VERSION 5.8 ;
BUSBITCHARS "[]" ;
DIVIDERCHAR "/" ;
UNITS
    DATABASE MICRONS 1000 ;
END UNITS

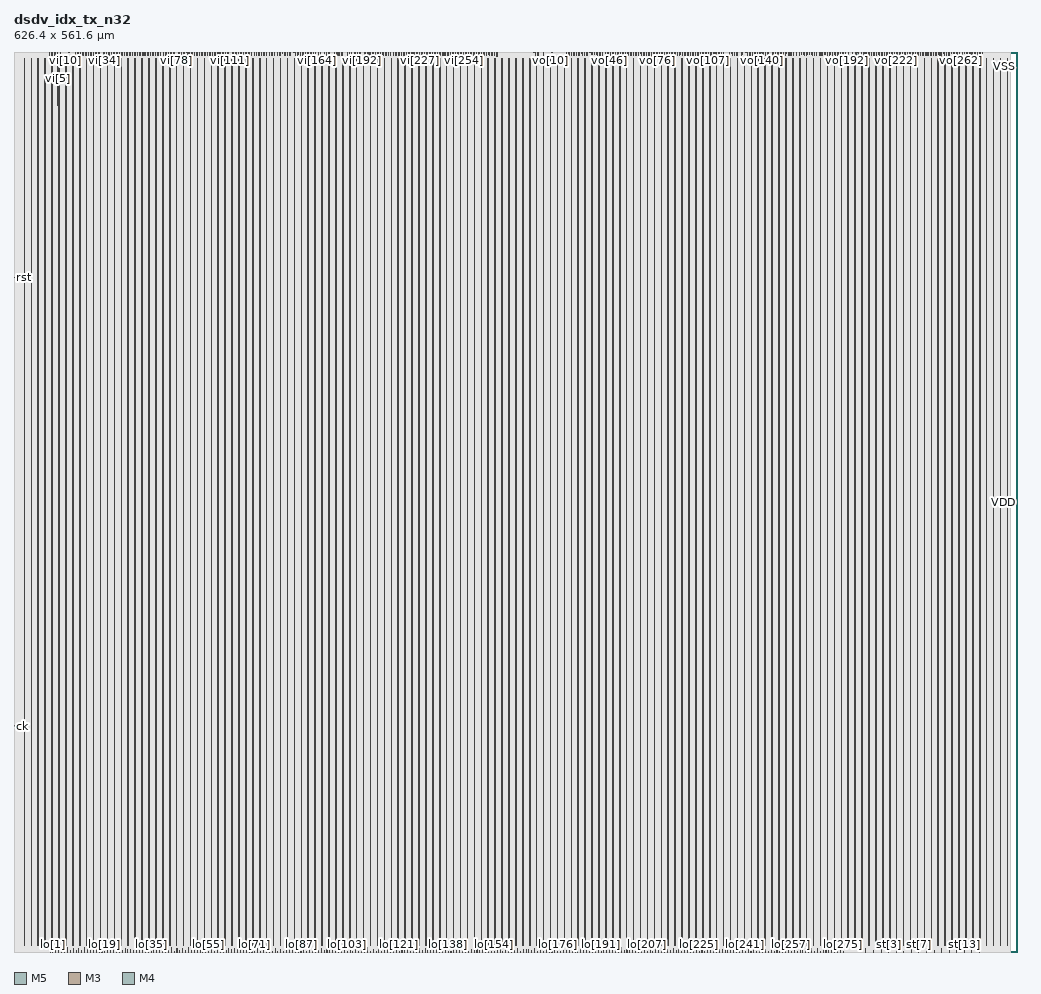
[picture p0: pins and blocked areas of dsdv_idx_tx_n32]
MACRO dsdv_idx_tx_n32
  FOREIGN dsdv_idx_tx_n32 0 0 ;
  CLASS BLOCK ;
  SIZE 626.4 BY 561.6 ;
  PIN ck
    DIRECTION INPUT ;
    USE SIGNAL ;
    PORT
      LAYER M5 ;
        RECT  0 140.652 0.12 141.132 ;
    END
  END ck
  PIN lo[0]
    DIRECTION OUTPUT ;
    USE SIGNAL ;
    PORT
      LAYER M3 ;
        RECT  22.5 0.012 22.518 2.227 ;
        RECT  22.5 0 22.518 0.038 ;
    END
  END lo[0]
  PIN lo[100]
    DIRECTION OUTPUT ;
    USE SIGNAL ;
    PORT
      LAYER M3 ;
        RECT  202.5 0.012 202.518 1.606 ;
        RECT  202.5 0 202.518 0.038 ;
    END
  END lo[100]
  PIN lo[101]
    DIRECTION OUTPUT ;
    USE SIGNAL ;
    PORT
      LAYER M5 ;
        RECT  204.288 0.016 204.312 1.187 ;
        RECT  204.288 0 204.312 0.084 ;
    END
  END lo[101]
  PIN lo[102]
    DIRECTION OUTPUT ;
    USE SIGNAL ;
    PORT
      LAYER M3 ;
        RECT  206.1 0.012 206.118 1.021 ;
        RECT  206.1 0 206.118 0.038 ;
    END
  END lo[102]
  PIN lo[103]
    DIRECTION OUTPUT ;
    USE SIGNAL ;
    PORT
      LAYER M5 ;
        RECT  207.888 0.016 207.912 0.131 ;
        RECT  207.888 0 207.912 0.084 ;
    END
  END lo[103]
  PIN lo[104]
    DIRECTION OUTPUT ;
    USE SIGNAL ;
    PORT
      LAYER M3 ;
        RECT  209.7 0.012 209.718 0.949 ;
        RECT  209.7 0 209.718 0.038 ;
    END
  END lo[104]
  PIN lo[105]
    DIRECTION OUTPUT ;
    USE SIGNAL ;
    PORT
      LAYER M5 ;
        RECT  211.488 0.016 211.512 0.131 ;
        RECT  211.488 0 211.512 0.084 ;
    END
  END lo[105]
  PIN lo[106]
    DIRECTION OUTPUT ;
    USE SIGNAL ;
    PORT
      LAYER M3 ;
        RECT  213.3 0.012 213.318 1.723 ;
        RECT  213.3 0 213.318 0.038 ;
    END
  END lo[106]
  PIN lo[107]
    DIRECTION OUTPUT ;
    USE SIGNAL ;
    PORT
      LAYER M5 ;
        RECT  215.088 0.016 215.112 0.131 ;
        RECT  215.088 0 215.112 0.084 ;
    END
  END lo[107]
  PIN lo[108]
    DIRECTION OUTPUT ;
    USE SIGNAL ;
    PORT
      LAYER M3 ;
        RECT  216.9 0.012 216.918 1.723 ;
        RECT  216.9 0 216.918 0.038 ;
    END
  END lo[108]
  PIN lo[109]
    DIRECTION OUTPUT ;
    USE SIGNAL ;
    PORT
      LAYER M5 ;
        RECT  218.688 0.016 218.712 1.187 ;
        RECT  218.688 0 218.712 0.084 ;
    END
  END lo[109]
  PIN lo[10]
    DIRECTION OUTPUT ;
    USE SIGNAL ;
    PORT
      LAYER M3 ;
        RECT  40.5 0.012 40.518 2.143 ;
        RECT  40.5 0 40.518 0.038 ;
    END
  END lo[10]
  PIN lo[110]
    DIRECTION OUTPUT ;
    USE SIGNAL ;
    PORT
      LAYER M3 ;
        RECT  220.5 0.012 220.518 2.767 ;
        RECT  220.5 0 220.518 0.038 ;
    END
  END lo[110]
  PIN lo[111]
    DIRECTION OUTPUT ;
    USE SIGNAL ;
    PORT
      LAYER M5 ;
        RECT  222.288 0.016 222.312 0.131 ;
        RECT  222.288 0 222.312 0.084 ;
    END
  END lo[111]
  PIN lo[112]
    DIRECTION OUTPUT ;
    USE SIGNAL ;
    PORT
      LAYER M3 ;
        RECT  224.1 0.012 224.118 1.723 ;
        RECT  224.1 0 224.118 0.038 ;
    END
  END lo[112]
  PIN lo[113]
    DIRECTION OUTPUT ;
    USE SIGNAL ;
    PORT
      LAYER M5 ;
        RECT  225.888 0.016 225.912 0.131 ;
        RECT  225.888 0 225.912 0.084 ;
    END
  END lo[113]
  PIN lo[114]
    DIRECTION OUTPUT ;
    USE SIGNAL ;
    PORT
      LAYER M3 ;
        RECT  227.7 0.012 227.718 2.219 ;
        RECT  227.7 0 227.718 0.038 ;
    END
  END lo[114]
  PIN lo[115]
    DIRECTION OUTPUT ;
    USE SIGNAL ;
    PORT
      LAYER M5 ;
        RECT  229.488 0.016 229.512 0.131 ;
        RECT  229.488 0 229.512 0.084 ;
    END
  END lo[115]
  PIN lo[116]
    DIRECTION OUTPUT ;
    USE SIGNAL ;
    PORT
      LAYER M3 ;
        RECT  231.3 0.012 231.318 1.993 ;
        RECT  231.3 0 231.318 0.038 ;
    END
  END lo[116]
  PIN lo[117]
    DIRECTION OUTPUT ;
    USE SIGNAL ;
    PORT
      LAYER M5 ;
        RECT  233.088 0.016 233.112 1.763 ;
        RECT  233.088 0 233.112 0.084 ;
    END
  END lo[117]
  PIN lo[118]
    DIRECTION OUTPUT ;
    USE SIGNAL ;
    PORT
      LAYER M3 ;
        RECT  234.9 0.012 234.918 2.143 ;
        RECT  234.9 0 234.918 0.038 ;
    END
  END lo[118]
  PIN lo[119]
    DIRECTION OUTPUT ;
    USE SIGNAL ;
    PORT
      LAYER M5 ;
        RECT  236.688 0.016 236.712 0.131 ;
        RECT  236.688 0 236.712 0.084 ;
    END
  END lo[119]
  PIN lo[11]
    DIRECTION OUTPUT ;
    USE SIGNAL ;
    PORT
      LAYER M5 ;
        RECT  42.288 0.016 42.312 1.187 ;
        RECT  42.288 0 42.312 0.084 ;
    END
  END lo[11]
  PIN lo[120]
    DIRECTION OUTPUT ;
    USE SIGNAL ;
    PORT
      LAYER M3 ;
        RECT  238.5 0.012 238.518 1.723 ;
        RECT  238.5 0 238.518 0.038 ;
    END
  END lo[120]
  PIN lo[121]
    DIRECTION OUTPUT ;
    USE SIGNAL ;
    PORT
      LAYER M5 ;
        RECT  240.288 0.016 240.312 0.085 ;
        RECT  240.288 0 240.312 0.084 ;
    END
  END lo[121]
  PIN lo[122]
    DIRECTION OUTPUT ;
    USE SIGNAL ;
    PORT
      LAYER M3 ;
        RECT  242.1 0.012 242.118 2.029 ;
        RECT  242.1 0 242.118 0.038 ;
    END
  END lo[122]
  PIN lo[123]
    DIRECTION OUTPUT ;
    USE SIGNAL ;
    PORT
      LAYER M5 ;
        RECT  243.888 0.016 243.912 1.187 ;
        RECT  243.888 0 243.912 0.084 ;
    END
  END lo[123]
  PIN lo[124]
    DIRECTION OUTPUT ;
    USE SIGNAL ;
    PORT
      LAYER M3 ;
        RECT  245.7 0.012 245.718 2.143 ;
        RECT  245.7 0 245.718 0.038 ;
    END
  END lo[124]
  PIN lo[125]
    DIRECTION OUTPUT ;
    USE SIGNAL ;
    PORT
      LAYER M5 ;
        RECT  247.488 0.016 247.512 0.131 ;
        RECT  247.488 0 247.512 0.084 ;
    END
  END lo[125]
  PIN lo[126]
    DIRECTION OUTPUT ;
    USE SIGNAL ;
    PORT
      LAYER M3 ;
        RECT  249.3 0.012 249.318 1.723 ;
        RECT  249.3 0 249.318 0.038 ;
    END
  END lo[126]
  PIN lo[127]
    DIRECTION OUTPUT ;
    USE SIGNAL ;
    PORT
      LAYER M5 ;
        RECT  251.088 0.016 251.112 1.187 ;
        RECT  251.088 0 251.112 0.084 ;
    END
  END lo[127]
  PIN lo[128]
    DIRECTION OUTPUT ;
    USE SIGNAL ;
    PORT
      LAYER M3 ;
        RECT  252.9 0.012 252.918 2.219 ;
        RECT  252.9 0 252.918 0.038 ;
    END
  END lo[128]
  PIN lo[129]
    DIRECTION OUTPUT ;
    USE SIGNAL ;
    PORT
      LAYER M5 ;
        RECT  254.688 0.016 254.712 1.187 ;
        RECT  254.688 0 254.712 0.084 ;
    END
  END lo[129]
  PIN lo[12]
    DIRECTION OUTPUT ;
    USE SIGNAL ;
    PORT
      LAYER M3 ;
        RECT  44.1 0.012 44.118 2.669 ;
        RECT  44.1 0 44.118 0.038 ;
    END
  END lo[12]
  PIN lo[130]
    DIRECTION OUTPUT ;
    USE SIGNAL ;
    PORT
      LAYER M3 ;
        RECT  256.5 0.012 256.518 2.143 ;
        RECT  256.5 0 256.518 0.038 ;
    END
  END lo[130]
  PIN lo[131]
    DIRECTION OUTPUT ;
    USE SIGNAL ;
    PORT
      LAYER M5 ;
        RECT  258.288 0.016 258.312 1.187 ;
        RECT  258.288 0 258.312 0.084 ;
    END
  END lo[131]
  PIN lo[132]
    DIRECTION OUTPUT ;
    USE SIGNAL ;
    PORT
      LAYER M3 ;
        RECT  260.1 0.012 260.118 1.066 ;
        RECT  260.1 0 260.118 0.038 ;
    END
  END lo[132]
  PIN lo[133]
    DIRECTION OUTPUT ;
    USE SIGNAL ;
    PORT
      LAYER M5 ;
        RECT  261.888 0.016 261.912 2.137 ;
        RECT  261.888 0 261.912 0.084 ;
    END
  END lo[133]
  PIN lo[134]
    DIRECTION OUTPUT ;
    USE SIGNAL ;
    PORT
      LAYER M3 ;
        RECT  263.7 0.012 263.718 1.723 ;
        RECT  263.7 0 263.718 0.038 ;
    END
  END lo[134]
  PIN lo[135]
    DIRECTION OUTPUT ;
    USE SIGNAL ;
    PORT
      LAYER M5 ;
        RECT  265.488 0.016 265.512 1.763 ;
        RECT  265.488 0 265.512 0.084 ;
    END
  END lo[135]
  PIN lo[136]
    DIRECTION OUTPUT ;
    USE SIGNAL ;
    PORT
      LAYER M3 ;
        RECT  267.3 0.012 267.318 1.723 ;
        RECT  267.3 0 267.318 0.038 ;
    END
  END lo[136]
  PIN lo[137]
    DIRECTION OUTPUT ;
    USE SIGNAL ;
    PORT
      LAYER M5 ;
        RECT  269.088 0.016 269.112 1.187 ;
        RECT  269.088 0 269.112 0.084 ;
    END
  END lo[137]
  PIN lo[138]
    DIRECTION OUTPUT ;
    USE SIGNAL ;
    PORT
      LAYER M3 ;
        RECT  270.9 0.012 270.918 0.077 ;
        RECT  270.9 0 270.918 0.038 ;
    END
  END lo[138]
  PIN lo[139]
    DIRECTION OUTPUT ;
    USE SIGNAL ;
    PORT
      LAYER M5 ;
        RECT  272.688 0.016 272.712 0.131 ;
        RECT  272.688 0 272.712 0.084 ;
    END
  END lo[139]
  PIN lo[13]
    DIRECTION OUTPUT ;
    USE SIGNAL ;
    PORT
      LAYER M5 ;
        RECT  45.888 0.016 45.912 2.137 ;
        RECT  45.888 0 45.912 0.084 ;
    END
  END lo[13]
  PIN lo[140]
    DIRECTION OUTPUT ;
    USE SIGNAL ;
    PORT
      LAYER M3 ;
        RECT  274.5 0.012 274.518 1.723 ;
        RECT  274.5 0 274.518 0.038 ;
    END
  END lo[140]
  PIN lo[141]
    DIRECTION OUTPUT ;
    USE SIGNAL ;
    PORT
      LAYER M5 ;
        RECT  276.288 0.016 276.312 1.187 ;
        RECT  276.288 0 276.312 0.084 ;
    END
  END lo[141]
  PIN lo[142]
    DIRECTION OUTPUT ;
    USE SIGNAL ;
    PORT
      LAYER M3 ;
        RECT  278.1 0.012 278.118 1.687 ;
        RECT  278.1 0 278.118 0.038 ;
    END
  END lo[142]
  PIN lo[143]
    DIRECTION OUTPUT ;
    USE SIGNAL ;
    PORT
      LAYER M5 ;
        RECT  279.888 0.016 279.912 1.187 ;
        RECT  279.888 0 279.912 0.084 ;
    END
  END lo[143]
  PIN lo[144]
    DIRECTION OUTPUT ;
    USE SIGNAL ;
    PORT
      LAYER M3 ;
        RECT  281.7 0.012 281.718 2.029 ;
        RECT  281.7 0 281.718 0.038 ;
    END
  END lo[144]
  PIN lo[145]
    DIRECTION OUTPUT ;
    USE SIGNAL ;
    PORT
      LAYER M5 ;
        RECT  283.488 0.016 283.512 0.085 ;
        RECT  283.488 0 283.512 0.084 ;
    END
  END lo[145]
  PIN lo[146]
    DIRECTION OUTPUT ;
    USE SIGNAL ;
    PORT
      LAYER M3 ;
        RECT  285.3 0.012 285.318 1.723 ;
        RECT  285.3 0 285.318 0.038 ;
    END
  END lo[146]
  PIN lo[147]
    DIRECTION OUTPUT ;
    USE SIGNAL ;
    PORT
      LAYER M5 ;
        RECT  287.088 0.016 287.112 1.187 ;
        RECT  287.088 0 287.112 0.084 ;
    END
  END lo[147]
  PIN lo[148]
    DIRECTION OUTPUT ;
    USE SIGNAL ;
    PORT
      LAYER M3 ;
        RECT  288.9 0.012 288.918 2.059 ;
        RECT  288.9 0 288.918 0.038 ;
    END
  END lo[148]
  PIN lo[149]
    DIRECTION OUTPUT ;
    USE SIGNAL ;
    PORT
      LAYER M5 ;
        RECT  290.688 0.016 290.712 1.187 ;
        RECT  290.688 0 290.712 0.084 ;
    END
  END lo[149]
  PIN lo[14]
    DIRECTION OUTPUT ;
    USE SIGNAL ;
    PORT
      LAYER M3 ;
        RECT  47.7 0.012 47.718 2.219 ;
        RECT  47.7 0 47.718 0.038 ;
    END
  END lo[14]
  PIN lo[150]
    DIRECTION OUTPUT ;
    USE SIGNAL ;
    PORT
      LAYER M3 ;
        RECT  292.5 0.012 292.518 1.525 ;
        RECT  292.5 0 292.518 0.038 ;
    END
  END lo[150]
  PIN lo[151]
    DIRECTION OUTPUT ;
    USE SIGNAL ;
    PORT
      LAYER M5 ;
        RECT  294.288 0.016 294.312 0.131 ;
        RECT  294.288 0 294.312 0.084 ;
    END
  END lo[151]
  PIN lo[152]
    DIRECTION OUTPUT ;
    USE SIGNAL ;
    PORT
      LAYER M3 ;
        RECT  296.1 0.012 296.118 1.561 ;
        RECT  296.1 0 296.118 0.038 ;
    END
  END lo[152]
  PIN lo[153]
    DIRECTION OUTPUT ;
    USE SIGNAL ;
    PORT
      LAYER M5 ;
        RECT  297.888 0.016 297.912 0.131 ;
        RECT  297.888 0 297.912 0.084 ;
    END
  END lo[153]
  PIN lo[154]
    DIRECTION OUTPUT ;
    USE SIGNAL ;
    PORT
      LAYER M3 ;
        RECT  299.7 0.031 299.79 0.059 ;
        RECT  299.7 0.012 299.718 0.031 ;
        RECT  299.7 0 299.718 0.038 ;
    END
  END lo[154]
  PIN lo[155]
    DIRECTION OUTPUT ;
    USE SIGNAL ;
    PORT
      LAYER M5 ;
        RECT  301.488 0.016 301.512 1.187 ;
        RECT  301.488 0 301.512 0.084 ;
    END
  END lo[155]
  PIN lo[156]
    DIRECTION OUTPUT ;
    USE SIGNAL ;
    PORT
      LAYER M3 ;
        RECT  303.3 0.012 303.318 2.227 ;
        RECT  303.3 0 303.318 0.038 ;
    END
  END lo[156]
  PIN lo[157]
    DIRECTION OUTPUT ;
    USE SIGNAL ;
    PORT
      LAYER M5 ;
        RECT  305.088 0.016 305.112 0.131 ;
        RECT  305.088 0 305.112 0.084 ;
    END
  END lo[157]
  PIN lo[158]
    DIRECTION OUTPUT ;
    USE SIGNAL ;
    PORT
      LAYER M3 ;
        RECT  306.9 0.012 306.918 2.569 ;
        RECT  306.9 0 306.918 0.038 ;
    END
  END lo[158]
  PIN lo[159]
    DIRECTION OUTPUT ;
    USE SIGNAL ;
    PORT
      LAYER M5 ;
        RECT  308.688 0.016 308.712 0.131 ;
        RECT  308.688 0 308.712 0.084 ;
    END
  END lo[159]
  PIN lo[15]
    DIRECTION OUTPUT ;
    USE SIGNAL ;
    PORT
      LAYER M5 ;
        RECT  49.488 0.016 49.512 1.763 ;
        RECT  49.488 0 49.512 0.084 ;
    END
  END lo[15]
  PIN lo[160]
    DIRECTION OUTPUT ;
    USE SIGNAL ;
    PORT
      LAYER M3 ;
        RECT  310.5 0.012 310.518 2.143 ;
        RECT  310.5 0 310.518 0.038 ;
    END
  END lo[160]
  PIN lo[161]
    DIRECTION OUTPUT ;
    USE SIGNAL ;
    PORT
      LAYER M5 ;
        RECT  312.288 0.016 312.312 1.187 ;
        RECT  312.288 0 312.312 0.084 ;
    END
  END lo[161]
  PIN lo[162]
    DIRECTION OUTPUT ;
    USE SIGNAL ;
    PORT
      LAYER M3 ;
        RECT  314.1 0.012 314.118 1.993 ;
        RECT  314.1 0 314.118 0.038 ;
    END
  END lo[162]
  PIN lo[163]
    DIRECTION OUTPUT ;
    USE SIGNAL ;
    PORT
      LAYER M5 ;
        RECT  315.888 0.016 315.912 0.611 ;
        RECT  315.888 0 315.912 0.084 ;
    END
  END lo[163]
  PIN lo[164]
    DIRECTION OUTPUT ;
    USE SIGNAL ;
    PORT
      LAYER M3 ;
        RECT  317.7 0.012 317.718 1.723 ;
        RECT  317.7 0 317.718 0.038 ;
    END
  END lo[164]
  PIN lo[165]
    DIRECTION OUTPUT ;
    USE SIGNAL ;
    PORT
      LAYER M5 ;
        RECT  319.488 0.016 319.512 1.763 ;
        RECT  319.488 0 319.512 0.084 ;
    END
  END lo[165]
  PIN lo[166]
    DIRECTION OUTPUT ;
    USE SIGNAL ;
    PORT
      LAYER M3 ;
        RECT  321.3 0.012 321.318 1.723 ;
        RECT  321.3 0 321.318 0.038 ;
    END
  END lo[166]
  PIN lo[167]
    DIRECTION OUTPUT ;
    USE SIGNAL ;
    PORT
      LAYER M5 ;
        RECT  323.088 0.016 323.112 1.187 ;
        RECT  323.088 0 323.112 0.084 ;
    END
  END lo[167]
  PIN lo[168]
    DIRECTION OUTPUT ;
    USE SIGNAL ;
    PORT
      LAYER M3 ;
        RECT  324.9 0.012 324.918 2.101 ;
        RECT  324.9 0 324.918 0.038 ;
    END
  END lo[168]
  PIN lo[169]
    DIRECTION OUTPUT ;
    USE SIGNAL ;
    PORT
      LAYER M5 ;
        RECT  326.688 0.016 326.712 0.611 ;
        RECT  326.688 0 326.712 0.084 ;
    END
  END lo[169]
  PIN lo[16]
    DIRECTION OUTPUT ;
    USE SIGNAL ;
    PORT
      LAYER M3 ;
        RECT  51.3 0.012 51.318 2.143 ;
        RECT  51.3 0 51.318 0.038 ;
    END
  END lo[16]
  PIN lo[170]
    DIRECTION OUTPUT ;
    USE SIGNAL ;
    PORT
      LAYER M3 ;
        RECT  328.5 0.012 328.518 1.723 ;
        RECT  328.5 0 328.518 0.038 ;
    END
  END lo[170]
  PIN lo[171]
    DIRECTION OUTPUT ;
    USE SIGNAL ;
    PORT
      LAYER M5 ;
        RECT  330.288 0.016 330.312 0.131 ;
        RECT  330.288 0 330.312 0.084 ;
    END
  END lo[171]
  PIN lo[172]
    DIRECTION OUTPUT ;
    USE SIGNAL ;
    PORT
      LAYER M3 ;
        RECT  332.1 0.012 332.118 2.143 ;
        RECT  332.1 0 332.118 0.038 ;
    END
  END lo[172]
  PIN lo[173]
    DIRECTION OUTPUT ;
    USE SIGNAL ;
    PORT
      LAYER M5 ;
        RECT  333.888 0.016 333.912 1.763 ;
        RECT  333.888 0 333.912 0.084 ;
    END
  END lo[173]
  PIN lo[174]
    DIRECTION OUTPUT ;
    USE SIGNAL ;
    PORT
      LAYER M3 ;
        RECT  335.7 0.012 335.718 2.101 ;
        RECT  335.7 0 335.718 0.038 ;
    END
  END lo[174]
  PIN lo[175]
    DIRECTION OUTPUT ;
    USE SIGNAL ;
    PORT
      LAYER M5 ;
        RECT  337.488 0.016 337.512 1.187 ;
        RECT  337.488 0 337.512 0.084 ;
    END
  END lo[175]
  PIN lo[176]
    DIRECTION OUTPUT ;
    USE SIGNAL ;
    PORT
      LAYER M3 ;
        RECT  339.3 0.012 339.318 0.077 ;
        RECT  339.3 0 339.318 0.038 ;
    END
  END lo[176]
  PIN lo[177]
    DIRECTION OUTPUT ;
    USE SIGNAL ;
    PORT
      LAYER M5 ;
        RECT  341.088 0.016 341.112 0.131 ;
        RECT  341.088 0 341.112 0.084 ;
    END
  END lo[177]
  PIN lo[178]
    DIRECTION OUTPUT ;
    USE SIGNAL ;
    PORT
      LAYER M3 ;
        RECT  342.9 0.012 342.918 1.021 ;
        RECT  342.9 0 342.918 0.038 ;
    END
  END lo[178]
  PIN lo[179]
    DIRECTION OUTPUT ;
    USE SIGNAL ;
    PORT
      LAYER M5 ;
        RECT  344.688 0.016 344.712 1.187 ;
        RECT  344.688 0 344.712 0.084 ;
    END
  END lo[179]
  PIN lo[17]
    DIRECTION OUTPUT ;
    USE SIGNAL ;
    PORT
      LAYER M5 ;
        RECT  53.088 0.016 53.112 0.611 ;
        RECT  53.088 0 53.112 0.084 ;
    END
  END lo[17]
  PIN lo[180]
    DIRECTION OUTPUT ;
    USE SIGNAL ;
    PORT
      LAYER M3 ;
        RECT  346.5 0.012 346.518 2.129 ;
        RECT  346.5 0 346.518 0.038 ;
    END
  END lo[180]
  PIN lo[181]
    DIRECTION OUTPUT ;
    USE SIGNAL ;
    PORT
      LAYER M5 ;
        RECT  348.288 0.016 348.312 0.611 ;
        RECT  348.288 0 348.312 0.084 ;
    END
  END lo[181]
  PIN lo[182]
    DIRECTION OUTPUT ;
    USE SIGNAL ;
    PORT
      LAYER M3 ;
        RECT  350.1 0.012 350.118 2.219 ;
        RECT  350.1 0 350.118 0.038 ;
    END
  END lo[182]
  PIN lo[183]
    DIRECTION OUTPUT ;
    USE SIGNAL ;
    PORT
      LAYER M5 ;
        RECT  351.888 0.016 351.912 1.187 ;
        RECT  351.888 0 351.912 0.084 ;
    END
  END lo[183]
  PIN lo[184]
    DIRECTION OUTPUT ;
    USE SIGNAL ;
    PORT
      LAYER M3 ;
        RECT  353.7 0.012 353.718 2.101 ;
        RECT  353.7 0 353.718 0.038 ;
    END
  END lo[184]
  PIN lo[185]
    DIRECTION OUTPUT ;
    USE SIGNAL ;
    PORT
      LAYER M5 ;
        RECT  355.488 0.016 355.512 1.187 ;
        RECT  355.488 0 355.512 0.084 ;
    END
  END lo[185]
  PIN lo[186]
    DIRECTION OUTPUT ;
    USE SIGNAL ;
    PORT
      LAYER M3 ;
        RECT  357.3 0.012 357.318 2.101 ;
        RECT  357.3 0 357.318 0.038 ;
    END
  END lo[186]
  PIN lo[187]
    DIRECTION OUTPUT ;
    USE SIGNAL ;
    PORT
      LAYER M5 ;
        RECT  359.088 0.016 359.112 0.131 ;
        RECT  359.088 0 359.112 0.084 ;
    END
  END lo[187]
  PIN lo[188]
    DIRECTION OUTPUT ;
    USE SIGNAL ;
    PORT
      LAYER M3 ;
        RECT  360.9 0.012 360.918 2.605 ;
        RECT  360.9 0 360.918 0.038 ;
    END
  END lo[188]
  PIN lo[189]
    DIRECTION OUTPUT ;
    USE SIGNAL ;
    PORT
      LAYER M5 ;
        RECT  362.688 0.016 362.712 0.131 ;
        RECT  362.688 0 362.712 0.084 ;
    END
  END lo[189]
  PIN lo[18]
    DIRECTION OUTPUT ;
    USE SIGNAL ;
    PORT
      LAYER M3 ;
        RECT  54.9 0.012 54.918 2.291 ;
        RECT  54.9 0 54.918 0.038 ;
    END
  END lo[18]
  PIN lo[190]
    DIRECTION OUTPUT ;
    USE SIGNAL ;
    PORT
      LAYER M3 ;
        RECT  364.5 0.012 364.518 2.143 ;
        RECT  364.5 0 364.518 0.038 ;
    END
  END lo[190]
  PIN lo[191]
    DIRECTION OUTPUT ;
    USE SIGNAL ;
    PORT
      LAYER M5 ;
        RECT  366.288 0.016 366.312 0.131 ;
        RECT  366.288 0 366.312 0.084 ;
    END
  END lo[191]
  PIN lo[192]
    DIRECTION OUTPUT ;
    USE SIGNAL ;
    PORT
      LAYER M3 ;
        RECT  368.1 0.012 368.118 2.191 ;
        RECT  368.1 0 368.118 0.038 ;
    END
  END lo[192]
  PIN lo[193]
    DIRECTION OUTPUT ;
    USE SIGNAL ;
    PORT
      LAYER M5 ;
        RECT  369.888 0.016 369.912 1.187 ;
        RECT  369.888 0 369.912 0.084 ;
    END
  END lo[193]
  PIN lo[194]
    DIRECTION OUTPUT ;
    USE SIGNAL ;
    PORT
      LAYER M3 ;
        RECT  371.7 0.012 371.718 2.219 ;
        RECT  371.7 0 371.718 0.038 ;
    END
  END lo[194]
  PIN lo[195]
    DIRECTION OUTPUT ;
    USE SIGNAL ;
    PORT
      LAYER M5 ;
        RECT  373.488 0.016 373.512 1.187 ;
        RECT  373.488 0 373.512 0.084 ;
    END
  END lo[195]
  PIN lo[196]
    DIRECTION OUTPUT ;
    USE SIGNAL ;
    PORT
      LAYER M3 ;
        RECT  375.3 0.012 375.318 2.143 ;
        RECT  375.3 0 375.318 0.038 ;
    END
  END lo[196]
  PIN lo[197]
    DIRECTION OUTPUT ;
    USE SIGNAL ;
    PORT
      LAYER M5 ;
        RECT  377.088 0.016 377.112 1.187 ;
        RECT  377.088 0 377.112 0.084 ;
    END
  END lo[197]
  PIN lo[198]
    DIRECTION OUTPUT ;
    USE SIGNAL ;
    PORT
      LAYER M3 ;
        RECT  378.9 0.012 378.918 2.569 ;
        RECT  378.9 0 378.918 0.038 ;
    END
  END lo[198]
  PIN lo[199]
    DIRECTION OUTPUT ;
    USE SIGNAL ;
    PORT
      LAYER M5 ;
        RECT  380.688 0.016 380.712 1.187 ;
        RECT  380.688 0 380.712 0.084 ;
    END
  END lo[199]
  PIN lo[19]
    DIRECTION OUTPUT ;
    USE SIGNAL ;
    PORT
      LAYER M5 ;
        RECT  56.688 0.016 56.712 0.131 ;
        RECT  56.688 0 56.712 0.084 ;
    END
  END lo[19]
  PIN lo[1]
    DIRECTION OUTPUT ;
    USE SIGNAL ;
    PORT
      LAYER M5 ;
        RECT  24.288 0.016 24.312 0.131 ;
        RECT  24.288 0 24.312 0.084 ;
    END
  END lo[1]
  PIN lo[200]
    DIRECTION OUTPUT ;
    USE SIGNAL ;
    PORT
      LAYER M3 ;
        RECT  382.5 0.012 382.518 1.723 ;
        RECT  382.5 0 382.518 0.038 ;
    END
  END lo[200]
  PIN lo[201]
    DIRECTION OUTPUT ;
    USE SIGNAL ;
    PORT
      LAYER M5 ;
        RECT  384.288 0.016 384.312 1.187 ;
        RECT  384.288 0 384.312 0.084 ;
    END
  END lo[201]
  PIN lo[202]
    DIRECTION OUTPUT ;
    USE SIGNAL ;
    PORT
      LAYER M3 ;
        RECT  386.1 0.012 386.118 2.143 ;
        RECT  386.1 0 386.118 0.038 ;
    END
  END lo[202]
  PIN lo[203]
    DIRECTION OUTPUT ;
    USE SIGNAL ;
    PORT
      LAYER M5 ;
        RECT  387.888 0.016 387.912 0.131 ;
        RECT  387.888 0 387.912 0.084 ;
    END
  END lo[203]
  PIN lo[204]
    DIRECTION OUTPUT ;
    USE SIGNAL ;
    PORT
      LAYER M3 ;
        RECT  389.7 0.012 389.718 2.129 ;
        RECT  389.7 0 389.718 0.038 ;
    END
  END lo[204]
  PIN lo[205]
    DIRECTION OUTPUT ;
    USE SIGNAL ;
    PORT
      LAYER M5 ;
        RECT  391.488 0.016 391.512 1.187 ;
        RECT  391.488 0 391.512 0.084 ;
    END
  END lo[205]
  PIN lo[206]
    DIRECTION OUTPUT ;
    USE SIGNAL ;
    PORT
      LAYER M3 ;
        RECT  393.3 0.012 393.318 2.219 ;
        RECT  393.3 0 393.318 0.038 ;
    END
  END lo[206]
  PIN lo[207]
    DIRECTION OUTPUT ;
    USE SIGNAL ;
    PORT
      LAYER M5 ;
        RECT  395.088 0.016 395.112 0.131 ;
        RECT  395.088 0 395.112 0.084 ;
    END
  END lo[207]
  PIN lo[208]
    DIRECTION OUTPUT ;
    USE SIGNAL ;
    PORT
      LAYER M3 ;
        RECT  396.9 0.012 396.918 1.723 ;
        RECT  396.9 0 396.918 0.038 ;
    END
  END lo[208]
  PIN lo[209]
    DIRECTION OUTPUT ;
    USE SIGNAL ;
    PORT
      LAYER M5 ;
        RECT  398.688 0.016 398.712 0.131 ;
        RECT  398.688 0 398.712 0.084 ;
    END
  END lo[209]
  PIN lo[20]
    DIRECTION OUTPUT ;
    USE SIGNAL ;
    PORT
      LAYER M3 ;
        RECT  58.5 0.012 58.518 2.227 ;
        RECT  58.5 0 58.518 0.038 ;
    END
  END lo[20]
  PIN lo[210]
    DIRECTION OUTPUT ;
    USE SIGNAL ;
    PORT
      LAYER M3 ;
        RECT  400.5 0.012 400.518 2.219 ;
        RECT  400.5 0 400.518 0.038 ;
    END
  END lo[210]
  PIN lo[211]
    DIRECTION OUTPUT ;
    USE SIGNAL ;
    PORT
      LAYER M5 ;
        RECT  402.288 0.016 402.312 1.187 ;
        RECT  402.288 0 402.312 0.084 ;
    END
  END lo[211]
  PIN lo[212]
    DIRECTION OUTPUT ;
    USE SIGNAL ;
    PORT
      LAYER M3 ;
        RECT  404.1 0.012 404.118 2.489 ;
        RECT  404.1 0 404.118 0.038 ;
    END
  END lo[212]
  PIN lo[213]
    DIRECTION OUTPUT ;
    USE SIGNAL ;
    PORT
      LAYER M5 ;
        RECT  405.888 0.016 405.912 0.131 ;
        RECT  405.888 0 405.912 0.084 ;
    END
  END lo[213]
  PIN lo[214]
    DIRECTION OUTPUT ;
    USE SIGNAL ;
    PORT
      LAYER M3 ;
        RECT  407.7 0.012 407.718 1.723 ;
        RECT  407.7 0 407.718 0.038 ;
    END
  END lo[214]
  PIN lo[215]
    DIRECTION OUTPUT ;
    USE SIGNAL ;
    PORT
      LAYER M5 ;
        RECT  409.488 0.016 409.512 1.187 ;
        RECT  409.488 0 409.512 0.084 ;
    END
  END lo[215]
  PIN lo[216]
    DIRECTION OUTPUT ;
    USE SIGNAL ;
    PORT
      LAYER M3 ;
        RECT  411.3 0.012 411.318 2.219 ;
        RECT  411.3 0 411.318 0.038 ;
    END
  END lo[216]
  PIN lo[217]
    DIRECTION OUTPUT ;
    USE SIGNAL ;
    PORT
      LAYER M5 ;
        RECT  413.088 0.016 413.112 1.187 ;
        RECT  413.088 0 413.112 0.084 ;
    END
  END lo[217]
  PIN lo[218]
    DIRECTION OUTPUT ;
    USE SIGNAL ;
    PORT
      LAYER M3 ;
        RECT  414.9 0.012 414.918 2.227 ;
        RECT  414.9 0 414.918 0.038 ;
    END
  END lo[218]
  PIN lo[219]
    DIRECTION OUTPUT ;
    USE SIGNAL ;
    PORT
      LAYER M5 ;
        RECT  416.688 0.016 416.712 0.611 ;
        RECT  416.688 0 416.712 0.084 ;
    END
  END lo[219]
  PIN lo[21]
    DIRECTION OUTPUT ;
    USE SIGNAL ;
    PORT
      LAYER M5 ;
        RECT  60.288 0.016 60.312 1.763 ;
        RECT  60.288 0 60.312 0.084 ;
    END
  END lo[21]
  PIN lo[220]
    DIRECTION OUTPUT ;
    USE SIGNAL ;
    PORT
      LAYER M3 ;
        RECT  418.5 0.012 418.518 2.143 ;
        RECT  418.5 0 418.518 0.038 ;
    END
  END lo[220]
  PIN lo[221]
    DIRECTION OUTPUT ;
    USE SIGNAL ;
    PORT
      LAYER M5 ;
        RECT  420.288 0.016 420.312 1.187 ;
        RECT  420.288 0 420.312 0.084 ;
    END
  END lo[221]
  PIN lo[222]
    DIRECTION OUTPUT ;
    USE SIGNAL ;
    PORT
      LAYER M3 ;
        RECT  422.1 0.012 422.118 1.723 ;
        RECT  422.1 0 422.118 0.038 ;
    END
  END lo[222]
  PIN lo[223]
    DIRECTION OUTPUT ;
    USE SIGNAL ;
    PORT
      LAYER M5 ;
        RECT  423.888 0.016 423.912 1.187 ;
        RECT  423.888 0 423.912 0.084 ;
    END
  END lo[223]
  PIN lo[224]
    DIRECTION OUTPUT ;
    USE SIGNAL ;
    PORT
      LAYER M3 ;
        RECT  425.7 0.012 425.718 2.263 ;
        RECT  425.7 0 425.718 0.038 ;
    END
  END lo[224]
  PIN lo[225]
    DIRECTION OUTPUT ;
    USE SIGNAL ;
    PORT
      LAYER M5 ;
        RECT  427.488 0.016 427.512 0.131 ;
        RECT  427.488 0 427.512 0.084 ;
    END
  END lo[225]
  PIN lo[226]
    DIRECTION OUTPUT ;
    USE SIGNAL ;
    PORT
      LAYER M3 ;
        RECT  429.3 0.012 429.318 2.143 ;
        RECT  429.3 0 429.318 0.038 ;
    END
  END lo[226]
  PIN lo[227]
    DIRECTION OUTPUT ;
    USE SIGNAL ;
    PORT
      LAYER M5 ;
        RECT  431.088 0.016 431.112 0.131 ;
        RECT  431.088 0 431.112 0.084 ;
    END
  END lo[227]
  PIN lo[228]
    DIRECTION OUTPUT ;
    USE SIGNAL ;
    PORT
      LAYER M3 ;
        RECT  432.9 0.012 432.918 2.263 ;
        RECT  432.9 0 432.918 0.038 ;
    END
  END lo[228]
  PIN lo[229]
    DIRECTION OUTPUT ;
    USE SIGNAL ;
    PORT
      LAYER M5 ;
        RECT  434.688 0.016 434.712 1.187 ;
        RECT  434.688 0 434.712 0.084 ;
    END
  END lo[229]
  PIN lo[22]
    DIRECTION OUTPUT ;
    USE SIGNAL ;
    PORT
      LAYER M3 ;
        RECT  62.1 0.012 62.118 2.129 ;
        RECT  62.1 0 62.118 0.038 ;
    END
  END lo[22]
  PIN lo[230]
    DIRECTION OUTPUT ;
    USE SIGNAL ;
    PORT
      LAYER M3 ;
        RECT  436.5 0.012 436.518 2.101 ;
        RECT  436.5 0 436.518 0.038 ;
    END
  END lo[230]
  PIN lo[231]
    DIRECTION OUTPUT ;
    USE SIGNAL ;
    PORT
      LAYER M5 ;
        RECT  438.288 0.016 438.312 1.187 ;
        RECT  438.288 0 438.312 0.084 ;
    END
  END lo[231]
  PIN lo[232]
    DIRECTION OUTPUT ;
    USE SIGNAL ;
    PORT
      LAYER M3 ;
        RECT  440.1 0.012 440.118 1.723 ;
        RECT  440.1 0 440.118 0.038 ;
    END
  END lo[232]
  PIN lo[233]
    DIRECTION OUTPUT ;
    USE SIGNAL ;
    PORT
      LAYER M5 ;
        RECT  441.888 0.016 441.912 1.763 ;
        RECT  441.888 0 441.912 0.084 ;
    END
  END lo[233]
  PIN lo[234]
    DIRECTION OUTPUT ;
    USE SIGNAL ;
    PORT
      LAYER M3 ;
        RECT  443.7 0.012 443.718 2.263 ;
        RECT  443.7 0 443.718 0.038 ;
    END
  END lo[234]
  PIN lo[235]
    DIRECTION OUTPUT ;
    USE SIGNAL ;
    PORT
      LAYER M5 ;
        RECT  445.488 0.016 445.512 2.137 ;
        RECT  445.488 0 445.512 0.084 ;
    END
  END lo[235]
  PIN lo[236]
    DIRECTION OUTPUT ;
    USE SIGNAL ;
    PORT
      LAYER M3 ;
        RECT  447.3 0.012 447.318 2.461 ;
        RECT  447.3 0 447.318 0.038 ;
    END
  END lo[236]
  PIN lo[237]
    DIRECTION OUTPUT ;
    USE SIGNAL ;
    PORT
      LAYER M5 ;
        RECT  449.088 0.016 449.112 1.187 ;
        RECT  449.088 0 449.112 0.084 ;
    END
  END lo[237]
  PIN lo[238]
    DIRECTION OUTPUT ;
    USE SIGNAL ;
    PORT
      LAYER M3 ;
        RECT  450.9 0.012 450.918 2.143 ;
        RECT  450.9 0 450.918 0.038 ;
    END
  END lo[238]
  PIN lo[239]
    DIRECTION OUTPUT ;
    USE SIGNAL ;
    PORT
      LAYER M5 ;
        RECT  452.688 0.016 452.712 0.131 ;
        RECT  452.688 0 452.712 0.084 ;
    END
  END lo[239]
  PIN lo[23]
    DIRECTION OUTPUT ;
    USE SIGNAL ;
    PORT
      LAYER M5 ;
        RECT  63.888 0.016 63.912 0.131 ;
        RECT  63.888 0 63.912 0.084 ;
    END
  END lo[23]
  PIN lo[240]
    DIRECTION OUTPUT ;
    USE SIGNAL ;
    PORT
      LAYER M3 ;
        RECT  454.5 0.012 454.518 2.101 ;
        RECT  454.5 0 454.518 0.038 ;
    END
  END lo[240]
  PIN lo[241]
    DIRECTION OUTPUT ;
    USE SIGNAL ;
    PORT
      LAYER M5 ;
        RECT  456.288 0.016 456.312 0.131 ;
        RECT  456.288 0 456.312 0.084 ;
    END
  END lo[241]
  PIN lo[242]
    DIRECTION OUTPUT ;
    USE SIGNAL ;
    PORT
      LAYER M3 ;
        RECT  458.1 0.012 458.118 1.723 ;
        RECT  458.1 0 458.118 0.038 ;
    END
  END lo[242]
  PIN lo[243]
    DIRECTION OUTPUT ;
    USE SIGNAL ;
    PORT
      LAYER M5 ;
        RECT  459.888 0.016 459.912 0.131 ;
        RECT  459.888 0 459.912 0.084 ;
    END
  END lo[243]
  PIN lo[244]
    DIRECTION OUTPUT ;
    USE SIGNAL ;
    PORT
      LAYER M3 ;
        RECT  461.7 0.012 461.718 2.143 ;
        RECT  461.7 0 461.718 0.038 ;
    END
  END lo[244]
  PIN lo[245]
    DIRECTION OUTPUT ;
    USE SIGNAL ;
    PORT
      LAYER M5 ;
        RECT  463.488 0.016 463.512 0.131 ;
        RECT  463.488 0 463.512 0.084 ;
    END
  END lo[245]
  PIN lo[246]
    DIRECTION OUTPUT ;
    USE SIGNAL ;
    PORT
      LAYER M3 ;
        RECT  465.3 0.012 465.318 2.263 ;
        RECT  465.3 0 465.318 0.038 ;
    END
  END lo[246]
  PIN lo[247]
    DIRECTION OUTPUT ;
    USE SIGNAL ;
    PORT
      LAYER M5 ;
        RECT  467.088 0.016 467.112 0.131 ;
        RECT  467.088 0 467.112 0.084 ;
    END
  END lo[247]
  PIN lo[248]
    DIRECTION OUTPUT ;
    USE SIGNAL ;
    PORT
      LAYER M3 ;
        RECT  468.9 0.012 468.918 1.723 ;
        RECT  468.9 0 468.918 0.038 ;
    END
  END lo[248]
  PIN lo[249]
    DIRECTION OUTPUT ;
    USE SIGNAL ;
    PORT
      LAYER M5 ;
        RECT  470.688 0.016 470.712 0.131 ;
        RECT  470.688 0 470.712 0.084 ;
    END
  END lo[249]
  PIN lo[24]
    DIRECTION OUTPUT ;
    USE SIGNAL ;
    PORT
      LAYER M3 ;
        RECT  65.7 0.012 65.718 1.723 ;
        RECT  65.7 0 65.718 0.038 ;
    END
  END lo[24]
  PIN lo[250]
    DIRECTION OUTPUT ;
    USE SIGNAL ;
    PORT
      LAYER M3 ;
        RECT  472.5 0.012 472.518 2.143 ;
        RECT  472.5 0 472.518 0.038 ;
    END
  END lo[250]
  PIN lo[251]
    DIRECTION OUTPUT ;
    USE SIGNAL ;
    PORT
      LAYER M5 ;
        RECT  474.288 0.016 474.312 0.131 ;
        RECT  474.288 0 474.312 0.084 ;
    END
  END lo[251]
  PIN lo[252]
    DIRECTION OUTPUT ;
    USE SIGNAL ;
    PORT
      LAYER M3 ;
        RECT  476.1 0.012 476.118 2.489 ;
        RECT  476.1 0 476.118 0.038 ;
    END
  END lo[252]
  PIN lo[253]
    DIRECTION OUTPUT ;
    USE SIGNAL ;
    PORT
      LAYER M5 ;
        RECT  477.888 0.016 477.912 0.131 ;
        RECT  477.888 0 477.912 0.084 ;
    END
  END lo[253]
  PIN lo[254]
    DIRECTION OUTPUT ;
    USE SIGNAL ;
    PORT
      LAYER M3 ;
        RECT  479.7 0.012 479.718 2.759 ;
        RECT  479.7 0 479.718 0.038 ;
    END
  END lo[254]
  PIN lo[255]
    DIRECTION OUTPUT ;
    USE SIGNAL ;
    PORT
      LAYER M5 ;
        RECT  481.488 0.016 481.512 1.187 ;
        RECT  481.488 0 481.512 0.084 ;
    END
  END lo[255]
  PIN lo[256]
    DIRECTION OUTPUT ;
    USE SIGNAL ;
    PORT
      LAYER M3 ;
        RECT  483.3 0.012 483.318 2.143 ;
        RECT  483.3 0 483.318 0.038 ;
    END
  END lo[256]
  PIN lo[257]
    DIRECTION OUTPUT ;
    USE SIGNAL ;
    PORT
      LAYER M5 ;
        RECT  485.088 0.016 485.112 0.131 ;
        RECT  485.088 0 485.112 0.084 ;
    END
  END lo[257]
  PIN lo[258]
    DIRECTION OUTPUT ;
    USE SIGNAL ;
    PORT
      LAYER M3 ;
        RECT  486.9 0.012 486.918 2.263 ;
        RECT  486.9 0 486.918 0.038 ;
    END
  END lo[258]
  PIN lo[259]
    DIRECTION OUTPUT ;
    USE SIGNAL ;
    PORT
      LAYER M5 ;
        RECT  488.688 0.016 488.712 0.611 ;
        RECT  488.688 0 488.712 0.084 ;
    END
  END lo[259]
  PIN lo[25]
    DIRECTION OUTPUT ;
    USE SIGNAL ;
    PORT
      LAYER M5 ;
        RECT  67.488 0.016 67.512 1.187 ;
        RECT  67.488 0 67.512 0.084 ;
    END
  END lo[25]
  PIN lo[260]
    DIRECTION OUTPUT ;
    USE SIGNAL ;
    PORT
      LAYER M3 ;
        RECT  490.5 0.012 490.518 3.299 ;
        RECT  490.5 0 490.518 0.038 ;
    END
  END lo[260]
  PIN lo[261]
    DIRECTION OUTPUT ;
    USE SIGNAL ;
    PORT
      LAYER M5 ;
        RECT  492.288 0.016 492.312 1.187 ;
        RECT  492.288 0 492.312 0.084 ;
    END
  END lo[261]
  PIN lo[262]
    DIRECTION OUTPUT ;
    USE SIGNAL ;
    PORT
      LAYER M3 ;
        RECT  494.1 0.012 494.118 2.143 ;
        RECT  494.1 0 494.118 0.038 ;
    END
  END lo[262]
  PIN lo[263]
    DIRECTION OUTPUT ;
    USE SIGNAL ;
    PORT
      LAYER M5 ;
        RECT  495.888 0.016 495.912 0.131 ;
        RECT  495.888 0 495.912 0.084 ;
    END
  END lo[263]
  PIN lo[264]
    DIRECTION OUTPUT ;
    USE SIGNAL ;
    PORT
      LAYER M3 ;
        RECT  497.7 0.012 497.718 2.371 ;
        RECT  497.7 0 497.718 0.038 ;
    END
  END lo[264]
  PIN lo[265]
    DIRECTION OUTPUT ;
    USE SIGNAL ;
    PORT
      LAYER M5 ;
        RECT  499.488 0.016 499.512 0.131 ;
        RECT  499.488 0 499.512 0.084 ;
    END
  END lo[265]
  PIN lo[266]
    DIRECTION OUTPUT ;
    USE SIGNAL ;
    PORT
      LAYER M3 ;
        RECT  501.3 0.012 501.318 2.101 ;
        RECT  501.3 0 501.318 0.038 ;
    END
  END lo[266]
  PIN lo[267]
    DIRECTION OUTPUT ;
    USE SIGNAL ;
    PORT
      LAYER M5 ;
        RECT  503.088 0.016 503.112 0.131 ;
        RECT  503.088 0 503.112 0.084 ;
    END
  END lo[267]
  PIN lo[268]
    DIRECTION OUTPUT ;
    USE SIGNAL ;
    PORT
      LAYER M3 ;
        RECT  504.9 0.012 504.918 2.101 ;
        RECT  504.9 0 504.918 0.038 ;
    END
  END lo[268]
  PIN lo[269]
    DIRECTION OUTPUT ;
    USE SIGNAL ;
    PORT
      LAYER M5 ;
        RECT  506.688 0.016 506.712 1.187 ;
        RECT  506.688 0 506.712 0.084 ;
    END
  END lo[269]
  PIN lo[26]
    DIRECTION OUTPUT ;
    USE SIGNAL ;
    PORT
      LAYER M3 ;
        RECT  69.3 0.012 69.318 2.129 ;
        RECT  69.3 0 69.318 0.038 ;
    END
  END lo[26]
  PIN lo[270]
    DIRECTION OUTPUT ;
    USE SIGNAL ;
    PORT
      LAYER M3 ;
        RECT  508.5 0.012 508.518 2.219 ;
        RECT  508.5 0 508.518 0.038 ;
    END
  END lo[270]
  PIN lo[271]
    DIRECTION OUTPUT ;
    USE SIGNAL ;
    PORT
      LAYER M5 ;
        RECT  510.288 0.016 510.312 1.187 ;
        RECT  510.288 0 510.312 0.084 ;
    END
  END lo[271]
  PIN lo[272]
    DIRECTION OUTPUT ;
    USE SIGNAL ;
    PORT
      LAYER M3 ;
        RECT  512.1 0.012 512.118 2.101 ;
        RECT  512.1 0 512.118 0.038 ;
    END
  END lo[272]
  PIN lo[273]
    DIRECTION OUTPUT ;
    USE SIGNAL ;
    PORT
      LAYER M5 ;
        RECT  513.888 0.016 513.912 1.187 ;
        RECT  513.888 0 513.912 0.084 ;
    END
  END lo[273]
  PIN lo[274]
    DIRECTION OUTPUT ;
    USE SIGNAL ;
    PORT
      LAYER M3 ;
        RECT  515.7 0.012 515.718 2.143 ;
        RECT  515.7 0 515.718 0.038 ;
    END
  END lo[274]
  PIN lo[275]
    DIRECTION OUTPUT ;
    USE SIGNAL ;
    PORT
      LAYER M5 ;
        RECT  517.488 0.016 517.512 0.131 ;
        RECT  517.488 0 517.512 0.084 ;
    END
  END lo[275]
  PIN lo[27]
    DIRECTION OUTPUT ;
    USE SIGNAL ;
    PORT
      LAYER M5 ;
        RECT  71.088 0.016 71.112 1.763 ;
        RECT  71.088 0 71.112 0.084 ;
    END
  END lo[27]
  PIN lo[28]
    DIRECTION OUTPUT ;
    USE SIGNAL ;
    PORT
      LAYER M3 ;
        RECT  72.9 0.012 72.918 1.651 ;
        RECT  72.9 0 72.918 0.038 ;
    END
  END lo[28]
  PIN lo[29]
    DIRECTION OUTPUT ;
    USE SIGNAL ;
    PORT
      LAYER M5 ;
        RECT  74.688 0.016 74.712 1.187 ;
        RECT  74.688 0 74.712 0.084 ;
    END
  END lo[29]
  PIN lo[2]
    DIRECTION OUTPUT ;
    USE SIGNAL ;
    PORT
      LAYER M3 ;
        RECT  26.1 0.012 26.118 2.219 ;
        RECT  26.1 0 26.118 0.038 ;
    END
  END lo[2]
  PIN lo[30]
    DIRECTION OUTPUT ;
    USE SIGNAL ;
    PORT
      LAYER M3 ;
        RECT  76.5 0.012 76.518 2.129 ;
        RECT  76.5 0 76.518 0.038 ;
    END
  END lo[30]
  PIN lo[31]
    DIRECTION OUTPUT ;
    USE SIGNAL ;
    PORT
      LAYER M5 ;
        RECT  78.288 0.016 78.312 1.187 ;
        RECT  78.288 0 78.312 0.084 ;
    END
  END lo[31]
  PIN lo[32]
    DIRECTION OUTPUT ;
    USE SIGNAL ;
    PORT
      LAYER M3 ;
        RECT  80.1 0.012 80.118 1.525 ;
        RECT  80.1 0 80.118 0.038 ;
    END
  END lo[32]
  PIN lo[33]
    DIRECTION OUTPUT ;
    USE SIGNAL ;
    PORT
      LAYER M5 ;
        RECT  81.888 0.016 81.912 1.763 ;
        RECT  81.888 0 81.912 0.084 ;
    END
  END lo[33]
  PIN lo[34]
    DIRECTION OUTPUT ;
    USE SIGNAL ;
    PORT
      LAYER M3 ;
        RECT  83.7 0.012 83.718 1.723 ;
        RECT  83.7 0 83.718 0.038 ;
    END
  END lo[34]
  PIN lo[35]
    DIRECTION OUTPUT ;
    USE SIGNAL ;
    PORT
      LAYER M5 ;
        RECT  85.488 0.016 85.512 0.131 ;
        RECT  85.488 0 85.512 0.084 ;
    END
  END lo[35]
  PIN lo[36]
    DIRECTION OUTPUT ;
    USE SIGNAL ;
    PORT
      LAYER M3 ;
        RECT  87.3 0.012 87.318 2.101 ;
        RECT  87.3 0 87.318 0.038 ;
    END
  END lo[36]
  PIN lo[37]
    DIRECTION OUTPUT ;
    USE SIGNAL ;
    PORT
      LAYER M5 ;
        RECT  89.088 0.016 89.112 2.137 ;
        RECT  89.088 0 89.112 0.084 ;
    END
  END lo[37]
  PIN lo[38]
    DIRECTION OUTPUT ;
    USE SIGNAL ;
    PORT
      LAYER M3 ;
        RECT  90.9 0.012 90.918 1.723 ;
        RECT  90.9 0 90.918 0.038 ;
    END
  END lo[38]
  PIN lo[39]
    DIRECTION OUTPUT ;
    USE SIGNAL ;
    PORT
      LAYER M5 ;
        RECT  92.688 0.016 92.712 0.131 ;
        RECT  92.688 0 92.712 0.084 ;
    END
  END lo[39]
  PIN lo[3]
    DIRECTION OUTPUT ;
    USE SIGNAL ;
    PORT
      LAYER M5 ;
        RECT  27.888 0.016 27.912 1.187 ;
        RECT  27.888 0 27.912 0.084 ;
    END
  END lo[3]
  PIN lo[40]
    DIRECTION OUTPUT ;
    USE SIGNAL ;
    PORT
      LAYER M3 ;
        RECT  94.5 0.012 94.518 1.111 ;
        RECT  94.5 0 94.518 0.038 ;
    END
  END lo[40]
  PIN lo[41]
    DIRECTION OUTPUT ;
    USE SIGNAL ;
    PORT
      LAYER M5 ;
        RECT  96.288 0.016 96.312 1.187 ;
        RECT  96.288 0 96.312 0.084 ;
    END
  END lo[41]
  PIN lo[42]
    DIRECTION OUTPUT ;
    USE SIGNAL ;
    PORT
      LAYER M3 ;
        RECT  98.1 0.012 98.118 2.831 ;
        RECT  98.1 0 98.118 0.038 ;
    END
  END lo[42]
  PIN lo[43]
    DIRECTION OUTPUT ;
    USE SIGNAL ;
    PORT
      LAYER M5 ;
        RECT  99.888 0.016 99.912 0.131 ;
        RECT  99.888 0 99.912 0.084 ;
    END
  END lo[43]
  PIN lo[44]
    DIRECTION OUTPUT ;
    USE SIGNAL ;
    PORT
      LAYER M3 ;
        RECT  101.7 0.012 101.718 2.399 ;
        RECT  101.7 0 101.718 0.038 ;
    END
  END lo[44]
  PIN lo[45]
    DIRECTION OUTPUT ;
    USE SIGNAL ;
    PORT
      LAYER M5 ;
        RECT  103.488 0.016 103.512 1.187 ;
        RECT  103.488 0 103.512 0.084 ;
    END
  END lo[45]
  PIN lo[46]
    DIRECTION OUTPUT ;
    USE SIGNAL ;
    PORT
      LAYER M3 ;
        RECT  105.3 0.012 105.318 1.876 ;
        RECT  105.3 0 105.318 0.038 ;
    END
  END lo[46]
  PIN lo[47]
    DIRECTION OUTPUT ;
    USE SIGNAL ;
    PORT
      LAYER M5 ;
        RECT  107.088 0.016 107.112 1.187 ;
        RECT  107.088 0 107.112 0.084 ;
    END
  END lo[47]
  PIN lo[48]
    DIRECTION OUTPUT ;
    USE SIGNAL ;
    PORT
      LAYER M3 ;
        RECT  108.9 0.012 108.918 2.669 ;
        RECT  108.9 0 108.918 0.038 ;
    END
  END lo[48]
  PIN lo[49]
    DIRECTION OUTPUT ;
    USE SIGNAL ;
    PORT
      LAYER M5 ;
        RECT  110.688 0.016 110.712 1.187 ;
        RECT  110.688 0 110.712 0.084 ;
    END
  END lo[49]
  PIN lo[4]
    DIRECTION OUTPUT ;
    USE SIGNAL ;
    PORT
      LAYER M3 ;
        RECT  29.7 0.012 29.718 1.723 ;
        RECT  29.7 0 29.718 0.038 ;
    END
  END lo[4]
  PIN lo[50]
    DIRECTION OUTPUT ;
    USE SIGNAL ;
    PORT
      LAYER M3 ;
        RECT  112.5 0.012 112.518 2.101 ;
        RECT  112.5 0 112.518 0.038 ;
    END
  END lo[50]
  PIN lo[51]
    DIRECTION OUTPUT ;
    USE SIGNAL ;
    PORT
      LAYER M5 ;
        RECT  114.288 0.016 114.312 1.187 ;
        RECT  114.288 0 114.312 0.084 ;
    END
  END lo[51]
  PIN lo[52]
    DIRECTION OUTPUT ;
    USE SIGNAL ;
    PORT
      LAYER M3 ;
        RECT  116.1 0.012 116.118 0.949 ;
        RECT  116.1 0 116.118 0.038 ;
    END
  END lo[52]
  PIN lo[53]
    DIRECTION OUTPUT ;
    USE SIGNAL ;
    PORT
      LAYER M5 ;
        RECT  117.888 0.016 117.912 1.187 ;
        RECT  117.888 0 117.912 0.084 ;
    END
  END lo[53]
  PIN lo[54]
    DIRECTION OUTPUT ;
    USE SIGNAL ;
    PORT
      LAYER M3 ;
        RECT  119.7 0.012 119.718 2.299 ;
        RECT  119.7 0 119.718 0.038 ;
    END
  END lo[54]
  PIN lo[55]
    DIRECTION OUTPUT ;
    USE SIGNAL ;
    PORT
      LAYER M5 ;
        RECT  121.488 0.016 121.512 0.131 ;
        RECT  121.488 0 121.512 0.084 ;
    END
  END lo[55]
  PIN lo[56]
    DIRECTION OUTPUT ;
    USE SIGNAL ;
    PORT
      LAYER M3 ;
        RECT  123.3 0.012 123.318 2.291 ;
        RECT  123.3 0 123.318 0.038 ;
    END
  END lo[56]
  PIN lo[57]
    DIRECTION OUTPUT ;
    USE SIGNAL ;
    PORT
      LAYER M5 ;
        RECT  125.088 0.016 125.112 0.131 ;
        RECT  125.088 0 125.112 0.084 ;
    END
  END lo[57]
  PIN lo[58]
    DIRECTION OUTPUT ;
    USE SIGNAL ;
    PORT
      LAYER M3 ;
        RECT  126.9 0.012 126.918 2.143 ;
        RECT  126.9 0 126.918 0.038 ;
    END
  END lo[58]
  PIN lo[59]
    DIRECTION OUTPUT ;
    USE SIGNAL ;
    PORT
      LAYER M5 ;
        RECT  128.688 0.016 128.712 1.187 ;
        RECT  128.688 0 128.712 0.084 ;
    END
  END lo[59]
  PIN lo[5]
    DIRECTION OUTPUT ;
    USE SIGNAL ;
    PORT
      LAYER M5 ;
        RECT  31.488 0.016 31.512 0.611 ;
        RECT  31.488 0 31.512 0.084 ;
    END
  END lo[5]
  PIN lo[60]
    DIRECTION OUTPUT ;
    USE SIGNAL ;
    PORT
      LAYER M3 ;
        RECT  130.5 0.012 130.518 1.723 ;
        RECT  130.5 0 130.518 0.038 ;
    END
  END lo[60]
  PIN lo[61]
    DIRECTION OUTPUT ;
    USE SIGNAL ;
    PORT
      LAYER M5 ;
        RECT  132.288 0.016 132.312 1.187 ;
        RECT  132.288 0 132.312 0.084 ;
    END
  END lo[61]
  PIN lo[62]
    DIRECTION OUTPUT ;
    USE SIGNAL ;
    PORT
      LAYER M3 ;
        RECT  134.1 0.012 134.118 2.101 ;
        RECT  134.1 0 134.118 0.038 ;
    END
  END lo[62]
  PIN lo[63]
    DIRECTION OUTPUT ;
    USE SIGNAL ;
    PORT
      LAYER M5 ;
        RECT  135.888 0.016 135.912 1.763 ;
        RECT  135.888 0 135.912 0.084 ;
    END
  END lo[63]
  PIN lo[64]
    DIRECTION OUTPUT ;
    USE SIGNAL ;
    PORT
      LAYER M3 ;
        RECT  137.7 0.012 137.718 2.029 ;
        RECT  137.7 0 137.718 0.038 ;
    END
  END lo[64]
  PIN lo[65]
    DIRECTION OUTPUT ;
    USE SIGNAL ;
    PORT
      LAYER M5 ;
        RECT  139.488 0.016 139.512 1.763 ;
        RECT  139.488 0 139.512 0.084 ;
    END
  END lo[65]
  PIN lo[66]
    DIRECTION OUTPUT ;
    USE SIGNAL ;
    PORT
      LAYER M3 ;
        RECT  141.3 0.012 141.318 1.723 ;
        RECT  141.3 0 141.318 0.038 ;
    END
  END lo[66]
  PIN lo[67]
    DIRECTION OUTPUT ;
    USE SIGNAL ;
    PORT
      LAYER M5 ;
        RECT  143.088 0.016 143.112 1.187 ;
        RECT  143.088 0 143.112 0.084 ;
    END
  END lo[67]
  PIN lo[68]
    DIRECTION OUTPUT ;
    USE SIGNAL ;
    PORT
      LAYER M3 ;
        RECT  144.9 0.012 144.918 1.066 ;
        RECT  144.9 0 144.918 0.038 ;
    END
  END lo[68]
  PIN lo[69]
    DIRECTION OUTPUT ;
    USE SIGNAL ;
    PORT
      LAYER M5 ;
        RECT  146.688 0.016 146.712 1.187 ;
        RECT  146.688 0 146.712 0.084 ;
    END
  END lo[69]
  PIN lo[6]
    DIRECTION OUTPUT ;
    USE SIGNAL ;
    PORT
      LAYER M3 ;
        RECT  33.3 0.012 33.318 2.731 ;
        RECT  33.3 0 33.318 0.038 ;
    END
  END lo[6]
  PIN lo[70]
    DIRECTION OUTPUT ;
    USE SIGNAL ;
    PORT
      LAYER M3 ;
        RECT  148.5 0.012 148.518 2.143 ;
        RECT  148.5 0 148.518 0.038 ;
    END
  END lo[70]
  PIN lo[71]
    DIRECTION OUTPUT ;
    USE SIGNAL ;
    PORT
      LAYER M5 ;
        RECT  150.288 0.016 150.312 0.131 ;
        RECT  150.288 0 150.312 0.084 ;
    END
  END lo[71]
  PIN lo[72]
    DIRECTION OUTPUT ;
    USE SIGNAL ;
    PORT
      LAYER M3 ;
        RECT  152.1 0.012 152.118 2.101 ;
        RECT  152.1 0 152.118 0.038 ;
    END
  END lo[72]
  PIN lo[73]
    DIRECTION OUTPUT ;
    USE SIGNAL ;
    PORT
      LAYER M5 ;
        RECT  153.888 0.016 153.912 0.131 ;
        RECT  153.888 0 153.912 0.084 ;
    END
  END lo[73]
  PIN lo[74]
    DIRECTION OUTPUT ;
    USE SIGNAL ;
    PORT
      LAYER M3 ;
        RECT  155.7 0.012 155.718 2.299 ;
        RECT  155.7 0 155.718 0.038 ;
    END
  END lo[74]
  PIN lo[75]
    DIRECTION OUTPUT ;
    USE SIGNAL ;
    PORT
      LAYER M5 ;
        RECT  157.488 0.016 157.512 0.131 ;
        RECT  157.488 0 157.512 0.084 ;
    END
  END lo[75]
  PIN lo[76]
    DIRECTION OUTPUT ;
    USE SIGNAL ;
    PORT
      LAYER M3 ;
        RECT  159.3 0.012 159.318 2.101 ;
        RECT  159.3 0 159.318 0.038 ;
    END
  END lo[76]
  PIN lo[77]
    DIRECTION OUTPUT ;
    USE SIGNAL ;
    PORT
      LAYER M5 ;
        RECT  161.088 0.016 161.112 0.131 ;
        RECT  161.088 0 161.112 0.084 ;
    END
  END lo[77]
  PIN lo[78]
    DIRECTION OUTPUT ;
    USE SIGNAL ;
    PORT
      LAYER M3 ;
        RECT  162.9 0.012 162.918 2.101 ;
        RECT  162.9 0 162.918 0.038 ;
    END
  END lo[78]
  PIN lo[79]
    DIRECTION OUTPUT ;
    USE SIGNAL ;
    PORT
      LAYER M5 ;
        RECT  164.688 0.016 164.712 0.131 ;
        RECT  164.688 0 164.712 0.084 ;
    END
  END lo[79]
  PIN lo[7]
    DIRECTION OUTPUT ;
    USE SIGNAL ;
    PORT
      LAYER M5 ;
        RECT  35.088 0.016 35.112 1.187 ;
        RECT  35.088 0 35.112 0.084 ;
    END
  END lo[7]
  PIN lo[80]
    DIRECTION OUTPUT ;
    USE SIGNAL ;
    PORT
      LAYER M3 ;
        RECT  166.5 0.012 166.518 1.723 ;
        RECT  166.5 0 166.518 0.038 ;
    END
  END lo[80]
  PIN lo[81]
    DIRECTION OUTPUT ;
    USE SIGNAL ;
    PORT
      LAYER M5 ;
        RECT  168.288 0.016 168.312 0.131 ;
        RECT  168.288 0 168.312 0.084 ;
    END
  END lo[81]
  PIN lo[82]
    DIRECTION OUTPUT ;
    USE SIGNAL ;
    PORT
      LAYER M3 ;
        RECT  170.1 0.012 170.118 2.143 ;
        RECT  170.1 0 170.118 0.038 ;
    END
  END lo[82]
  PIN lo[83]
    DIRECTION OUTPUT ;
    USE SIGNAL ;
    PORT
      LAYER M5 ;
        RECT  171.888 0.016 171.912 1.763 ;
        RECT  171.888 0 171.912 0.084 ;
    END
  END lo[83]
  PIN lo[84]
    DIRECTION OUTPUT ;
    USE SIGNAL ;
    PORT
      LAYER M3 ;
        RECT  173.7 0.012 173.718 2.533 ;
        RECT  173.7 0 173.718 0.038 ;
    END
  END lo[84]
  PIN lo[85]
    DIRECTION OUTPUT ;
    USE SIGNAL ;
    PORT
      LAYER M5 ;
        RECT  175.488 0.016 175.512 2.005 ;
        RECT  175.488 0 175.512 0.084 ;
    END
  END lo[85]
  PIN lo[86]
    DIRECTION OUTPUT ;
    USE SIGNAL ;
    PORT
      LAYER M3 ;
        RECT  177.3 0.012 177.318 2.129 ;
        RECT  177.3 0 177.318 0.038 ;
    END
  END lo[86]
  PIN lo[87]
    DIRECTION OUTPUT ;
    USE SIGNAL ;
    PORT
      LAYER M5 ;
        RECT  179.088 0.016 179.112 0.611 ;
        RECT  179.088 0 179.112 0.084 ;
    END
  END lo[87]
  PIN lo[88]
    DIRECTION OUTPUT ;
    USE SIGNAL ;
    PORT
      LAYER M3 ;
        RECT  180.9 0.012 180.918 2.143 ;
        RECT  180.9 0 180.918 0.038 ;
    END
  END lo[88]
  PIN lo[89]
    DIRECTION OUTPUT ;
    USE SIGNAL ;
    PORT
      LAYER M5 ;
        RECT  182.688 0.016 182.712 0.611 ;
        RECT  182.688 0 182.712 0.084 ;
    END
  END lo[89]
  PIN lo[8]
    DIRECTION OUTPUT ;
    USE SIGNAL ;
    PORT
      LAYER M3 ;
        RECT  36.9 0.012 36.918 2.129 ;
        RECT  36.9 0 36.918 0.038 ;
    END
  END lo[8]
  PIN lo[90]
    DIRECTION OUTPUT ;
    USE SIGNAL ;
    PORT
      LAYER M3 ;
        RECT  184.5 0.012 184.518 2.219 ;
        RECT  184.5 0 184.518 0.038 ;
    END
  END lo[90]
  PIN lo[91]
    DIRECTION OUTPUT ;
    USE SIGNAL ;
    PORT
      LAYER M5 ;
        RECT  186.288 0.016 186.312 1.187 ;
        RECT  186.288 0 186.312 0.084 ;
    END
  END lo[91]
  PIN lo[92]
    DIRECTION OUTPUT ;
    USE SIGNAL ;
    PORT
      LAYER M3 ;
        RECT  188.1 0.012 188.118 2.129 ;
        RECT  188.1 0 188.118 0.038 ;
    END
  END lo[92]
  PIN lo[93]
    DIRECTION OUTPUT ;
    USE SIGNAL ;
    PORT
      LAYER M5 ;
        RECT  189.888 0.016 189.912 1.187 ;
        RECT  189.888 0 189.912 0.084 ;
    END
  END lo[93]
  PIN lo[94]
    DIRECTION OUTPUT ;
    USE SIGNAL ;
    PORT
      LAYER M3 ;
        RECT  191.7 0.012 191.718 2.143 ;
        RECT  191.7 0 191.718 0.038 ;
    END
  END lo[94]
  PIN lo[95]
    DIRECTION OUTPUT ;
    USE SIGNAL ;
    PORT
      LAYER M5 ;
        RECT  193.488 0.016 193.512 1.187 ;
        RECT  193.488 0 193.512 0.084 ;
    END
  END lo[95]
  PIN lo[96]
    DIRECTION OUTPUT ;
    USE SIGNAL ;
    PORT
      LAYER M3 ;
        RECT  195.3 0.012 195.318 1.957 ;
        RECT  195.3 0 195.318 0.038 ;
    END
  END lo[96]
  PIN lo[97]
    DIRECTION OUTPUT ;
    USE SIGNAL ;
    PORT
      LAYER M5 ;
        RECT  197.088 0.016 197.112 2.137 ;
        RECT  197.088 0 197.112 0.084 ;
    END
  END lo[97]
  PIN lo[98]
    DIRECTION OUTPUT ;
    USE SIGNAL ;
    PORT
      LAYER M3 ;
        RECT  198.9 0.012 198.918 2.101 ;
        RECT  198.9 0 198.918 0.038 ;
    END
  END lo[98]
  PIN lo[99]
    DIRECTION OUTPUT ;
    USE SIGNAL ;
    PORT
      LAYER M5 ;
        RECT  200.688 0.016 200.712 0.131 ;
        RECT  200.688 0 200.712 0.084 ;
    END
  END lo[99]
  PIN lo[9]
    DIRECTION OUTPUT ;
    USE SIGNAL ;
    PORT
      LAYER M5 ;
        RECT  38.688 0.016 38.712 1.187 ;
        RECT  38.688 0 38.712 0.084 ;
    END
  END lo[9]
  PIN rst
    DIRECTION INPUT ;
    USE SIGNAL ;
    PORT
      LAYER M4 ;
        RECT  0.06 420.672 2.408 420.696 ;
        RECT  0 420.672 0.084 420.696 ;
    END
  END rst
  PIN st[0]
    DIRECTION OUTPUT ;
    USE SIGNAL ;
    PORT
      LAYER M3 ;
        RECT  531.54 0.012 531.558 2.143 ;
        RECT  531.54 0 531.558 0.038 ;
    END
  END st[0]
  PIN st[10]
    DIRECTION OUTPUT ;
    USE SIGNAL ;
    PORT
      LAYER M3 ;
        RECT  578.808 0.012 578.826 2.219 ;
        RECT  578.808 0 578.826 0.038 ;
    END
  END st[10]
  PIN st[11]
    DIRECTION OUTPUT ;
    USE SIGNAL ;
    PORT
      LAYER M5 ;
        RECT  583.536 0.016 583.56 1.763 ;
        RECT  583.536 0 583.56 0.084 ;
    END
  END st[11]
  PIN st[12]
    DIRECTION OUTPUT ;
    USE SIGNAL ;
    PORT
      LAYER M3 ;
        RECT  588.24 0.012 588.258 2.219 ;
        RECT  588.24 0 588.258 0.038 ;
    END
  END st[12]
  PIN st[13]
    DIRECTION OUTPUT ;
    USE SIGNAL ;
    PORT
      LAYER M5 ;
        RECT  592.992 0.016 593.016 1.187 ;
        RECT  592.992 0 593.016 0.084 ;
    END
  END st[13]
  PIN st[14]
    DIRECTION OUTPUT ;
    USE SIGNAL ;
    PORT
      LAYER M3 ;
        RECT  597.708 0.012 597.726 2.219 ;
        RECT  597.708 0 597.726 0.038 ;
    END
  END st[14]
  PIN st[15]
    DIRECTION OUTPUT ;
    USE SIGNAL ;
    PORT
      LAYER M5 ;
        RECT  602.448 0.016 602.472 1.187 ;
        RECT  602.448 0 602.472 0.084 ;
    END
  END st[15]
  PIN st[1]
    DIRECTION OUTPUT ;
    USE SIGNAL ;
    PORT
      LAYER M5 ;
        RECT  536.256 0.016 536.28 1.187 ;
        RECT  536.256 0 536.28 0.084 ;
    END
  END st[1]
  PIN st[2]
    DIRECTION OUTPUT ;
    USE SIGNAL ;
    PORT
      LAYER M3 ;
        RECT  541.008 0.012 541.026 2.219 ;
        RECT  541.008 0 541.026 0.038 ;
    END
  END st[2]
  PIN st[3]
    DIRECTION OUTPUT ;
    USE SIGNAL ;
    PORT
      LAYER M5 ;
        RECT  545.712 0.016 545.736 0.131 ;
        RECT  545.712 0 545.736 0.084 ;
    END
  END st[3]
  PIN st[4]
    DIRECTION OUTPUT ;
    USE SIGNAL ;
    PORT
      LAYER M3 ;
        RECT  550.44 0.012 550.458 2.219 ;
        RECT  550.44 0 550.458 0.038 ;
    END
  END st[4]
  PIN st[5]
    DIRECTION OUTPUT ;
    USE SIGNAL ;
    PORT
      LAYER M5 ;
        RECT  555.168 0.016 555.192 0.131 ;
        RECT  555.168 0 555.192 0.084 ;
    END
  END st[5]
  PIN st[6]
    DIRECTION OUTPUT ;
    USE SIGNAL ;
    PORT
      LAYER M3 ;
        RECT  559.908 0.012 559.926 2.219 ;
        RECT  559.908 0 559.926 0.038 ;
    END
  END st[6]
  PIN st[7]
    DIRECTION OUTPUT ;
    USE SIGNAL ;
    PORT
      LAYER M5 ;
        RECT  564.624 0.016 564.648 0.131 ;
        RECT  564.624 0 564.648 0.084 ;
    END
  END st[7]
  PIN st[8]
    DIRECTION OUTPUT ;
    USE SIGNAL ;
    PORT
      LAYER M3 ;
        RECT  569.34 0.012 569.358 2.143 ;
        RECT  569.34 0 569.358 0.038 ;
    END
  END st[8]
  PIN st[9]
    DIRECTION OUTPUT ;
    USE SIGNAL ;
    PORT
      LAYER M5 ;
        RECT  574.08 0.016 574.104 1.187 ;
        RECT  574.08 0 574.104 0.084 ;
    END
  END st[9]
  PIN vi[0]
    DIRECTION INPUT ;
    USE SIGNAL ;
    PORT
      LAYER M3 ;
        RECT  22.104 559.301 22.122 561.581 ;
        RECT  22.104 561.562 22.122 561.6 ;
    END
  END vi[0]
  PIN vi[100]
    DIRECTION INPUT ;
    USE SIGNAL ;
    PORT
      LAYER M3 ;
        RECT  123.84 559.345 123.858 561.581 ;
        RECT  123.84 561.562 123.858 561.6 ;
    END
  END vi[100]
  PIN vi[101]
    DIRECTION INPUT ;
    USE SIGNAL ;
    PORT
      LAYER M5 ;
        RECT  124.848 559.381 124.872 561.552 ;
        RECT  124.848 561.516 124.872 561.6 ;
    END
  END vi[101]
  PIN vi[102]
    DIRECTION INPUT ;
    USE SIGNAL ;
    PORT
      LAYER M3 ;
        RECT  125.892 559.457 125.91 561.581 ;
        RECT  125.892 561.562 125.91 561.6 ;
    END
  END vi[102]
  PIN vi[103]
    DIRECTION INPUT ;
    USE SIGNAL ;
    PORT
      LAYER M5 ;
        RECT  126.912 559.717 126.936 561.552 ;
        RECT  126.912 561.516 126.936 561.6 ;
    END
  END vi[103]
  PIN vi[104]
    DIRECTION INPUT ;
    USE SIGNAL ;
    PORT
      LAYER M3 ;
        RECT  127.908 559.345 127.926 561.581 ;
        RECT  127.908 561.562 127.926 561.6 ;
    END
  END vi[104]
  PIN vi[105]
    DIRECTION INPUT ;
    USE SIGNAL ;
    PORT
      LAYER M5 ;
        RECT  128.928 559.717 128.952 561.552 ;
        RECT  128.928 561.516 128.952 561.6 ;
    END
  END vi[105]
  PIN vi[106]
    DIRECTION INPUT ;
    USE SIGNAL ;
    PORT
      LAYER M3 ;
        RECT  129.96 559.345 129.978 561.581 ;
        RECT  129.96 561.562 129.978 561.6 ;
    END
  END vi[106]
  PIN vi[107]
    DIRECTION INPUT ;
    USE SIGNAL ;
    PORT
      LAYER M5 ;
        RECT  130.944 559.717 130.968 561.552 ;
        RECT  130.944 561.516 130.968 561.6 ;
    END
  END vi[107]
  PIN vi[108]
    DIRECTION INPUT ;
    USE SIGNAL ;
    PORT
      LAYER M3 ;
        RECT  131.976 559.724 131.994 561.581 ;
        RECT  131.976 561.562 131.994 561.6 ;
    END
  END vi[108]
  PIN vi[109]
    DIRECTION INPUT ;
    USE SIGNAL ;
    PORT
      LAYER M5 ;
        RECT  133.008 559.717 133.032 561.552 ;
        RECT  133.008 561.516 133.032 561.6 ;
    END
  END vi[109]
  PIN vi[10]
    DIRECTION INPUT ;
    USE SIGNAL ;
    PORT
      LAYER M3 ;
        RECT  32.292 561.562 32.31 561.6 ;
    END
  END vi[10]
  PIN vi[110]
    DIRECTION INPUT ;
    USE SIGNAL ;
    PORT
      LAYER M3 ;
        RECT  134.028 559.229 134.046 561.581 ;
        RECT  134.028 561.562 134.046 561.6 ;
    END
  END vi[110]
  PIN vi[111]
    DIRECTION INPUT ;
    USE SIGNAL ;
    PORT
      LAYER M5 ;
        RECT  135.024 561.445 135.048 561.552 ;
        RECT  135.024 561.516 135.048 561.6 ;
    END
  END vi[111]
  PIN vi[112]
    DIRECTION INPUT ;
    USE SIGNAL ;
    PORT
      LAYER M3 ;
        RECT  136.044 559.229 136.062 561.581 ;
        RECT  136.044 561.562 136.062 561.6 ;
    END
  END vi[112]
  PIN vi[113]
    DIRECTION INPUT ;
    USE SIGNAL ;
    PORT
      LAYER M5 ;
        RECT  137.04 559.463 137.064 561.552 ;
        RECT  137.04 561.516 137.064 561.6 ;
    END
  END vi[113]
  PIN vi[114]
    DIRECTION INPUT ;
    USE SIGNAL ;
    PORT
      LAYER M3 ;
        RECT  138.096 559.457 138.114 561.581 ;
        RECT  138.096 561.562 138.114 561.6 ;
    END
  END vi[114]
  PIN vi[115]
    DIRECTION INPUT ;
    USE SIGNAL ;
    PORT
      LAYER M5 ;
        RECT  139.104 559.381 139.128 561.552 ;
        RECT  139.104 561.516 139.128 561.6 ;
    END
  END vi[115]
  PIN vi[116]
    DIRECTION INPUT ;
    USE SIGNAL ;
    PORT
      LAYER M3 ;
        RECT  140.112 559.345 140.13 561.581 ;
        RECT  140.112 561.562 140.13 561.6 ;
    END
  END vi[116]
  PIN vi[117]
    DIRECTION INPUT ;
    USE SIGNAL ;
    PORT
      LAYER M5 ;
        RECT  141.12 559.717 141.144 561.552 ;
        RECT  141.12 561.516 141.144 561.6 ;
    END
  END vi[117]
  PIN vi[118]
    DIRECTION INPUT ;
    USE SIGNAL ;
    PORT
      LAYER M3 ;
        RECT  142.164 559.457 142.182 561.581 ;
        RECT  142.164 561.562 142.182 561.6 ;
    END
  END vi[118]
  PIN vi[119]
    DIRECTION INPUT ;
    USE SIGNAL ;
    PORT
      LAYER M5 ;
        RECT  143.184 559.717 143.208 561.552 ;
        RECT  143.184 561.516 143.208 561.6 ;
    END
  END vi[119]
  PIN vi[11]
    DIRECTION INPUT ;
    USE SIGNAL ;
    PORT
      LAYER M5 ;
        RECT  33.312 561.516 33.336 561.6 ;
    END
  END vi[11]
  PIN vi[120]
    DIRECTION INPUT ;
    USE SIGNAL ;
    PORT
      LAYER M3 ;
        RECT  144.18 559.229 144.198 561.581 ;
        RECT  144.18 561.562 144.198 561.6 ;
    END
  END vi[120]
  PIN vi[121]
    DIRECTION INPUT ;
    USE SIGNAL ;
    PORT
      LAYER M5 ;
        RECT  145.2 559.717 145.224 561.552 ;
        RECT  145.2 561.516 145.224 561.6 ;
    END
  END vi[121]
  PIN vi[122]
    DIRECTION INPUT ;
    USE SIGNAL ;
    PORT
      LAYER M3 ;
        RECT  146.232 559.345 146.25 561.581 ;
        RECT  146.232 561.562 146.25 561.6 ;
    END
  END vi[122]
  PIN vi[123]
    DIRECTION INPUT ;
    USE SIGNAL ;
    PORT
      LAYER M5 ;
        RECT  147.216 559.717 147.24 561.552 ;
        RECT  147.216 561.516 147.24 561.6 ;
    END
  END vi[123]
  PIN vi[124]
    DIRECTION INPUT ;
    USE SIGNAL ;
    PORT
      LAYER M3 ;
        RECT  148.248 559.724 148.266 561.581 ;
        RECT  148.248 561.562 148.266 561.6 ;
    END
  END vi[124]
  PIN vi[125]
    DIRECTION INPUT ;
    USE SIGNAL ;
    PORT
      LAYER M5 ;
        RECT  149.28 561.445 149.304 561.552 ;
        RECT  149.28 561.516 149.304 561.6 ;
    END
  END vi[125]
  PIN vi[126]
    DIRECTION INPUT ;
    USE SIGNAL ;
    PORT
      LAYER M3 ;
        RECT  150.3 559.345 150.318 561.581 ;
        RECT  150.3 561.562 150.318 561.6 ;
    END
  END vi[126]
  PIN vi[127]
    DIRECTION INPUT ;
    USE SIGNAL ;
    PORT
      LAYER M5 ;
        RECT  151.296 559.717 151.32 561.552 ;
        RECT  151.296 561.516 151.32 561.6 ;
    END
  END vi[127]
  PIN vi[128]
    DIRECTION INPUT ;
    USE SIGNAL ;
    PORT
      LAYER M3 ;
        RECT  152.316 559.229 152.334 561.581 ;
        RECT  152.316 561.562 152.334 561.6 ;
    END
  END vi[128]
  PIN vi[129]
    DIRECTION INPUT ;
    USE SIGNAL ;
    PORT
      LAYER M5 ;
        RECT  153.36 559.717 153.384 561.552 ;
        RECT  153.36 561.516 153.384 561.6 ;
    END
  END vi[129]
  PIN vi[12]
    DIRECTION INPUT ;
    USE SIGNAL ;
    PORT
      LAYER M3 ;
        RECT  34.308 561.562 34.326 561.6 ;
    END
  END vi[12]
  PIN vi[130]
    DIRECTION INPUT ;
    USE SIGNAL ;
    PORT
      LAYER M3 ;
        RECT  154.368 559.457 154.386 561.581 ;
        RECT  154.368 561.562 154.386 561.6 ;
    END
  END vi[130]
  PIN vi[131]
    DIRECTION INPUT ;
    USE SIGNAL ;
    PORT
      LAYER M5 ;
        RECT  155.376 559.717 155.4 561.552 ;
        RECT  155.376 561.516 155.4 561.6 ;
    END
  END vi[131]
  PIN vi[132]
    DIRECTION INPUT ;
    USE SIGNAL ;
    PORT
      LAYER M3 ;
        RECT  156.384 559.345 156.402 561.581 ;
        RECT  156.384 561.562 156.402 561.6 ;
    END
  END vi[132]
  PIN vi[133]
    DIRECTION INPUT ;
    USE SIGNAL ;
    PORT
      LAYER M5 ;
        RECT  157.392 559.717 157.416 561.552 ;
        RECT  157.392 561.516 157.416 561.6 ;
    END
  END vi[133]
  PIN vi[134]
    DIRECTION INPUT ;
    USE SIGNAL ;
    PORT
      LAYER M3 ;
        RECT  158.436 561.299 158.454 561.581 ;
        RECT  158.436 561.562 158.454 561.6 ;
    END
  END vi[134]
  PIN vi[135]
    DIRECTION INPUT ;
    USE SIGNAL ;
    PORT
      LAYER M5 ;
        RECT  159.456 559.717 159.48 561.552 ;
        RECT  159.456 561.516 159.48 561.6 ;
    END
  END vi[135]
  PIN vi[136]
    DIRECTION INPUT ;
    USE SIGNAL ;
    PORT
      LAYER M3 ;
        RECT  160.452 559.345 160.47 561.581 ;
        RECT  160.452 561.562 160.47 561.6 ;
    END
  END vi[136]
  PIN vi[137]
    DIRECTION INPUT ;
    USE SIGNAL ;
    PORT
      LAYER M5 ;
        RECT  161.472 559.717 161.496 561.552 ;
        RECT  161.472 561.516 161.496 561.6 ;
    END
  END vi[137]
  PIN vi[138]
    DIRECTION INPUT ;
    USE SIGNAL ;
    PORT
      LAYER M3 ;
        RECT  162.504 559.229 162.522 561.581 ;
        RECT  162.504 561.562 162.522 561.6 ;
    END
  END vi[138]
  PIN vi[139]
    DIRECTION INPUT ;
    USE SIGNAL ;
    PORT
      LAYER M5 ;
        RECT  163.536 561.445 163.56 561.552 ;
        RECT  163.536 561.516 163.56 561.6 ;
    END
  END vi[139]
  PIN vi[13]
    DIRECTION INPUT ;
    USE SIGNAL ;
    PORT
      LAYER M5 ;
        RECT  35.328 561.516 35.352 561.6 ;
    END
  END vi[13]
  PIN vi[140]
    DIRECTION INPUT ;
    USE SIGNAL ;
    PORT
      LAYER M3 ;
        RECT  164.52 559.724 164.538 561.581 ;
        RECT  164.52 561.562 164.538 561.6 ;
    END
  END vi[140]
  PIN vi[141]
    DIRECTION INPUT ;
    USE SIGNAL ;
    PORT
      LAYER M5 ;
        RECT  165.552 559.717 165.576 561.552 ;
        RECT  165.552 561.516 165.576 561.6 ;
    END
  END vi[141]
  PIN vi[142]
    DIRECTION INPUT ;
    USE SIGNAL ;
    PORT
      LAYER M3 ;
        RECT  166.572 559.229 166.59 561.581 ;
        RECT  166.572 561.562 166.59 561.6 ;
    END
  END vi[142]
  PIN vi[143]
    DIRECTION INPUT ;
    USE SIGNAL ;
    PORT
      LAYER M5 ;
        RECT  167.568 560.869 167.592 561.552 ;
        RECT  167.568 561.516 167.592 561.6 ;
    END
  END vi[143]
  PIN vi[144]
    DIRECTION INPUT ;
    USE SIGNAL ;
    PORT
      LAYER M3 ;
        RECT  168.588 559.345 168.606 561.581 ;
        RECT  168.588 561.562 168.606 561.6 ;
    END
  END vi[144]
  PIN vi[145]
    DIRECTION INPUT ;
    USE SIGNAL ;
    PORT
      LAYER M5 ;
        RECT  169.632 559.463 169.656 561.552 ;
        RECT  169.632 561.516 169.656 561.6 ;
    END
  END vi[145]
  PIN vi[146]
    DIRECTION INPUT ;
    USE SIGNAL ;
    PORT
      LAYER M3 ;
        RECT  170.64 559.229 170.658 561.581 ;
        RECT  170.64 561.562 170.658 561.6 ;
    END
  END vi[146]
  PIN vi[147]
    DIRECTION INPUT ;
    USE SIGNAL ;
    PORT
      LAYER M5 ;
        RECT  171.648 559.717 171.672 561.552 ;
        RECT  171.648 561.516 171.672 561.6 ;
    END
  END vi[147]
  PIN vi[148]
    DIRECTION INPUT ;
    USE SIGNAL ;
    PORT
      LAYER M3 ;
        RECT  172.692 559.345 172.71 561.581 ;
        RECT  172.692 561.562 172.71 561.6 ;
    END
  END vi[148]
  PIN vi[149]
    DIRECTION INPUT ;
    USE SIGNAL ;
    PORT
      LAYER M5 ;
        RECT  173.712 561.445 173.736 561.552 ;
        RECT  173.712 561.516 173.736 561.6 ;
    END
  END vi[149]
  PIN vi[14]
    DIRECTION INPUT ;
    USE SIGNAL ;
    PORT
      LAYER M3 ;
        RECT  36.36 561.562 36.378 561.6 ;
    END
  END vi[14]
  PIN vi[150]
    DIRECTION INPUT ;
    USE SIGNAL ;
    PORT
      LAYER M3 ;
        RECT  174.708 561.569 174.726 561.581 ;
        RECT  174.708 561.541 175.014 561.569 ;
        RECT  174.708 561.562 174.726 561.6 ;
    END
  END vi[150]
  PIN vi[151]
    DIRECTION INPUT ;
    USE SIGNAL ;
    PORT
      LAYER M5 ;
        RECT  175.728 559.717 175.752 561.552 ;
        RECT  175.728 561.516 175.752 561.6 ;
    END
  END vi[151]
  PIN vi[152]
    DIRECTION INPUT ;
    USE SIGNAL ;
    PORT
      LAYER M3 ;
        RECT  176.76 559.345 176.778 561.581 ;
        RECT  176.76 561.562 176.778 561.6 ;
    END
  END vi[152]
  PIN vi[153]
    DIRECTION INPUT ;
    USE SIGNAL ;
    PORT
      LAYER M5 ;
        RECT  177.744 560.245 177.768 561.552 ;
        RECT  177.744 561.516 177.768 561.6 ;
    END
  END vi[153]
  PIN vi[154]
    DIRECTION INPUT ;
    USE SIGNAL ;
    PORT
      LAYER M3 ;
        RECT  178.776 559.337 178.794 561.581 ;
        RECT  178.776 561.562 178.794 561.6 ;
    END
  END vi[154]
  PIN vi[155]
    DIRECTION INPUT ;
    USE SIGNAL ;
    PORT
      LAYER M5 ;
        RECT  179.808 559.717 179.832 561.552 ;
        RECT  179.808 561.516 179.832 561.6 ;
    END
  END vi[155]
  PIN vi[156]
    DIRECTION INPUT ;
    USE SIGNAL ;
    PORT
      LAYER M3 ;
        RECT  180.828 559.457 180.846 561.581 ;
        RECT  180.828 561.562 180.846 561.6 ;
    END
  END vi[156]
  PIN vi[157]
    DIRECTION INPUT ;
    USE SIGNAL ;
    PORT
      LAYER M5 ;
        RECT  181.824 559.717 181.848 561.552 ;
        RECT  181.824 561.516 181.848 561.6 ;
    END
  END vi[157]
  PIN vi[158]
    DIRECTION INPUT ;
    USE SIGNAL ;
    PORT
      LAYER M3 ;
        RECT  182.844 559.409 182.862 561.581 ;
        RECT  182.844 561.562 182.862 561.6 ;
    END
  END vi[158]
  PIN vi[159]
    DIRECTION INPUT ;
    USE SIGNAL ;
    PORT
      LAYER M5 ;
        RECT  183.84 560.245 183.864 561.552 ;
        RECT  183.84 561.516 183.864 561.6 ;
    END
  END vi[159]
  PIN vi[15]
    DIRECTION INPUT ;
    USE SIGNAL ;
    PORT
      LAYER M5 ;
        RECT  37.344 561.516 37.368 561.6 ;
    END
  END vi[15]
  PIN vi[160]
    DIRECTION INPUT ;
    USE SIGNAL ;
    PORT
      LAYER M3 ;
        RECT  184.896 560.285 184.914 561.581 ;
        RECT  184.896 561.562 184.914 561.6 ;
    END
  END vi[160]
  PIN vi[161]
    DIRECTION INPUT ;
    USE SIGNAL ;
    PORT
      LAYER M5 ;
        RECT  185.904 559.717 185.928 561.552 ;
        RECT  185.904 561.516 185.928 561.6 ;
    END
  END vi[161]
  PIN vi[162]
    DIRECTION INPUT ;
    USE SIGNAL ;
    PORT
      LAYER M3 ;
        RECT  186.912 559.265 186.93 561.581 ;
        RECT  186.912 561.562 186.93 561.6 ;
    END
  END vi[162]
  PIN vi[163]
    DIRECTION INPUT ;
    USE SIGNAL ;
    PORT
      LAYER M5 ;
        RECT  187.92 560.245 187.944 561.552 ;
        RECT  187.92 561.516 187.944 561.6 ;
    END
  END vi[163]
  PIN vi[164]
    DIRECTION INPUT ;
    USE SIGNAL ;
    PORT
      LAYER M3 ;
        RECT  188.964 561.499 188.982 561.581 ;
        RECT  188.964 561.562 188.982 561.6 ;
    END
  END vi[164]
  PIN vi[165]
    DIRECTION INPUT ;
    USE SIGNAL ;
    PORT
      LAYER M5 ;
        RECT  189.984 559.717 190.008 561.552 ;
        RECT  189.984 561.516 190.008 561.6 ;
    END
  END vi[165]
  PIN vi[166]
    DIRECTION INPUT ;
    USE SIGNAL ;
    PORT
      LAYER M3 ;
        RECT  190.98 559.457 190.998 561.581 ;
        RECT  190.98 561.562 190.998 561.6 ;
    END
  END vi[166]
  PIN vi[167]
    DIRECTION INPUT ;
    USE SIGNAL ;
    PORT
      LAYER M5 ;
        RECT  192 561.445 192.024 561.552 ;
        RECT  192 561.516 192.024 561.6 ;
    END
  END vi[167]
  PIN vi[168]
    DIRECTION INPUT ;
    USE SIGNAL ;
    PORT
      LAYER M3 ;
        RECT  193.032 561.485 193.05 561.581 ;
        RECT  193.032 561.562 193.05 561.6 ;
    END
  END vi[168]
  PIN vi[169]
    DIRECTION INPUT ;
    USE SIGNAL ;
    PORT
      LAYER M5 ;
        RECT  194.016 559.717 194.04 561.552 ;
        RECT  194.016 561.516 194.04 561.6 ;
    END
  END vi[169]
  PIN vi[16]
    DIRECTION INPUT ;
    USE SIGNAL ;
    PORT
      LAYER M3 ;
        RECT  38.376 559.409 38.394 561.581 ;
        RECT  38.376 561.562 38.394 561.6 ;
    END
  END vi[16]
  PIN vi[170]
    DIRECTION INPUT ;
    USE SIGNAL ;
    PORT
      LAYER M3 ;
        RECT  195.048 559.229 195.066 561.581 ;
        RECT  195.048 561.562 195.066 561.6 ;
    END
  END vi[170]
  PIN vi[171]
    DIRECTION INPUT ;
    USE SIGNAL ;
    PORT
      LAYER M5 ;
        RECT  196.08 559.717 196.104 561.552 ;
        RECT  196.08 561.516 196.104 561.6 ;
    END
  END vi[171]
  PIN vi[172]
    DIRECTION INPUT ;
    USE SIGNAL ;
    PORT
      LAYER M3 ;
        RECT  197.1 559.757 197.118 561.581 ;
        RECT  197.1 561.562 197.118 561.6 ;
    END
  END vi[172]
  PIN vi[173]
    DIRECTION INPUT ;
    USE SIGNAL ;
    PORT
      LAYER M5 ;
        RECT  198.096 561.445 198.12 561.552 ;
        RECT  198.096 561.516 198.12 561.6 ;
    END
  END vi[173]
  PIN vi[174]
    DIRECTION INPUT ;
    USE SIGNAL ;
    PORT
      LAYER M3 ;
        RECT  199.116 561.485 199.134 561.581 ;
        RECT  199.116 561.562 199.134 561.6 ;
    END
  END vi[174]
  PIN vi[175]
    DIRECTION INPUT ;
    USE SIGNAL ;
    PORT
      LAYER M5 ;
        RECT  200.16 559.717 200.184 561.552 ;
        RECT  200.16 561.516 200.184 561.6 ;
    END
  END vi[175]
  PIN vi[176]
    DIRECTION INPUT ;
    USE SIGNAL ;
    PORT
      LAYER M3 ;
        RECT  201.168 559.229 201.186 561.581 ;
        RECT  201.168 561.562 201.186 561.6 ;
    END
  END vi[176]
  PIN vi[177]
    DIRECTION INPUT ;
    USE SIGNAL ;
    PORT
      LAYER M5 ;
        RECT  202.176 559.717 202.2 561.552 ;
        RECT  202.176 561.516 202.2 561.6 ;
    END
  END vi[177]
  PIN vi[178]
    DIRECTION INPUT ;
    USE SIGNAL ;
    PORT
      LAYER M3 ;
        RECT  203.184 559.345 203.202 561.581 ;
        RECT  203.184 561.562 203.202 561.6 ;
    END
  END vi[178]
  PIN vi[179]
    DIRECTION INPUT ;
    USE SIGNAL ;
    PORT
      LAYER M5 ;
        RECT  204.192 559.717 204.216 561.552 ;
        RECT  204.192 561.516 204.216 561.6 ;
    END
  END vi[179]
  PIN vi[17]
    DIRECTION INPUT ;
    USE SIGNAL ;
    PORT
      LAYER M5 ;
        RECT  39.408 559.717 39.432 561.552 ;
        RECT  39.408 561.516 39.432 561.6 ;
    END
  END vi[17]
  PIN vi[180]
    DIRECTION INPUT ;
    USE SIGNAL ;
    PORT
      LAYER M3 ;
        RECT  205.236 559.345 205.254 561.581 ;
        RECT  205.236 561.562 205.254 561.6 ;
    END
  END vi[180]
  PIN vi[181]
    DIRECTION INPUT ;
    USE SIGNAL ;
    PORT
      LAYER M5 ;
        RECT  206.256 561.445 206.28 561.552 ;
        RECT  206.256 561.516 206.28 561.6 ;
    END
  END vi[181]
  PIN vi[182]
    DIRECTION INPUT ;
    USE SIGNAL ;
    PORT
      LAYER M3 ;
        RECT  207.252 561.499 207.27 561.581 ;
        RECT  207.252 561.562 207.27 561.6 ;
    END
  END vi[182]
  PIN vi[183]
    DIRECTION INPUT ;
    USE SIGNAL ;
    PORT
      LAYER M5 ;
        RECT  208.272 559.717 208.296 561.552 ;
        RECT  208.272 561.516 208.296 561.6 ;
    END
  END vi[183]
  PIN vi[184]
    DIRECTION INPUT ;
    USE SIGNAL ;
    PORT
      LAYER M3 ;
        RECT  209.304 559.337 209.322 561.581 ;
        RECT  209.304 561.562 209.322 561.6 ;
    END
  END vi[184]
  PIN vi[185]
    DIRECTION INPUT ;
    USE SIGNAL ;
    PORT
      LAYER M5 ;
        RECT  210.336 559.717 210.36 561.552 ;
        RECT  210.336 561.516 210.36 561.6 ;
    END
  END vi[185]
  PIN vi[186]
    DIRECTION INPUT ;
    USE SIGNAL ;
    PORT
      LAYER M3 ;
        RECT  211.32 561.499 211.338 561.581 ;
        RECT  211.32 561.562 211.338 561.6 ;
    END
  END vi[186]
  PIN vi[187]
    DIRECTION INPUT ;
    USE SIGNAL ;
    PORT
      LAYER M5 ;
        RECT  212.352 559.717 212.376 561.552 ;
        RECT  212.352 561.516 212.376 561.6 ;
    END
  END vi[187]
  PIN vi[188]
    DIRECTION INPUT ;
    USE SIGNAL ;
    PORT
      LAYER M3 ;
        RECT  213.372 559.757 213.39 561.581 ;
        RECT  213.372 561.562 213.39 561.6 ;
    END
  END vi[188]
  PIN vi[189]
    DIRECTION INPUT ;
    USE SIGNAL ;
    PORT
      LAYER M5 ;
        RECT  214.368 559.717 214.392 561.552 ;
        RECT  214.368 561.516 214.392 561.6 ;
    END
  END vi[189]
  PIN vi[18]
    DIRECTION INPUT ;
    USE SIGNAL ;
    PORT
      LAYER M3 ;
        RECT  40.428 559.457 40.446 561.581 ;
        RECT  40.428 561.562 40.446 561.6 ;
    END
  END vi[18]
  PIN vi[190]
    DIRECTION INPUT ;
    USE SIGNAL ;
    PORT
      LAYER M3 ;
        RECT  215.388 559.345 215.406 561.581 ;
        RECT  215.388 561.562 215.406 561.6 ;
    END
  END vi[190]
  PIN vi[191]
    DIRECTION INPUT ;
    USE SIGNAL ;
    PORT
      LAYER M5 ;
        RECT  216.432 559.717 216.456 561.552 ;
        RECT  216.432 561.516 216.456 561.6 ;
    END
  END vi[191]
  PIN vi[192]
    DIRECTION INPUT ;
    USE SIGNAL ;
    PORT
      LAYER M3 ;
        RECT  217.44 561.499 217.458 561.581 ;
        RECT  217.44 561.562 217.458 561.6 ;
    END
  END vi[192]
  PIN vi[193]
    DIRECTION INPUT ;
    USE SIGNAL ;
    PORT
      LAYER M5 ;
        RECT  218.448 559.463 218.472 561.552 ;
        RECT  218.448 561.516 218.472 561.6 ;
    END
  END vi[193]
  PIN vi[194]
    DIRECTION INPUT ;
    USE SIGNAL ;
    PORT
      LAYER M3 ;
        RECT  219.492 559.345 219.51 561.581 ;
        RECT  219.492 561.562 219.51 561.6 ;
    END
  END vi[194]
  PIN vi[195]
    DIRECTION INPUT ;
    USE SIGNAL ;
    PORT
      LAYER M5 ;
        RECT  220.512 559.717 220.536 561.552 ;
        RECT  220.512 561.516 220.536 561.6 ;
    END
  END vi[195]
  PIN vi[196]
    DIRECTION INPUT ;
    USE SIGNAL ;
    PORT
      LAYER M3 ;
        RECT  221.508 559.345 221.526 561.581 ;
        RECT  221.508 561.562 221.526 561.6 ;
    END
  END vi[196]
  PIN vi[197]
    DIRECTION INPUT ;
    USE SIGNAL ;
    PORT
      LAYER M5 ;
        RECT  222.528 559.717 222.552 561.552 ;
        RECT  222.528 561.516 222.552 561.6 ;
    END
  END vi[197]
  PIN vi[198]
    DIRECTION INPUT ;
    USE SIGNAL ;
    PORT
      LAYER M3 ;
        RECT  223.56 559.757 223.578 561.581 ;
        RECT  223.56 561.562 223.578 561.6 ;
    END
  END vi[198]
  PIN vi[199]
    DIRECTION INPUT ;
    USE SIGNAL ;
    PORT
      LAYER M5 ;
        RECT  224.544 559.717 224.568 561.552 ;
        RECT  224.544 561.516 224.568 561.6 ;
    END
  END vi[199]
  PIN vi[19]
    DIRECTION INPUT ;
    USE SIGNAL ;
    PORT
      LAYER M5 ;
        RECT  41.424 559.717 41.448 561.552 ;
        RECT  41.424 561.516 41.448 561.6 ;
    END
  END vi[19]
  PIN vi[1]
    DIRECTION INPUT ;
    USE SIGNAL ;
    PORT
      LAYER M5 ;
        RECT  23.136 559.717 23.16 561.552 ;
        RECT  23.136 561.516 23.16 561.6 ;
    END
  END vi[1]
  PIN vi[200]
    DIRECTION INPUT ;
    USE SIGNAL ;
    PORT
      LAYER M3 ;
        RECT  225.576 559.345 225.594 561.581 ;
        RECT  225.576 561.562 225.594 561.6 ;
    END
  END vi[200]
  PIN vi[201]
    DIRECTION INPUT ;
    USE SIGNAL ;
    PORT
      LAYER M5 ;
        RECT  226.608 559.717 226.632 561.552 ;
        RECT  226.608 561.516 226.632 561.6 ;
    END
  END vi[201]
  PIN vi[202]
    DIRECTION INPUT ;
    USE SIGNAL ;
    PORT
      LAYER M3 ;
        RECT  227.628 559.757 227.646 561.581 ;
        RECT  227.628 561.562 227.646 561.6 ;
    END
  END vi[202]
  PIN vi[203]
    DIRECTION INPUT ;
    USE SIGNAL ;
    PORT
      LAYER M5 ;
        RECT  228.624 559.717 228.648 561.552 ;
        RECT  228.624 561.516 228.648 561.6 ;
    END
  END vi[203]
  PIN vi[204]
    DIRECTION INPUT ;
    USE SIGNAL ;
    PORT
      LAYER M3 ;
        RECT  229.644 559.757 229.662 561.581 ;
        RECT  229.644 561.562 229.662 561.6 ;
    END
  END vi[204]
  PIN vi[205]
    DIRECTION INPUT ;
    USE SIGNAL ;
    PORT
      LAYER M5 ;
        RECT  230.64 559.717 230.664 561.552 ;
        RECT  230.64 561.516 230.664 561.6 ;
    END
  END vi[205]
  PIN vi[206]
    DIRECTION INPUT ;
    USE SIGNAL ;
    PORT
      LAYER M3 ;
        RECT  231.696 559.345 231.714 561.581 ;
        RECT  231.696 561.562 231.714 561.6 ;
    END
  END vi[206]
  PIN vi[207]
    DIRECTION INPUT ;
    USE SIGNAL ;
    PORT
      LAYER M5 ;
        RECT  232.704 559.717 232.728 561.552 ;
        RECT  232.704 561.516 232.728 561.6 ;
    END
  END vi[207]
  PIN vi[208]
    DIRECTION INPUT ;
    USE SIGNAL ;
    PORT
      LAYER M3 ;
        RECT  233.712 559.345 233.73 561.581 ;
        RECT  233.712 561.562 233.73 561.6 ;
    END
  END vi[208]
  PIN vi[209]
    DIRECTION INPUT ;
    USE SIGNAL ;
    PORT
      LAYER M5 ;
        RECT  234.72 559.463 234.744 561.552 ;
        RECT  234.72 561.516 234.744 561.6 ;
    END
  END vi[209]
  PIN vi[20]
    DIRECTION INPUT ;
    USE SIGNAL ;
    PORT
      LAYER M3 ;
        RECT  42.444 559.345 42.462 561.581 ;
        RECT  42.444 561.562 42.462 561.6 ;
    END
  END vi[20]
  PIN vi[210]
    DIRECTION INPUT ;
    USE SIGNAL ;
    PORT
      LAYER M3 ;
        RECT  235.764 561.499 235.782 561.581 ;
        RECT  235.764 561.562 235.782 561.6 ;
    END
  END vi[210]
  PIN vi[211]
    DIRECTION INPUT ;
    USE SIGNAL ;
    PORT
      LAYER M5 ;
        RECT  236.784 559.333 236.808 561.552 ;
        RECT  236.784 561.516 236.808 561.6 ;
    END
  END vi[211]
  PIN vi[212]
    DIRECTION INPUT ;
    USE SIGNAL ;
    PORT
      LAYER M3 ;
        RECT  237.78 559.409 237.798 561.581 ;
        RECT  237.78 561.562 237.798 561.6 ;
    END
  END vi[212]
  PIN vi[213]
    DIRECTION INPUT ;
    USE SIGNAL ;
    PORT
      LAYER M5 ;
        RECT  238.8 559.381 238.824 561.552 ;
        RECT  238.8 561.516 238.824 561.6 ;
    END
  END vi[213]
  PIN vi[214]
    DIRECTION INPUT ;
    USE SIGNAL ;
    PORT
      LAYER M3 ;
        RECT  239.832 561.499 239.85 561.581 ;
        RECT  239.832 561.562 239.85 561.6 ;
    END
  END vi[214]
  PIN vi[215]
    DIRECTION INPUT ;
    USE SIGNAL ;
    PORT
      LAYER M5 ;
        RECT  240.816 561.539 240.84 561.552 ;
        RECT  239.856 559.525 240.84 561.539 ;
        RECT  240.816 561.516 240.84 561.6 ;
    END
  END vi[215]
  PIN vi[216]
    DIRECTION INPUT ;
    USE SIGNAL ;
    PORT
      LAYER M3 ;
        RECT  241.848 559.265 241.866 561.581 ;
        RECT  241.848 561.562 241.866 561.6 ;
    END
  END vi[216]
  PIN vi[217]
    DIRECTION INPUT ;
    USE SIGNAL ;
    PORT
      LAYER M5 ;
        RECT  242.88 559.717 242.904 561.552 ;
        RECT  242.88 561.516 242.904 561.6 ;
    END
  END vi[217]
  PIN vi[218]
    DIRECTION INPUT ;
    USE SIGNAL ;
    PORT
      LAYER M3 ;
        RECT  243.9 559.345 243.918 561.581 ;
        RECT  243.9 561.562 243.918 561.6 ;
    END
  END vi[218]
  PIN vi[219]
    DIRECTION INPUT ;
    USE SIGNAL ;
    PORT
      LAYER M5 ;
        RECT  244.896 559.463 244.92 561.552 ;
        RECT  244.896 561.516 244.92 561.6 ;
    END
  END vi[219]
  PIN vi[21]
    DIRECTION INPUT ;
    USE SIGNAL ;
    PORT
      LAYER M5 ;
        RECT  43.44 559.717 43.464 561.552 ;
        RECT  43.44 561.516 43.464 561.6 ;
    END
  END vi[21]
  PIN vi[220]
    DIRECTION INPUT ;
    USE SIGNAL ;
    PORT
      LAYER M3 ;
        RECT  245.916 559.457 245.934 561.581 ;
        RECT  245.916 561.562 245.934 561.6 ;
    END
  END vi[220]
  PIN vi[221]
    DIRECTION INPUT ;
    USE SIGNAL ;
    PORT
      LAYER M5 ;
        RECT  246.96 559.381 246.984 561.552 ;
        RECT  246.96 561.516 246.984 561.6 ;
    END
  END vi[221]
  PIN vi[222]
    DIRECTION INPUT ;
    USE SIGNAL ;
    PORT
      LAYER M3 ;
        RECT  247.968 559.229 247.986 561.581 ;
        RECT  247.968 561.562 247.986 561.6 ;
    END
  END vi[222]
  PIN vi[223]
    DIRECTION INPUT ;
    USE SIGNAL ;
    PORT
      LAYER M5 ;
        RECT  248.976 559.717 249 561.552 ;
        RECT  248.976 561.516 249 561.6 ;
    END
  END vi[223]
  PIN vi[224]
    DIRECTION INPUT ;
    USE SIGNAL ;
    PORT
      LAYER M3 ;
        RECT  249.984 559.345 250.002 561.581 ;
        RECT  249.984 561.562 250.002 561.6 ;
    END
  END vi[224]
  PIN vi[225]
    DIRECTION INPUT ;
    USE SIGNAL ;
    PORT
      LAYER M5 ;
        RECT  250.992 559.463 251.016 561.552 ;
        RECT  250.992 561.516 251.016 561.6 ;
    END
  END vi[225]
  PIN vi[226]
    DIRECTION INPUT ;
    USE SIGNAL ;
    PORT
      LAYER M3 ;
        RECT  252.036 559.345 252.054 561.581 ;
        RECT  252.036 561.562 252.054 561.6 ;
    END
  END vi[226]
  PIN vi[227]
    DIRECTION INPUT ;
    USE SIGNAL ;
    PORT
      LAYER M5 ;
        RECT  253.056 560.245 253.08 561.552 ;
        RECT  253.056 561.516 253.08 561.6 ;
    END
  END vi[227]
  PIN vi[228]
    DIRECTION INPUT ;
    USE SIGNAL ;
    PORT
      LAYER M3 ;
        RECT  254.052 559.229 254.07 561.581 ;
        RECT  254.052 561.562 254.07 561.6 ;
    END
  END vi[228]
  PIN vi[229]
    DIRECTION INPUT ;
    USE SIGNAL ;
    PORT
      LAYER M5 ;
        RECT  255.072 559.717 255.096 561.552 ;
        RECT  255.072 561.516 255.096 561.6 ;
    END
  END vi[229]
  PIN vi[22]
    DIRECTION INPUT ;
    USE SIGNAL ;
    PORT
      LAYER M3 ;
        RECT  44.496 559.409 44.514 561.581 ;
        RECT  44.496 561.562 44.514 561.6 ;
    END
  END vi[22]
  PIN vi[230]
    DIRECTION INPUT ;
    USE SIGNAL ;
    PORT
      LAYER M3 ;
        RECT  256.104 559.457 256.122 561.581 ;
        RECT  256.104 561.562 256.122 561.6 ;
    END
  END vi[230]
  PIN vi[231]
    DIRECTION INPUT ;
    USE SIGNAL ;
    PORT
      LAYER M5 ;
        RECT  257.136 559.717 257.16 561.552 ;
        RECT  257.136 561.516 257.16 561.6 ;
    END
  END vi[231]
  PIN vi[232]
    DIRECTION INPUT ;
    USE SIGNAL ;
    PORT
      LAYER M3 ;
        RECT  258.12 559.345 258.138 561.581 ;
        RECT  258.12 561.562 258.138 561.6 ;
    END
  END vi[232]
  PIN vi[233]
    DIRECTION INPUT ;
    USE SIGNAL ;
    PORT
      LAYER M5 ;
        RECT  259.152 559.717 259.176 561.552 ;
        RECT  259.152 561.516 259.176 561.6 ;
    END
  END vi[233]
  PIN vi[234]
    DIRECTION INPUT ;
    USE SIGNAL ;
    PORT
      LAYER M3 ;
        RECT  260.172 559.345 260.19 561.581 ;
        RECT  260.172 561.562 260.19 561.6 ;
    END
  END vi[234]
  PIN vi[235]
    DIRECTION INPUT ;
    USE SIGNAL ;
    PORT
      LAYER M5 ;
        RECT  261.168 559.717 261.192 561.552 ;
        RECT  261.168 561.516 261.192 561.6 ;
    END
  END vi[235]
  PIN vi[236]
    DIRECTION INPUT ;
    USE SIGNAL ;
    PORT
      LAYER M3 ;
        RECT  262.188 559.457 262.206 561.581 ;
        RECT  262.188 561.562 262.206 561.6 ;
    END
  END vi[236]
  PIN vi[237]
    DIRECTION INPUT ;
    USE SIGNAL ;
    PORT
      LAYER M5 ;
        RECT  263.232 559.717 263.256 561.552 ;
        RECT  263.232 561.516 263.256 561.6 ;
    END
  END vi[237]
  PIN vi[238]
    DIRECTION INPUT ;
    USE SIGNAL ;
    PORT
      LAYER M3 ;
        RECT  264.24 559.345 264.258 561.581 ;
        RECT  264.24 561.562 264.258 561.6 ;
    END
  END vi[238]
  PIN vi[239]
    DIRECTION INPUT ;
    USE SIGNAL ;
    PORT
      LAYER M5 ;
        RECT  265.248 559.717 265.272 561.552 ;
        RECT  265.248 561.516 265.272 561.6 ;
    END
  END vi[239]
  PIN vi[23]
    DIRECTION INPUT ;
    USE SIGNAL ;
    PORT
      LAYER M5 ;
        RECT  45.504 559.717 45.528 561.552 ;
        RECT  45.504 561.516 45.528 561.6 ;
    END
  END vi[23]
  PIN vi[240]
    DIRECTION INPUT ;
    USE SIGNAL ;
    PORT
      LAYER M3 ;
        RECT  266.292 559.457 266.31 561.581 ;
        RECT  266.292 561.562 266.31 561.6 ;
    END
  END vi[240]
  PIN vi[241]
    DIRECTION INPUT ;
    USE SIGNAL ;
    PORT
      LAYER M5 ;
        RECT  267.312 559.717 267.336 561.552 ;
        RECT  267.312 561.516 267.336 561.6 ;
    END
  END vi[241]
  PIN vi[242]
    DIRECTION INPUT ;
    USE SIGNAL ;
    PORT
      LAYER M3 ;
        RECT  268.308 559.409 268.326 561.581 ;
        RECT  268.308 561.562 268.326 561.6 ;
    END
  END vi[242]
  PIN vi[243]
    DIRECTION INPUT ;
    USE SIGNAL ;
    PORT
      LAYER M5 ;
        RECT  269.328 559.381 269.352 561.552 ;
        RECT  269.328 561.516 269.352 561.6 ;
    END
  END vi[243]
  PIN vi[244]
    DIRECTION INPUT ;
    USE SIGNAL ;
    PORT
      LAYER M3 ;
        RECT  270.36 559.345 270.378 561.581 ;
        RECT  270.36 561.562 270.378 561.6 ;
    END
  END vi[244]
  PIN vi[245]
    DIRECTION INPUT ;
    USE SIGNAL ;
    PORT
      LAYER M5 ;
        RECT  271.344 559.717 271.368 561.552 ;
        RECT  271.344 561.516 271.368 561.6 ;
    END
  END vi[245]
  PIN vi[246]
    DIRECTION INPUT ;
    USE SIGNAL ;
    PORT
      LAYER M3 ;
        RECT  272.376 559.457 272.394 561.581 ;
        RECT  272.376 561.562 272.394 561.6 ;
    END
  END vi[246]
  PIN vi[247]
    DIRECTION INPUT ;
    USE SIGNAL ;
    PORT
      LAYER M5 ;
        RECT  273.408 559.717 273.432 561.552 ;
        RECT  273.408 561.516 273.432 561.6 ;
    END
  END vi[247]
  PIN vi[248]
    DIRECTION INPUT ;
    USE SIGNAL ;
    PORT
      LAYER M3 ;
        RECT  274.428 559.757 274.446 561.581 ;
        RECT  274.428 561.562 274.446 561.6 ;
    END
  END vi[248]
  PIN vi[249]
    DIRECTION INPUT ;
    USE SIGNAL ;
    PORT
      LAYER M5 ;
        RECT  275.424 559.717 275.448 561.552 ;
        RECT  275.424 561.516 275.448 561.6 ;
    END
  END vi[249]
  PIN vi[24]
    DIRECTION INPUT ;
    USE SIGNAL ;
    PORT
      LAYER M3 ;
        RECT  46.512 559.345 46.53 561.581 ;
        RECT  46.512 561.562 46.53 561.6 ;
    END
  END vi[24]
  PIN vi[250]
    DIRECTION INPUT ;
    USE SIGNAL ;
    PORT
      LAYER M3 ;
        RECT  276.444 559.075 276.462 561.581 ;
        RECT  276.444 561.562 276.462 561.6 ;
    END
  END vi[250]
  PIN vi[251]
    DIRECTION INPUT ;
    USE SIGNAL ;
    PORT
      LAYER M5 ;
        RECT  277.44 559.717 277.464 561.552 ;
        RECT  277.44 561.516 277.464 561.6 ;
    END
  END vi[251]
  PIN vi[252]
    DIRECTION INPUT ;
    USE SIGNAL ;
    PORT
      LAYER M3 ;
        RECT  278.496 559.457 278.514 561.581 ;
        RECT  278.496 561.562 278.514 561.6 ;
    END
  END vi[252]
  PIN vi[253]
    DIRECTION INPUT ;
    USE SIGNAL ;
    PORT
      LAYER M5 ;
        RECT  279.504 560.245 279.528 561.552 ;
        RECT  279.504 561.516 279.528 561.6 ;
    END
  END vi[253]
  PIN vi[254]
    DIRECTION INPUT ;
    USE SIGNAL ;
    PORT
      LAYER M3 ;
        RECT  280.512 560.285 280.53 561.581 ;
        RECT  280.512 561.562 280.53 561.6 ;
    END
  END vi[254]
  PIN vi[255]
    DIRECTION INPUT ;
    USE SIGNAL ;
    PORT
      LAYER M5 ;
        RECT  281.52 558.565 281.544 561.552 ;
        RECT  281.52 561.516 281.544 561.6 ;
    END
  END vi[255]
  PIN vi[256]
    DIRECTION INPUT ;
    USE SIGNAL ;
    PORT
      LAYER M3 ;
        RECT  282.564 559.457 282.582 561.581 ;
        RECT  282.564 561.562 282.582 561.6 ;
    END
  END vi[256]
  PIN vi[257]
    DIRECTION INPUT ;
    USE SIGNAL ;
    PORT
      LAYER M5 ;
        RECT  283.584 559.717 283.608 561.552 ;
        RECT  283.584 561.516 283.608 561.6 ;
    END
  END vi[257]
  PIN vi[258]
    DIRECTION INPUT ;
    USE SIGNAL ;
    PORT
      LAYER M3 ;
        RECT  284.58 559.345 284.598 561.581 ;
        RECT  284.58 561.562 284.598 561.6 ;
    END
  END vi[258]
  PIN vi[259]
    DIRECTION INPUT ;
    USE SIGNAL ;
    PORT
      LAYER M5 ;
        RECT  285.6 559.717 285.624 561.552 ;
        RECT  285.6 561.516 285.624 561.6 ;
    END
  END vi[259]
  PIN vi[25]
    DIRECTION INPUT ;
    USE SIGNAL ;
    PORT
      LAYER M5 ;
        RECT  47.52 559.717 47.544 561.552 ;
        RECT  47.52 561.516 47.544 561.6 ;
    END
  END vi[25]
  PIN vi[260]
    DIRECTION INPUT ;
    USE SIGNAL ;
    PORT
      LAYER M3 ;
        RECT  286.632 559.345 286.65 561.581 ;
        RECT  286.632 561.562 286.65 561.6 ;
    END
  END vi[260]
  PIN vi[261]
    DIRECTION INPUT ;
    USE SIGNAL ;
    PORT
      LAYER M5 ;
        RECT  287.616 559.717 287.64 561.552 ;
        RECT  287.616 561.516 287.64 561.6 ;
    END
  END vi[261]
  PIN vi[262]
    DIRECTION INPUT ;
    USE SIGNAL ;
    PORT
      LAYER M3 ;
        RECT  288.648 559.724 288.666 561.581 ;
        RECT  288.648 561.562 288.666 561.6 ;
    END
  END vi[262]
  PIN vi[263]
    DIRECTION INPUT ;
    USE SIGNAL ;
    PORT
      LAYER M5 ;
        RECT  289.68 559.463 289.704 561.552 ;
        RECT  289.68 561.516 289.704 561.6 ;
    END
  END vi[263]
  PIN vi[264]
    DIRECTION INPUT ;
    USE SIGNAL ;
    PORT
      LAYER M3 ;
        RECT  290.7 559.345 290.718 561.581 ;
        RECT  290.7 561.562 290.718 561.6 ;
    END
  END vi[264]
  PIN vi[265]
    DIRECTION INPUT ;
    USE SIGNAL ;
    PORT
      LAYER M5 ;
        RECT  291.696 560.245 291.72 561.552 ;
        RECT  291.696 561.516 291.72 561.6 ;
    END
  END vi[265]
  PIN vi[266]
    DIRECTION INPUT ;
    USE SIGNAL ;
    PORT
      LAYER M3 ;
        RECT  292.716 560.285 292.734 561.581 ;
        RECT  292.716 561.562 292.734 561.6 ;
    END
  END vi[266]
  PIN vi[267]
    DIRECTION INPUT ;
    USE SIGNAL ;
    PORT
      LAYER M5 ;
        RECT  293.76 559.717 293.784 561.552 ;
        RECT  293.76 561.516 293.784 561.6 ;
    END
  END vi[267]
  PIN vi[268]
    DIRECTION INPUT ;
    USE SIGNAL ;
    PORT
      LAYER M3 ;
        RECT  294.768 559.457 294.786 561.581 ;
        RECT  294.768 561.562 294.786 561.6 ;
    END
  END vi[268]
  PIN vi[269]
    DIRECTION INPUT ;
    USE SIGNAL ;
    PORT
      LAYER M5 ;
        RECT  295.776 560.245 295.8 561.552 ;
        RECT  295.776 561.516 295.8 561.6 ;
    END
  END vi[269]
  PIN vi[26]
    DIRECTION INPUT ;
    USE SIGNAL ;
    PORT
      LAYER M3 ;
        RECT  48.564 559.229 48.582 561.581 ;
        RECT  48.564 561.562 48.582 561.6 ;
    END
  END vi[26]
  PIN vi[270]
    DIRECTION INPUT ;
    USE SIGNAL ;
    PORT
      LAYER M3 ;
        RECT  296.784 559.345 296.802 561.581 ;
        RECT  296.784 561.562 296.802 561.6 ;
    END
  END vi[270]
  PIN vi[271]
    DIRECTION INPUT ;
    USE SIGNAL ;
    PORT
      LAYER M5 ;
        RECT  297.792 559.717 297.816 561.552 ;
        RECT  297.792 561.516 297.816 561.6 ;
    END
  END vi[271]
  PIN vi[272]
    DIRECTION INPUT ;
    USE SIGNAL ;
    PORT
      LAYER M3 ;
        RECT  298.836 559.457 298.854 561.581 ;
        RECT  298.836 561.562 298.854 561.6 ;
    END
  END vi[272]
  PIN vi[273]
    DIRECTION INPUT ;
    USE SIGNAL ;
    PORT
      LAYER M5 ;
        RECT  299.856 559.717 299.88 561.552 ;
        RECT  299.856 561.516 299.88 561.6 ;
    END
  END vi[273]
  PIN vi[274]
    DIRECTION INPUT ;
    USE SIGNAL ;
    PORT
      LAYER M3 ;
        RECT  300.852 559.075 300.87 561.581 ;
        RECT  300.852 561.562 300.87 561.6 ;
    END
  END vi[274]
  PIN vi[275]
    DIRECTION INPUT ;
    USE SIGNAL ;
    PORT
      LAYER M5 ;
        RECT  301.872 558.565 301.896 561.552 ;
        RECT  301.872 561.516 301.896 561.6 ;
    END
  END vi[275]
  PIN vi[27]
    DIRECTION INPUT ;
    USE SIGNAL ;
    PORT
      LAYER M5 ;
        RECT  49.584 559.717 49.608 561.552 ;
        RECT  49.584 561.516 49.608 561.6 ;
    END
  END vi[27]
  PIN vi[28]
    DIRECTION INPUT ;
    USE SIGNAL ;
    PORT
      LAYER M3 ;
        RECT  50.58 559.457 50.598 561.581 ;
        RECT  50.58 561.562 50.598 561.6 ;
    END
  END vi[28]
  PIN vi[29]
    DIRECTION INPUT ;
    USE SIGNAL ;
    PORT
      LAYER M5 ;
        RECT  51.6 559.717 51.624 561.552 ;
        RECT  51.6 561.516 51.624 561.6 ;
    END
  END vi[29]
  PIN vi[2]
    DIRECTION INPUT ;
    USE SIGNAL ;
    PORT
      LAYER M3 ;
        RECT  24.12 559.724 24.138 561.581 ;
        RECT  24.12 561.562 24.138 561.6 ;
    END
  END vi[2]
  PIN vi[30]
    DIRECTION INPUT ;
    USE SIGNAL ;
    PORT
      LAYER M3 ;
        RECT  52.632 559.345 52.65 561.581 ;
        RECT  52.632 561.562 52.65 561.6 ;
    END
  END vi[30]
  PIN vi[31]
    DIRECTION INPUT ;
    USE SIGNAL ;
    PORT
      LAYER M5 ;
        RECT  53.616 559.717 53.64 561.552 ;
        RECT  53.616 561.516 53.64 561.6 ;
    END
  END vi[31]
  PIN vi[32]
    DIRECTION INPUT ;
    USE SIGNAL ;
    PORT
      LAYER M3 ;
        RECT  54.648 561.499 54.666 561.581 ;
        RECT  54.648 561.562 54.666 561.6 ;
    END
  END vi[32]
  PIN vi[33]
    DIRECTION INPUT ;
    USE SIGNAL ;
    PORT
      LAYER M5 ;
        RECT  55.68 559.717 55.704 561.552 ;
        RECT  55.68 561.516 55.704 561.6 ;
    END
  END vi[33]
  PIN vi[34]
    DIRECTION INPUT ;
    USE SIGNAL ;
    PORT
      LAYER M3 ;
        RECT  56.7 559.457 56.718 561.581 ;
        RECT  56.7 561.562 56.718 561.6 ;
    END
  END vi[34]
  PIN vi[35]
    DIRECTION INPUT ;
    USE SIGNAL ;
    PORT
      LAYER M5 ;
        RECT  57.696 559.717 57.72 561.552 ;
        RECT  57.696 561.516 57.72 561.6 ;
    END
  END vi[35]
  PIN vi[36]
    DIRECTION INPUT ;
    USE SIGNAL ;
    PORT
      LAYER M3 ;
        RECT  58.716 559.229 58.734 561.581 ;
        RECT  58.716 561.562 58.734 561.6 ;
    END
  END vi[36]
  PIN vi[37]
    DIRECTION INPUT ;
    USE SIGNAL ;
    PORT
      LAYER M5 ;
        RECT  59.76 559.717 59.784 561.552 ;
        RECT  59.76 561.516 59.784 561.6 ;
    END
  END vi[37]
  PIN vi[38]
    DIRECTION INPUT ;
    USE SIGNAL ;
    PORT
      LAYER M3 ;
        RECT  60.768 559.345 60.786 561.581 ;
        RECT  60.768 561.562 60.786 561.6 ;
    END
  END vi[38]
  PIN vi[39]
    DIRECTION INPUT ;
    USE SIGNAL ;
    PORT
      LAYER M5 ;
        RECT  61.776 559.717 61.8 561.552 ;
        RECT  61.776 561.516 61.8 561.6 ;
    END
  END vi[39]
  PIN vi[3]
    DIRECTION INPUT ;
    USE SIGNAL ;
    PORT
      LAYER M5 ;
        RECT  25.152 559.449 25.176 561.552 ;
        RECT  25.152 561.516 25.176 561.6 ;
    END
  END vi[3]
  PIN vi[40]
    DIRECTION INPUT ;
    USE SIGNAL ;
    PORT
      LAYER M3 ;
        RECT  62.784 559.265 62.802 561.581 ;
        RECT  62.784 561.562 62.802 561.6 ;
    END
  END vi[40]
  PIN vi[41]
    DIRECTION INPUT ;
    USE SIGNAL ;
    PORT
      LAYER M5 ;
        RECT  63.792 559.717 63.816 561.552 ;
        RECT  63.792 561.516 63.816 561.6 ;
    END
  END vi[41]
  PIN vi[42]
    DIRECTION INPUT ;
    USE SIGNAL ;
    PORT
      LAYER M3 ;
        RECT  64.836 559.345 64.854 561.581 ;
        RECT  64.836 561.562 64.854 561.6 ;
    END
  END vi[42]
  PIN vi[43]
    DIRECTION INPUT ;
    USE SIGNAL ;
    PORT
      LAYER M5 ;
        RECT  65.856 559.717 65.88 561.552 ;
        RECT  65.856 561.516 65.88 561.6 ;
    END
  END vi[43]
  PIN vi[44]
    DIRECTION INPUT ;
    USE SIGNAL ;
    PORT
      LAYER M3 ;
        RECT  66.852 559.457 66.87 561.581 ;
        RECT  66.852 561.562 66.87 561.6 ;
    END
  END vi[44]
  PIN vi[45]
    DIRECTION INPUT ;
    USE SIGNAL ;
    PORT
      LAYER M5 ;
        RECT  67.872 559.717 67.896 561.552 ;
        RECT  67.872 561.516 67.896 561.6 ;
    END
  END vi[45]
  PIN vi[46]
    DIRECTION INPUT ;
    USE SIGNAL ;
    PORT
      LAYER M3 ;
        RECT  68.904 559.229 68.922 561.581 ;
        RECT  68.904 561.562 68.922 561.6 ;
    END
  END vi[46]
  PIN vi[47]
    DIRECTION INPUT ;
    USE SIGNAL ;
    PORT
      LAYER M5 ;
        RECT  69.936 559.717 69.96 561.552 ;
        RECT  69.936 561.516 69.96 561.6 ;
    END
  END vi[47]
  PIN vi[48]
    DIRECTION INPUT ;
    USE SIGNAL ;
    PORT
      LAYER M3 ;
        RECT  70.92 559.229 70.938 561.581 ;
        RECT  70.92 561.562 70.938 561.6 ;
    END
  END vi[48]
  PIN vi[49]
    DIRECTION INPUT ;
    USE SIGNAL ;
    PORT
      LAYER M5 ;
        RECT  71.952 559.717 71.976 561.552 ;
        RECT  71.952 561.516 71.976 561.6 ;
    END
  END vi[49]
  PIN vi[4]
    DIRECTION INPUT ;
    USE SIGNAL ;
    PORT
      LAYER M3 ;
        RECT  26.172 559.277 26.19 561.581 ;
        RECT  26.172 561.562 26.19 561.6 ;
    END
  END vi[4]
  PIN vi[50]
    DIRECTION INPUT ;
    USE SIGNAL ;
    PORT
      LAYER M3 ;
        RECT  72.972 559.457 72.99 561.581 ;
        RECT  72.972 561.562 72.99 561.6 ;
    END
  END vi[50]
  PIN vi[51]
    DIRECTION INPUT ;
    USE SIGNAL ;
    PORT
      LAYER M5 ;
        RECT  73.968 559.717 73.992 561.552 ;
        RECT  73.968 561.516 73.992 561.6 ;
    END
  END vi[51]
  PIN vi[52]
    DIRECTION INPUT ;
    USE SIGNAL ;
    PORT
      LAYER M3 ;
        RECT  74.988 559.345 75.006 561.581 ;
        RECT  74.988 561.562 75.006 561.6 ;
    END
  END vi[52]
  PIN vi[53]
    DIRECTION INPUT ;
    USE SIGNAL ;
    PORT
      LAYER M5 ;
        RECT  76.032 559.717 76.056 561.552 ;
        RECT  76.032 561.516 76.056 561.6 ;
    END
  END vi[53]
  PIN vi[54]
    DIRECTION INPUT ;
    USE SIGNAL ;
    PORT
      LAYER M3 ;
        RECT  77.04 559.345 77.058 561.581 ;
        RECT  77.04 561.562 77.058 561.6 ;
    END
  END vi[54]
  PIN vi[55]
    DIRECTION INPUT ;
    USE SIGNAL ;
    PORT
      LAYER M5 ;
        RECT  78.048 559.463 78.072 561.552 ;
        RECT  78.048 561.516 78.072 561.6 ;
    END
  END vi[55]
  PIN vi[56]
    DIRECTION INPUT ;
    USE SIGNAL ;
    PORT
      LAYER M3 ;
        RECT  79.092 559.345 79.11 561.581 ;
        RECT  79.092 561.562 79.11 561.6 ;
    END
  END vi[56]
  PIN vi[57]
    DIRECTION INPUT ;
    USE SIGNAL ;
    PORT
      LAYER M5 ;
        RECT  80.112 559.717 80.136 561.552 ;
        RECT  80.112 561.516 80.136 561.6 ;
    END
  END vi[57]
  PIN vi[58]
    DIRECTION INPUT ;
    USE SIGNAL ;
    PORT
      LAYER M3 ;
        RECT  81.108 559.229 81.126 561.581 ;
        RECT  81.108 561.562 81.126 561.6 ;
    END
  END vi[58]
  PIN vi[59]
    DIRECTION INPUT ;
    USE SIGNAL ;
    PORT
      LAYER M5 ;
        RECT  82.128 559.717 82.152 561.552 ;
        RECT  82.128 561.516 82.152 561.6 ;
    END
  END vi[59]
  PIN vi[5]
    DIRECTION INPUT ;
    USE SIGNAL ;
    PORT
      LAYER M5 ;
        RECT  27.168 528.517 27.192 561.552 ;
        RECT  27.168 561.516 27.192 561.6 ;
    END
  END vi[5]
  PIN vi[60]
    DIRECTION INPUT ;
    USE SIGNAL ;
    PORT
      LAYER M3 ;
        RECT  83.16 559.457 83.178 561.581 ;
        RECT  83.16 561.562 83.178 561.6 ;
    END
  END vi[60]
  PIN vi[61]
    DIRECTION INPUT ;
    USE SIGNAL ;
    PORT
      LAYER M5 ;
        RECT  84.144 559.717 84.168 561.552 ;
        RECT  84.144 561.516 84.168 561.6 ;
    END
  END vi[61]
  PIN vi[62]
    DIRECTION INPUT ;
    USE SIGNAL ;
    PORT
      LAYER M3 ;
        RECT  85.176 559.345 85.194 561.581 ;
        RECT  85.176 561.562 85.194 561.6 ;
    END
  END vi[62]
  PIN vi[63]
    DIRECTION INPUT ;
    USE SIGNAL ;
    PORT
      LAYER M5 ;
        RECT  86.208 559.717 86.232 561.552 ;
        RECT  86.208 561.516 86.232 561.6 ;
    END
  END vi[63]
  PIN vi[64]
    DIRECTION INPUT ;
    USE SIGNAL ;
    PORT
      LAYER M3 ;
        RECT  87.228 559.345 87.246 561.581 ;
        RECT  87.228 561.562 87.246 561.6 ;
    END
  END vi[64]
  PIN vi[65]
    DIRECTION INPUT ;
    USE SIGNAL ;
    PORT
      LAYER M5 ;
        RECT  88.224 559.717 88.248 561.552 ;
        RECT  88.224 561.516 88.248 561.6 ;
    END
  END vi[65]
  PIN vi[66]
    DIRECTION INPUT ;
    USE SIGNAL ;
    PORT
      LAYER M3 ;
        RECT  89.244 559.457 89.262 561.581 ;
        RECT  89.244 561.562 89.262 561.6 ;
    END
  END vi[66]
  PIN vi[67]
    DIRECTION INPUT ;
    USE SIGNAL ;
    PORT
      LAYER M5 ;
        RECT  90.24 559.717 90.264 561.552 ;
        RECT  90.24 561.516 90.264 561.6 ;
    END
  END vi[67]
  PIN vi[68]
    DIRECTION INPUT ;
    USE SIGNAL ;
    PORT
      LAYER M3 ;
        RECT  91.296 559.229 91.314 561.581 ;
        RECT  91.296 561.562 91.314 561.6 ;
    END
  END vi[68]
  PIN vi[69]
    DIRECTION INPUT ;
    USE SIGNAL ;
    PORT
      LAYER M5 ;
        RECT  92.304 561.445 92.328 561.552 ;
        RECT  92.304 561.516 92.328 561.6 ;
    END
  END vi[69]
  PIN vi[6]
    DIRECTION INPUT ;
    USE SIGNAL ;
    PORT
      LAYER M3 ;
        RECT  28.188 561.499 28.206 561.581 ;
        RECT  28.188 561.562 28.206 561.6 ;
    END
  END vi[6]
  PIN vi[70]
    DIRECTION INPUT ;
    USE SIGNAL ;
    PORT
      LAYER M3 ;
        RECT  93.312 559.229 93.33 561.581 ;
        RECT  93.312 561.562 93.33 561.6 ;
    END
  END vi[70]
  PIN vi[71]
    DIRECTION INPUT ;
    USE SIGNAL ;
    PORT
      LAYER M5 ;
        RECT  94.32 559.463 94.344 561.552 ;
        RECT  94.32 561.516 94.344 561.6 ;
    END
  END vi[71]
  PIN vi[72]
    DIRECTION INPUT ;
    USE SIGNAL ;
    PORT
      LAYER M3 ;
        RECT  95.364 559.229 95.382 561.581 ;
        RECT  95.364 561.562 95.382 561.6 ;
    END
  END vi[72]
  PIN vi[73]
    DIRECTION INPUT ;
    USE SIGNAL ;
    PORT
      LAYER M5 ;
        RECT  96.384 559.717 96.408 561.552 ;
        RECT  96.384 561.516 96.408 561.6 ;
    END
  END vi[73]
  PIN vi[74]
    DIRECTION INPUT ;
    USE SIGNAL ;
    PORT
      LAYER M3 ;
        RECT  97.38 559.345 97.398 561.581 ;
        RECT  97.38 561.562 97.398 561.6 ;
    END
  END vi[74]
  PIN vi[75]
    DIRECTION INPUT ;
    USE SIGNAL ;
    PORT
      LAYER M5 ;
        RECT  98.4 559.717 98.424 561.552 ;
        RECT  98.4 561.516 98.424 561.6 ;
    END
  END vi[75]
  PIN vi[76]
    DIRECTION INPUT ;
    USE SIGNAL ;
    PORT
      LAYER M3 ;
        RECT  99.432 559.457 99.45 561.581 ;
        RECT  99.432 561.562 99.45 561.6 ;
    END
  END vi[76]
  PIN vi[77]
    DIRECTION INPUT ;
    USE SIGNAL ;
    PORT
      LAYER M5 ;
        RECT  100.416 559.717 100.44 561.552 ;
        RECT  100.416 561.516 100.44 561.6 ;
    END
  END vi[77]
  PIN vi[78]
    DIRECTION INPUT ;
    USE SIGNAL ;
    PORT
      LAYER M3 ;
        RECT  101.448 561.569 101.466 561.581 ;
        RECT  101.448 561.541 101.538 561.569 ;
        RECT  101.448 561.562 101.466 561.6 ;
    END
  END vi[78]
  PIN vi[79]
    DIRECTION INPUT ;
    USE SIGNAL ;
    PORT
      LAYER M5 ;
        RECT  102.48 559.717 102.504 561.552 ;
        RECT  102.48 561.516 102.504 561.6 ;
    END
  END vi[79]
  PIN vi[7]
    DIRECTION INPUT ;
    USE SIGNAL ;
    PORT
      LAYER M5 ;
        RECT  29.232 559.463 29.256 561.552 ;
        RECT  29.232 561.516 29.256 561.6 ;
    END
  END vi[7]
  PIN vi[80]
    DIRECTION INPUT ;
    USE SIGNAL ;
    PORT
      LAYER M3 ;
        RECT  103.5 559.345 103.518 561.581 ;
        RECT  103.5 561.562 103.518 561.6 ;
    END
  END vi[80]
  PIN vi[81]
    DIRECTION INPUT ;
    USE SIGNAL ;
    PORT
      LAYER M5 ;
        RECT  104.496 559.717 104.52 561.552 ;
        RECT  104.496 561.516 104.52 561.6 ;
    END
  END vi[81]
  PIN vi[82]
    DIRECTION INPUT ;
    USE SIGNAL ;
    PORT
      LAYER M3 ;
        RECT  105.516 559.457 105.534 561.581 ;
        RECT  105.516 561.562 105.534 561.6 ;
    END
  END vi[82]
  PIN vi[83]
    DIRECTION INPUT ;
    USE SIGNAL ;
    PORT
      LAYER M5 ;
        RECT  106.56 559.333 106.584 561.552 ;
        RECT  106.56 561.516 106.584 561.6 ;
    END
  END vi[83]
  PIN vi[84]
    DIRECTION INPUT ;
    USE SIGNAL ;
    PORT
      LAYER M3 ;
        RECT  107.568 561.569 107.586 561.581 ;
        RECT  107.568 561.541 108.054 561.569 ;
        RECT  107.568 561.562 107.586 561.6 ;
    END
  END vi[84]
  PIN vi[85]
    DIRECTION INPUT ;
    USE SIGNAL ;
    PORT
      LAYER M5 ;
        RECT  108.576 559.717 108.6 561.552 ;
        RECT  108.576 561.516 108.6 561.6 ;
    END
  END vi[85]
  PIN vi[86]
    DIRECTION INPUT ;
    USE SIGNAL ;
    PORT
      LAYER M3 ;
        RECT  109.584 559.409 109.602 561.581 ;
        RECT  109.584 561.562 109.602 561.6 ;
    END
  END vi[86]
  PIN vi[87]
    DIRECTION INPUT ;
    USE SIGNAL ;
    PORT
      LAYER M5 ;
        RECT  110.592 559.463 110.616 561.552 ;
        RECT  110.592 561.516 110.616 561.6 ;
    END
  END vi[87]
  PIN vi[88]
    DIRECTION INPUT ;
    USE SIGNAL ;
    PORT
      LAYER M3 ;
        RECT  111.636 559.229 111.654 561.581 ;
        RECT  111.636 561.562 111.654 561.6 ;
    END
  END vi[88]
  PIN vi[89]
    DIRECTION INPUT ;
    USE SIGNAL ;
    PORT
      LAYER M5 ;
        RECT  112.656 559.717 112.68 561.552 ;
        RECT  112.656 561.516 112.68 561.6 ;
    END
  END vi[89]
  PIN vi[8]
    DIRECTION INPUT ;
    USE SIGNAL ;
    PORT
      LAYER M3 ;
        RECT  30.24 561.562 30.258 561.6 ;
    END
  END vi[8]
  PIN vi[90]
    DIRECTION INPUT ;
    USE SIGNAL ;
    PORT
      LAYER M3 ;
        RECT  113.652 559.345 113.67 561.581 ;
        RECT  113.652 561.562 113.67 561.6 ;
    END
  END vi[90]
  PIN vi[91]
    DIRECTION INPUT ;
    USE SIGNAL ;
    PORT
      LAYER M5 ;
        RECT  114.672 559.717 114.696 561.552 ;
        RECT  114.672 561.516 114.696 561.6 ;
    END
  END vi[91]
  PIN vi[92]
    DIRECTION INPUT ;
    USE SIGNAL ;
    PORT
      LAYER M3 ;
        RECT  115.704 559.457 115.722 561.581 ;
        RECT  115.704 561.562 115.722 561.6 ;
    END
  END vi[92]
  PIN vi[93]
    DIRECTION INPUT ;
    USE SIGNAL ;
    PORT
      LAYER M5 ;
        RECT  116.736 559.717 116.76 561.552 ;
        RECT  116.736 561.516 116.76 561.6 ;
    END
  END vi[93]
  PIN vi[94]
    DIRECTION INPUT ;
    USE SIGNAL ;
    PORT
      LAYER M3 ;
        RECT  117.72 559.345 117.738 561.581 ;
        RECT  117.72 561.562 117.738 561.6 ;
    END
  END vi[94]
  PIN vi[95]
    DIRECTION INPUT ;
    USE SIGNAL ;
    PORT
      LAYER M5 ;
        RECT  118.752 559.717 118.776 561.552 ;
        RECT  118.752 561.516 118.776 561.6 ;
    END
  END vi[95]
  PIN vi[96]
    DIRECTION INPUT ;
    USE SIGNAL ;
    PORT
      LAYER M3 ;
        RECT  119.772 559.229 119.79 561.581 ;
        RECT  119.772 561.562 119.79 561.6 ;
    END
  END vi[96]
  PIN vi[97]
    DIRECTION INPUT ;
    USE SIGNAL ;
    PORT
      LAYER M5 ;
        RECT  120.768 559.717 120.792 561.552 ;
        RECT  120.768 561.516 120.792 561.6 ;
    END
  END vi[97]
  PIN vi[98]
    DIRECTION INPUT ;
    USE SIGNAL ;
    PORT
      LAYER M3 ;
        RECT  121.788 559.457 121.806 561.581 ;
        RECT  121.788 561.562 121.806 561.6 ;
    END
  END vi[98]
  PIN vi[99]
    DIRECTION INPUT ;
    USE SIGNAL ;
    PORT
      LAYER M5 ;
        RECT  122.832 559.717 122.856 561.552 ;
        RECT  122.832 561.516 122.856 561.6 ;
    END
  END vi[99]
  PIN vi[9]
    DIRECTION INPUT ;
    USE SIGNAL ;
    PORT
      LAYER M5 ;
        RECT  31.248 561.516 31.272 561.6 ;
    END
  END vi[9]
  PIN vo[0]
    DIRECTION INPUT ;
    USE SIGNAL ;
    PORT
      LAYER M3 ;
        RECT  324.504 561.569 324.522 561.581 ;
        RECT  324.432 561.541 324.522 561.569 ;
        RECT  324.504 561.562 324.522 561.6 ;
    END
  END vo[0]
  PIN vo[100]
    DIRECTION INPUT ;
    USE SIGNAL ;
    PORT
      LAYER M3 ;
        RECT  426.24 559.409 426.258 561.581 ;
        RECT  426.24 561.562 426.258 561.6 ;
    END
  END vo[100]
  PIN vo[101]
    DIRECTION INPUT ;
    USE SIGNAL ;
    PORT
      LAYER M5 ;
        RECT  427.248 559.717 427.272 561.552 ;
        RECT  427.248 561.516 427.272 561.6 ;
    END
  END vo[101]
  PIN vo[102]
    DIRECTION INPUT ;
    USE SIGNAL ;
    PORT
      LAYER M3 ;
        RECT  428.292 559.457 428.31 561.581 ;
        RECT  428.292 561.562 428.31 561.6 ;
    END
  END vo[102]
  PIN vo[103]
    DIRECTION INPUT ;
    USE SIGNAL ;
    PORT
      LAYER M5 ;
        RECT  429.312 559.573 429.336 561.552 ;
        RECT  429.312 561.516 429.336 561.6 ;
    END
  END vo[103]
  PIN vo[104]
    DIRECTION INPUT ;
    USE SIGNAL ;
    PORT
      LAYER M3 ;
        RECT  430.308 559.229 430.326 561.581 ;
        RECT  430.308 561.562 430.326 561.6 ;
    END
  END vo[104]
  PIN vo[105]
    DIRECTION INPUT ;
    USE SIGNAL ;
    PORT
      LAYER M5 ;
        RECT  431.328 559.717 431.352 561.552 ;
        RECT  431.328 561.516 431.352 561.6 ;
    END
  END vo[105]
  PIN vo[106]
    DIRECTION INPUT ;
    USE SIGNAL ;
    PORT
      LAYER M3 ;
        RECT  432.36 559.309 432.378 561.581 ;
        RECT  432.36 561.562 432.378 561.6 ;
    END
  END vo[106]
  PIN vo[107]
    DIRECTION INPUT ;
    USE SIGNAL ;
    PORT
      LAYER M5 ;
        RECT  433.344 560.293 433.368 561.552 ;
        RECT  433.344 561.516 433.368 561.6 ;
    END
  END vo[107]
  PIN vo[108]
    DIRECTION INPUT ;
    USE SIGNAL ;
    PORT
      LAYER M3 ;
        RECT  434.376 559.457 434.394 561.581 ;
        RECT  434.376 561.562 434.394 561.6 ;
    END
  END vo[108]
  PIN vo[109]
    DIRECTION INPUT ;
    USE SIGNAL ;
    PORT
      LAYER M5 ;
        RECT  435.408 559.463 435.432 561.552 ;
        RECT  435.408 561.516 435.432 561.6 ;
    END
  END vo[109]
  PIN vo[10]
    DIRECTION INPUT ;
    USE SIGNAL ;
    PORT
      LAYER M3 ;
        RECT  334.692 561.562 334.71 561.6 ;
    END
  END vo[10]
  PIN vo[110]
    DIRECTION INPUT ;
    USE SIGNAL ;
    PORT
      LAYER M3 ;
        RECT  436.428 559.337 436.446 561.581 ;
        RECT  436.428 561.562 436.446 561.6 ;
    END
  END vo[110]
  PIN vo[111]
    DIRECTION INPUT ;
    USE SIGNAL ;
    PORT
      LAYER M5 ;
        RECT  437.424 559.381 437.448 561.552 ;
        RECT  437.424 561.516 437.448 561.6 ;
    END
  END vo[111]
  PIN vo[112]
    DIRECTION INPUT ;
    USE SIGNAL ;
    PORT
      LAYER M3 ;
        RECT  438.444 559.309 438.462 561.581 ;
        RECT  438.444 561.562 438.462 561.6 ;
    END
  END vo[112]
  PIN vo[113]
    DIRECTION INPUT ;
    USE SIGNAL ;
    PORT
      LAYER M5 ;
        RECT  439.44 559.463 439.464 561.552 ;
        RECT  439.44 561.516 439.464 561.6 ;
    END
  END vo[113]
  PIN vo[114]
    DIRECTION INPUT ;
    USE SIGNAL ;
    PORT
      LAYER M3 ;
        RECT  440.496 559.457 440.514 561.581 ;
        RECT  440.496 561.562 440.514 561.6 ;
    END
  END vo[114]
  PIN vo[115]
    DIRECTION INPUT ;
    USE SIGNAL ;
    PORT
      LAYER M5 ;
        RECT  441.504 559.189 441.528 561.552 ;
        RECT  441.504 561.516 441.528 561.6 ;
    END
  END vo[115]
  PIN vo[116]
    DIRECTION INPUT ;
    USE SIGNAL ;
    PORT
      LAYER M3 ;
        RECT  442.512 559.237 442.53 561.581 ;
        RECT  442.512 561.562 442.53 561.6 ;
    END
  END vo[116]
  PIN vo[117]
    DIRECTION INPUT ;
    USE SIGNAL ;
    PORT
      LAYER M5 ;
        RECT  443.52 561.445 443.544 561.552 ;
        RECT  443.52 561.516 443.544 561.6 ;
    END
  END vo[117]
  PIN vo[118]
    DIRECTION INPUT ;
    USE SIGNAL ;
    PORT
      LAYER M3 ;
        RECT  444.564 561.485 444.582 561.581 ;
        RECT  444.564 561.562 444.582 561.6 ;
    END
  END vo[118]
  PIN vo[119]
    DIRECTION INPUT ;
    USE SIGNAL ;
    PORT
      LAYER M5 ;
        RECT  445.584 561.445 445.608 561.552 ;
        RECT  445.584 561.516 445.608 561.6 ;
    END
  END vo[119]
  PIN vo[11]
    DIRECTION INPUT ;
    USE SIGNAL ;
    PORT
      LAYER M5 ;
        RECT  335.712 561.516 335.736 561.6 ;
    END
  END vo[11]
  PIN vo[120]
    DIRECTION INPUT ;
    USE SIGNAL ;
    PORT
      LAYER M3 ;
        RECT  446.58 559.409 446.598 561.581 ;
        RECT  446.58 561.562 446.598 561.6 ;
    END
  END vo[120]
  PIN vo[121]
    DIRECTION INPUT ;
    USE SIGNAL ;
    PORT
      LAYER M5 ;
        RECT  447.6 560.869 447.624 561.552 ;
        RECT  447.6 561.516 447.624 561.6 ;
    END
  END vo[121]
  PIN vo[122]
    DIRECTION INPUT ;
    USE SIGNAL ;
    PORT
      LAYER M3 ;
        RECT  448.632 559.565 448.65 561.581 ;
        RECT  448.632 561.562 448.65 561.6 ;
    END
  END vo[122]
  PIN vo[123]
    DIRECTION INPUT ;
    USE SIGNAL ;
    PORT
      LAYER M5 ;
        RECT  449.616 559.463 449.64 561.552 ;
        RECT  449.616 561.516 449.64 561.6 ;
    END
  END vo[123]
  PIN vo[124]
    DIRECTION INPUT ;
    USE SIGNAL ;
    PORT
      LAYER M3 ;
        RECT  450.648 559.724 450.666 561.581 ;
        RECT  450.648 561.562 450.666 561.6 ;
    END
  END vo[124]
  PIN vo[125]
    DIRECTION INPUT ;
    USE SIGNAL ;
    PORT
      LAYER M5 ;
        RECT  451.68 559.717 451.704 561.552 ;
        RECT  451.68 561.516 451.704 561.6 ;
    END
  END vo[125]
  PIN vo[126]
    DIRECTION INPUT ;
    USE SIGNAL ;
    PORT
      LAYER M3 ;
        RECT  452.7 561.499 452.718 561.581 ;
        RECT  452.7 561.562 452.718 561.6 ;
    END
  END vo[126]
  PIN vo[127]
    DIRECTION INPUT ;
    USE SIGNAL ;
    PORT
      LAYER M5 ;
        RECT  453.696 559.717 453.72 561.552 ;
        RECT  453.696 561.516 453.72 561.6 ;
    END
  END vo[127]
  PIN vo[128]
    DIRECTION INPUT ;
    USE SIGNAL ;
    PORT
      LAYER M3 ;
        RECT  454.716 559.805 454.734 561.581 ;
        RECT  454.716 561.562 454.734 561.6 ;
    END
  END vo[128]
  PIN vo[129]
    DIRECTION INPUT ;
    USE SIGNAL ;
    PORT
      LAYER M5 ;
        RECT  455.76 561.251 455.784 561.552 ;
        RECT  455.76 561.516 455.784 561.6 ;
    END
  END vo[129]
  PIN vo[12]
    DIRECTION INPUT ;
    USE SIGNAL ;
    PORT
      LAYER M3 ;
        RECT  336.708 561.562 336.726 561.6 ;
    END
  END vo[12]
  PIN vo[130]
    DIRECTION INPUT ;
    USE SIGNAL ;
    PORT
      LAYER M3 ;
        RECT  456.768 561.211 456.786 561.581 ;
        RECT  456.768 561.562 456.786 561.6 ;
    END
  END vo[130]
  PIN vo[131]
    DIRECTION INPUT ;
    USE SIGNAL ;
    PORT
      LAYER M5 ;
        RECT  457.776 559.717 457.8 561.552 ;
        RECT  457.776 561.516 457.8 561.6 ;
    END
  END vo[131]
  PIN vo[132]
    DIRECTION INPUT ;
    USE SIGNAL ;
    PORT
      LAYER M3 ;
        RECT  458.784 559.345 458.802 561.581 ;
        RECT  458.784 561.562 458.802 561.6 ;
    END
  END vo[132]
  PIN vo[133]
    DIRECTION INPUT ;
    USE SIGNAL ;
    PORT
      LAYER M5 ;
        RECT  459.792 559.717 459.816 561.552 ;
        RECT  459.792 561.516 459.816 561.6 ;
    END
  END vo[133]
  PIN vo[134]
    DIRECTION INPUT ;
    USE SIGNAL ;
    PORT
      LAYER M3 ;
        RECT  460.836 559.457 460.854 561.581 ;
        RECT  460.836 561.562 460.854 561.6 ;
    END
  END vo[134]
  PIN vo[135]
    DIRECTION INPUT ;
    USE SIGNAL ;
    PORT
      LAYER M5 ;
        RECT  461.856 559.463 461.88 561.552 ;
        RECT  461.856 561.516 461.88 561.6 ;
    END
  END vo[135]
  PIN vo[136]
    DIRECTION INPUT ;
    USE SIGNAL ;
    PORT
      LAYER M3 ;
        RECT  462.852 559.229 462.87 561.581 ;
        RECT  462.852 561.562 462.87 561.6 ;
    END
  END vo[136]
  PIN vo[137]
    DIRECTION INPUT ;
    USE SIGNAL ;
    PORT
      LAYER M5 ;
        RECT  463.872 559.381 463.896 561.552 ;
        RECT  463.872 561.516 463.896 561.6 ;
    END
  END vo[137]
  PIN vo[138]
    DIRECTION INPUT ;
    USE SIGNAL ;
    PORT
      LAYER M3 ;
        RECT  464.904 559.409 464.922 561.581 ;
        RECT  464.904 561.562 464.922 561.6 ;
    END
  END vo[138]
  PIN vo[139]
    DIRECTION INPUT ;
    USE SIGNAL ;
    PORT
      LAYER M5 ;
        RECT  465.936 561.539 465.96 561.552 ;
        RECT  465.936 559.717 466.824 561.539 ;
        RECT  465.936 561.516 465.96 561.6 ;
    END
  END vo[139]
  PIN vo[13]
    DIRECTION INPUT ;
    USE SIGNAL ;
    PORT
      LAYER M5 ;
        RECT  337.728 561.516 337.752 561.6 ;
    END
  END vo[13]
  PIN vo[140]
    DIRECTION INPUT ;
    USE SIGNAL ;
    PORT
      LAYER M3 ;
        RECT  466.92 561.499 466.938 561.581 ;
        RECT  466.92 561.562 466.938 561.6 ;
    END
  END vo[140]
  PIN vo[141]
    DIRECTION INPUT ;
    USE SIGNAL ;
    PORT
      LAYER M5 ;
        RECT  467.952 559.717 467.976 561.552 ;
        RECT  467.952 561.516 467.976 561.6 ;
    END
  END vo[141]
  PIN vo[142]
    DIRECTION INPUT ;
    USE SIGNAL ;
    PORT
      LAYER M3 ;
        RECT  468.972 559.409 468.99 561.581 ;
        RECT  468.972 561.562 468.99 561.6 ;
    END
  END vo[142]
  PIN vo[143]
    DIRECTION INPUT ;
    USE SIGNAL ;
    PORT
      LAYER M5 ;
        RECT  469.968 559.717 469.992 561.552 ;
        RECT  469.968 561.516 469.992 561.6 ;
    END
  END vo[143]
  PIN vo[144]
    DIRECTION INPUT ;
    USE SIGNAL ;
    PORT
      LAYER M3 ;
        RECT  470.988 559.409 471.006 561.581 ;
        RECT  470.988 561.562 471.006 561.6 ;
    END
  END vo[144]
  PIN vo[145]
    DIRECTION INPUT ;
    USE SIGNAL ;
    PORT
      LAYER M5 ;
        RECT  472.032 561.445 472.056 561.552 ;
        RECT  472.032 561.516 472.056 561.6 ;
    END
  END vo[145]
  PIN vo[146]
    DIRECTION INPUT ;
    USE SIGNAL ;
    PORT
      LAYER M3 ;
        RECT  473.04 559.229 473.058 561.581 ;
        RECT  473.04 561.562 473.058 561.6 ;
    END
  END vo[146]
  PIN vo[147]
    DIRECTION INPUT ;
    USE SIGNAL ;
    PORT
      LAYER M5 ;
        RECT  474.048 559.717 474.072 561.552 ;
        RECT  474.048 561.516 474.072 561.6 ;
    END
  END vo[147]
  PIN vo[148]
    DIRECTION INPUT ;
    USE SIGNAL ;
    PORT
      LAYER M3 ;
        RECT  475.092 559.421 475.11 561.581 ;
        RECT  475.092 561.562 475.11 561.6 ;
    END
  END vo[148]
  PIN vo[149]
    DIRECTION INPUT ;
    USE SIGNAL ;
    PORT
      LAYER M5 ;
        RECT  476.112 559.381 476.136 561.552 ;
        RECT  476.112 561.516 476.136 561.6 ;
    END
  END vo[149]
  PIN vo[14]
    DIRECTION INPUT ;
    USE SIGNAL ;
    PORT
      LAYER M3 ;
        RECT  338.76 561.562 338.778 561.6 ;
    END
  END vo[14]
  PIN vo[150]
    DIRECTION INPUT ;
    USE SIGNAL ;
    PORT
      LAYER M3 ;
        RECT  477.108 559.457 477.126 561.581 ;
        RECT  477.108 561.562 477.126 561.6 ;
    END
  END vo[150]
  PIN vo[151]
    DIRECTION INPUT ;
    USE SIGNAL ;
    PORT
      LAYER M5 ;
        RECT  478.128 559.717 478.152 561.552 ;
        RECT  478.128 561.516 478.152 561.6 ;
    END
  END vo[151]
  PIN vo[152]
    DIRECTION INPUT ;
    USE SIGNAL ;
    PORT
      LAYER M3 ;
        RECT  479.16 559.309 479.178 561.581 ;
        RECT  479.16 561.562 479.178 561.6 ;
    END
  END vo[152]
  PIN vo[153]
    DIRECTION INPUT ;
    USE SIGNAL ;
    PORT
      LAYER M5 ;
        RECT  480.144 559.717 480.168 561.552 ;
        RECT  480.144 561.516 480.168 561.6 ;
    END
  END vo[153]
  PIN vo[154]
    DIRECTION INPUT ;
    USE SIGNAL ;
    PORT
      LAYER M3 ;
        RECT  481.176 559.345 481.194 561.581 ;
        RECT  481.176 561.562 481.194 561.6 ;
    END
  END vo[154]
  PIN vo[155]
    DIRECTION INPUT ;
    USE SIGNAL ;
    PORT
      LAYER M5 ;
        RECT  482.208 560.869 482.232 561.552 ;
        RECT  482.208 561.516 482.232 561.6 ;
    END
  END vo[155]
  PIN vo[156]
    DIRECTION INPUT ;
    USE SIGNAL ;
    PORT
      LAYER M3 ;
        RECT  483.228 559.457 483.246 561.581 ;
        RECT  483.228 561.562 483.246 561.6 ;
    END
  END vo[156]
  PIN vo[157]
    DIRECTION INPUT ;
    USE SIGNAL ;
    PORT
      LAYER M5 ;
        RECT  484.224 559.717 484.248 561.552 ;
        RECT  484.224 561.516 484.248 561.6 ;
    END
  END vo[157]
  PIN vo[158]
    DIRECTION INPUT ;
    USE SIGNAL ;
    PORT
      LAYER M3 ;
        RECT  485.244 559.229 485.262 561.581 ;
        RECT  485.244 561.562 485.262 561.6 ;
    END
  END vo[158]
  PIN vo[159]
    DIRECTION INPUT ;
    USE SIGNAL ;
    PORT
      LAYER M5 ;
        RECT  486.24 559.717 486.264 561.552 ;
        RECT  486.24 561.516 486.264 561.6 ;
    END
  END vo[159]
  PIN vo[15]
    DIRECTION INPUT ;
    USE SIGNAL ;
    PORT
      LAYER M5 ;
        RECT  339.744 561.516 339.768 561.6 ;
    END
  END vo[15]
  PIN vo[160]
    DIRECTION INPUT ;
    USE SIGNAL ;
    PORT
      LAYER M3 ;
        RECT  487.296 561.499 487.314 561.581 ;
        RECT  487.296 561.562 487.314 561.6 ;
    END
  END vo[160]
  PIN vo[161]
    DIRECTION INPUT ;
    USE SIGNAL ;
    PORT
      LAYER M5 ;
        RECT  488.304 559.717 488.328 561.552 ;
        RECT  488.304 561.516 488.328 561.6 ;
    END
  END vo[161]
  PIN vo[162]
    DIRECTION INPUT ;
    USE SIGNAL ;
    PORT
      LAYER M3 ;
        RECT  489.312 561.499 489.33 561.581 ;
        RECT  489.312 561.562 489.33 561.6 ;
    END
  END vo[162]
  PIN vo[163]
    DIRECTION INPUT ;
    USE SIGNAL ;
    PORT
      LAYER M5 ;
        RECT  490.32 559.717 490.344 561.552 ;
        RECT  490.32 561.516 490.344 561.6 ;
    END
  END vo[163]
  PIN vo[164]
    DIRECTION INPUT ;
    USE SIGNAL ;
    PORT
      LAYER M3 ;
        RECT  491.364 559.757 491.382 561.581 ;
        RECT  491.364 561.562 491.382 561.6 ;
    END
  END vo[164]
  PIN vo[165]
    DIRECTION INPUT ;
    USE SIGNAL ;
    PORT
      LAYER M5 ;
        RECT  492.384 560.245 492.408 561.552 ;
        RECT  492.384 561.516 492.408 561.6 ;
    END
  END vo[165]
  PIN vo[166]
    DIRECTION INPUT ;
    USE SIGNAL ;
    PORT
      LAYER M3 ;
        RECT  493.38 559.457 493.398 561.581 ;
        RECT  493.38 561.562 493.398 561.6 ;
    END
  END vo[166]
  PIN vo[167]
    DIRECTION INPUT ;
    USE SIGNAL ;
    PORT
      LAYER M5 ;
        RECT  494.4 559.717 494.424 561.552 ;
        RECT  494.4 561.516 494.424 561.6 ;
    END
  END vo[167]
  PIN vo[168]
    DIRECTION INPUT ;
    USE SIGNAL ;
    PORT
      LAYER M3 ;
        RECT  495.432 559.757 495.45 561.581 ;
        RECT  495.432 561.562 495.45 561.6 ;
    END
  END vo[168]
  PIN vo[169]
    DIRECTION INPUT ;
    USE SIGNAL ;
    PORT
      LAYER M5 ;
        RECT  496.416 560.245 496.44 561.552 ;
        RECT  496.416 561.516 496.44 561.6 ;
    END
  END vo[169]
  PIN vo[16]
    DIRECTION INPUT ;
    USE SIGNAL ;
    PORT
      LAYER M3 ;
        RECT  340.776 561.562 340.794 561.6 ;
    END
  END vo[16]
  PIN vo[170]
    DIRECTION INPUT ;
    USE SIGNAL ;
    PORT
      LAYER M3 ;
        RECT  497.448 560.285 497.466 561.581 ;
        RECT  497.448 561.562 497.466 561.6 ;
    END
  END vo[170]
  PIN vo[171]
    DIRECTION INPUT ;
    USE SIGNAL ;
    PORT
      LAYER M5 ;
        RECT  498.48 559.717 498.504 561.552 ;
        RECT  498.48 561.516 498.504 561.6 ;
    END
  END vo[171]
  PIN vo[172]
    DIRECTION INPUT ;
    USE SIGNAL ;
    PORT
      LAYER M3 ;
        RECT  499.5 559.457 499.518 561.581 ;
        RECT  499.5 561.562 499.518 561.6 ;
    END
  END vo[172]
  PIN vo[173]
    DIRECTION INPUT ;
    USE SIGNAL ;
    PORT
      LAYER M5 ;
        RECT  500.496 559.141 500.52 561.552 ;
        RECT  500.496 561.516 500.52 561.6 ;
    END
  END vo[173]
  PIN vo[174]
    DIRECTION INPUT ;
    USE SIGNAL ;
    PORT
      LAYER M3 ;
        RECT  501.516 561.499 501.534 561.581 ;
        RECT  501.516 561.562 501.534 561.6 ;
    END
  END vo[174]
  PIN vo[175]
    DIRECTION INPUT ;
    USE SIGNAL ;
    PORT
      LAYER M5 ;
        RECT  502.56 559.717 502.584 561.552 ;
        RECT  502.56 561.516 502.584 561.6 ;
    END
  END vo[175]
  PIN vo[176]
    DIRECTION INPUT ;
    USE SIGNAL ;
    PORT
      LAYER M3 ;
        RECT  503.568 559.345 503.586 561.581 ;
        RECT  503.568 561.562 503.586 561.6 ;
    END
  END vo[176]
  PIN vo[177]
    DIRECTION INPUT ;
    USE SIGNAL ;
    PORT
      LAYER M5 ;
        RECT  504.576 559.717 504.6 561.552 ;
        RECT  504.576 561.516 504.6 561.6 ;
    END
  END vo[177]
  PIN vo[178]
    DIRECTION INPUT ;
    USE SIGNAL ;
    PORT
      LAYER M3 ;
        RECT  505.584 559.757 505.602 561.581 ;
        RECT  505.584 561.562 505.602 561.6 ;
    END
  END vo[178]
  PIN vo[179]
    DIRECTION INPUT ;
    USE SIGNAL ;
    PORT
      LAYER M5 ;
        RECT  506.592 560.245 506.616 561.552 ;
        RECT  506.592 561.516 506.616 561.6 ;
    END
  END vo[179]
  PIN vo[17]
    DIRECTION INPUT ;
    USE SIGNAL ;
    PORT
      LAYER M5 ;
        RECT  341.808 561.516 341.832 561.6 ;
    END
  END vo[17]
  PIN vo[180]
    DIRECTION INPUT ;
    USE SIGNAL ;
    PORT
      LAYER M3 ;
        RECT  507.636 559.301 507.654 561.581 ;
        RECT  507.636 561.562 507.654 561.6 ;
    END
  END vo[180]
  PIN vo[181]
    DIRECTION INPUT ;
    USE SIGNAL ;
    PORT
      LAYER M5 ;
        RECT  508.656 559.717 508.68 561.552 ;
        RECT  508.656 561.516 508.68 561.6 ;
    END
  END vo[181]
  PIN vo[182]
    DIRECTION INPUT ;
    USE SIGNAL ;
    PORT
      LAYER M3 ;
        RECT  509.652 559.757 509.67 561.581 ;
        RECT  509.652 561.562 509.67 561.6 ;
    END
  END vo[182]
  PIN vo[183]
    DIRECTION INPUT ;
    USE SIGNAL ;
    PORT
      LAYER M5 ;
        RECT  510.672 559.717 510.696 561.552 ;
        RECT  510.672 561.516 510.696 561.6 ;
    END
  END vo[183]
  PIN vo[184]
    DIRECTION INPUT ;
    USE SIGNAL ;
    PORT
      LAYER M3 ;
        RECT  511.704 559.757 511.722 561.581 ;
        RECT  511.704 561.562 511.722 561.6 ;
    END
  END vo[184]
  PIN vo[185]
    DIRECTION INPUT ;
    USE SIGNAL ;
    PORT
      LAYER M5 ;
        RECT  512.736 559.717 512.76 561.552 ;
        RECT  512.736 561.516 512.76 561.6 ;
    END
  END vo[185]
  PIN vo[186]
    DIRECTION INPUT ;
    USE SIGNAL ;
    PORT
      LAYER M3 ;
        RECT  513.72 559.337 513.738 561.581 ;
        RECT  513.72 561.562 513.738 561.6 ;
    END
  END vo[186]
  PIN vo[187]
    DIRECTION INPUT ;
    USE SIGNAL ;
    PORT
      LAYER M5 ;
        RECT  514.752 559.717 514.776 561.552 ;
        RECT  514.752 561.516 514.776 561.6 ;
    END
  END vo[187]
  PIN vo[188]
    DIRECTION INPUT ;
    USE SIGNAL ;
    PORT
      LAYER M3 ;
        RECT  515.772 559.457 515.79 561.581 ;
        RECT  515.772 561.562 515.79 561.6 ;
    END
  END vo[188]
  PIN vo[189]
    DIRECTION INPUT ;
    USE SIGNAL ;
    PORT
      LAYER M5 ;
        RECT  516.768 559.717 516.792 561.552 ;
        RECT  516.768 561.516 516.792 561.6 ;
    END
  END vo[189]
  PIN vo[18]
    DIRECTION INPUT ;
    USE SIGNAL ;
    PORT
      LAYER M3 ;
        RECT  342.828 561.562 342.846 561.6 ;
    END
  END vo[18]
  PIN vo[190]
    DIRECTION INPUT ;
    USE SIGNAL ;
    PORT
      LAYER M3 ;
        RECT  517.788 559.757 517.806 561.581 ;
        RECT  517.788 561.562 517.806 561.6 ;
    END
  END vo[190]
  PIN vo[191]
    DIRECTION INPUT ;
    USE SIGNAL ;
    PORT
      LAYER M5 ;
        RECT  518.832 559.717 518.856 561.552 ;
        RECT  518.832 561.516 518.856 561.6 ;
    END
  END vo[191]
  PIN vo[192]
    DIRECTION INPUT ;
    USE SIGNAL ;
    PORT
      LAYER M3 ;
        RECT  519.84 561.499 519.858 561.581 ;
        RECT  519.84 561.562 519.858 561.6 ;
    END
  END vo[192]
  PIN vo[193]
    DIRECTION INPUT ;
    USE SIGNAL ;
    PORT
      LAYER M5 ;
        RECT  520.848 559.463 520.872 561.552 ;
        RECT  520.848 561.516 520.872 561.6 ;
    END
  END vo[193]
  PIN vo[194]
    DIRECTION INPUT ;
    USE SIGNAL ;
    PORT
      LAYER M3 ;
        RECT  521.892 561.499 521.91 561.581 ;
        RECT  521.892 561.562 521.91 561.6 ;
    END
  END vo[194]
  PIN vo[195]
    DIRECTION INPUT ;
    USE SIGNAL ;
    PORT
      LAYER M5 ;
        RECT  522.912 559.717 522.936 561.552 ;
        RECT  522.912 561.516 522.936 561.6 ;
    END
  END vo[195]
  PIN vo[196]
    DIRECTION INPUT ;
    USE SIGNAL ;
    PORT
      LAYER M3 ;
        RECT  523.908 561.499 523.926 561.581 ;
        RECT  523.908 561.562 523.926 561.6 ;
    END
  END vo[196]
  PIN vo[197]
    DIRECTION INPUT ;
    USE SIGNAL ;
    PORT
      LAYER M5 ;
        RECT  524.928 559.381 524.952 561.552 ;
        RECT  524.928 561.516 524.952 561.6 ;
    END
  END vo[197]
  PIN vo[198]
    DIRECTION INPUT ;
    USE SIGNAL ;
    PORT
      LAYER M3 ;
        RECT  525.96 561.499 525.978 561.581 ;
        RECT  525.96 561.562 525.978 561.6 ;
    END
  END vo[198]
  PIN vo[199]
    DIRECTION INPUT ;
    USE SIGNAL ;
    PORT
      LAYER M5 ;
        RECT  526.944 561.539 526.968 561.552 ;
        RECT  525.984 559.525 526.968 561.539 ;
        RECT  526.944 561.516 526.968 561.6 ;
    END
  END vo[199]
  PIN vo[19]
    DIRECTION INPUT ;
    USE SIGNAL ;
    PORT
      LAYER M5 ;
        RECT  343.824 561.516 343.848 561.6 ;
    END
  END vo[19]
  PIN vo[1]
    DIRECTION INPUT ;
    USE SIGNAL ;
    PORT
      LAYER M5 ;
        RECT  325.536 559.717 325.56 561.552 ;
        RECT  325.536 561.516 325.56 561.6 ;
    END
  END vo[1]
  PIN vo[200]
    DIRECTION INPUT ;
    USE SIGNAL ;
    PORT
      LAYER M3 ;
        RECT  527.976 561.499 527.994 561.581 ;
        RECT  527.976 561.562 527.994 561.6 ;
    END
  END vo[200]
  PIN vo[201]
    DIRECTION INPUT ;
    USE SIGNAL ;
    PORT
      LAYER M5 ;
        RECT  529.008 559.717 529.032 561.552 ;
        RECT  529.008 561.516 529.032 561.6 ;
    END
  END vo[201]
  PIN vo[202]
    DIRECTION INPUT ;
    USE SIGNAL ;
    PORT
      LAYER M3 ;
        RECT  530.028 559.345 530.046 561.581 ;
        RECT  530.028 561.562 530.046 561.6 ;
    END
  END vo[202]
  PIN vo[203]
    DIRECTION INPUT ;
    USE SIGNAL ;
    PORT
      LAYER M5 ;
        RECT  531.024 559.717 531.048 561.552 ;
        RECT  531.024 561.516 531.048 561.6 ;
    END
  END vo[203]
  PIN vo[204]
    DIRECTION INPUT ;
    USE SIGNAL ;
    PORT
      LAYER M3 ;
        RECT  532.044 559.457 532.062 561.581 ;
        RECT  532.044 561.562 532.062 561.6 ;
    END
  END vo[204]
  PIN vo[205]
    DIRECTION INPUT ;
    USE SIGNAL ;
    PORT
      LAYER M5 ;
        RECT  533.04 559.717 533.064 561.552 ;
        RECT  533.04 561.516 533.064 561.6 ;
    END
  END vo[205]
  PIN vo[206]
    DIRECTION INPUT ;
    USE SIGNAL ;
    PORT
      LAYER M3 ;
        RECT  534.096 559.409 534.114 561.581 ;
        RECT  534.096 561.562 534.114 561.6 ;
    END
  END vo[206]
  PIN vo[207]
    DIRECTION INPUT ;
    USE SIGNAL ;
    PORT
      LAYER M5 ;
        RECT  535.104 559.717 535.128 561.552 ;
        RECT  535.104 561.516 535.128 561.6 ;
    END
  END vo[207]
  PIN vo[208]
    DIRECTION INPUT ;
    USE SIGNAL ;
    PORT
      LAYER M3 ;
        RECT  536.112 559.229 536.13 561.581 ;
        RECT  536.112 561.562 536.13 561.6 ;
    END
  END vo[208]
  PIN vo[209]
    DIRECTION INPUT ;
    USE SIGNAL ;
    PORT
      LAYER M5 ;
        RECT  537.12 559.463 537.144 561.552 ;
        RECT  537.12 561.516 537.144 561.6 ;
    END
  END vo[209]
  PIN vo[20]
    DIRECTION INPUT ;
    USE SIGNAL ;
    PORT
      LAYER M3 ;
        RECT  344.844 559.345 344.862 561.581 ;
        RECT  344.844 561.562 344.862 561.6 ;
    END
  END vo[20]
  PIN vo[210]
    DIRECTION INPUT ;
    USE SIGNAL ;
    PORT
      LAYER M3 ;
        RECT  538.164 559.265 538.182 561.581 ;
        RECT  538.164 561.562 538.182 561.6 ;
    END
  END vo[210]
  PIN vo[211]
    DIRECTION INPUT ;
    USE SIGNAL ;
    PORT
      LAYER M5 ;
        RECT  539.184 560.245 539.208 561.552 ;
        RECT  539.184 561.516 539.208 561.6 ;
    END
  END vo[211]
  PIN vo[212]
    DIRECTION INPUT ;
    USE SIGNAL ;
    PORT
      LAYER M3 ;
        RECT  540.18 559.337 540.198 561.581 ;
        RECT  540.18 561.562 540.198 561.6 ;
    END
  END vo[212]
  PIN vo[213]
    DIRECTION INPUT ;
    USE SIGNAL ;
    PORT
      LAYER M5 ;
        RECT  541.2 559.717 541.224 561.552 ;
        RECT  541.2 561.516 541.224 561.6 ;
    END
  END vo[213]
  PIN vo[214]
    DIRECTION INPUT ;
    USE SIGNAL ;
    PORT
      LAYER M3 ;
        RECT  542.232 559.724 542.25 561.581 ;
        RECT  542.232 561.562 542.25 561.6 ;
    END
  END vo[214]
  PIN vo[215]
    DIRECTION INPUT ;
    USE SIGNAL ;
    PORT
      LAYER M5 ;
        RECT  543.216 559.717 543.24 561.552 ;
        RECT  543.216 561.516 543.24 561.6 ;
    END
  END vo[215]
  PIN vo[216]
    DIRECTION INPUT ;
    USE SIGNAL ;
    PORT
      LAYER M3 ;
        RECT  544.248 559.345 544.266 561.581 ;
        RECT  544.248 561.562 544.266 561.6 ;
    END
  END vo[216]
  PIN vo[217]
    DIRECTION INPUT ;
    USE SIGNAL ;
    PORT
      LAYER M5 ;
        RECT  545.28 559.717 545.304 561.552 ;
        RECT  545.28 561.516 545.304 561.6 ;
    END
  END vo[217]
  PIN vo[218]
    DIRECTION INPUT ;
    USE SIGNAL ;
    PORT
      LAYER M3 ;
        RECT  546.3 559.345 546.318 561.581 ;
        RECT  546.3 561.562 546.318 561.6 ;
    END
  END vo[218]
  PIN vo[219]
    DIRECTION INPUT ;
    USE SIGNAL ;
    PORT
      LAYER M5 ;
        RECT  547.296 559.717 547.32 561.552 ;
        RECT  547.296 561.516 547.32 561.6 ;
    END
  END vo[219]
  PIN vo[21]
    DIRECTION INPUT ;
    USE SIGNAL ;
    PORT
      LAYER M5 ;
        RECT  345.84 559.381 345.864 561.552 ;
        RECT  345.84 561.516 345.864 561.6 ;
    END
  END vo[21]
  PIN vo[220]
    DIRECTION INPUT ;
    USE SIGNAL ;
    PORT
      LAYER M3 ;
        RECT  548.316 559.757 548.334 561.581 ;
        RECT  548.316 561.562 548.334 561.6 ;
    END
  END vo[220]
  PIN vo[221]
    DIRECTION INPUT ;
    USE SIGNAL ;
    PORT
      LAYER M5 ;
        RECT  549.36 560.245 549.384 561.552 ;
        RECT  549.36 561.516 549.384 561.6 ;
    END
  END vo[221]
  PIN vo[222]
    DIRECTION INPUT ;
    USE SIGNAL ;
    PORT
      LAYER M3 ;
        RECT  550.368 560.285 550.386 561.581 ;
        RECT  550.368 561.562 550.386 561.6 ;
    END
  END vo[222]
  PIN vo[223]
    DIRECTION INPUT ;
    USE SIGNAL ;
    PORT
      LAYER M5 ;
        RECT  551.376 560.245 551.4 561.552 ;
        RECT  551.376 561.516 551.4 561.6 ;
    END
  END vo[223]
  PIN vo[224]
    DIRECTION INPUT ;
    USE SIGNAL ;
    PORT
      LAYER M3 ;
        RECT  552.384 560.285 552.402 561.581 ;
        RECT  552.384 561.562 552.402 561.6 ;
    END
  END vo[224]
  PIN vo[225]
    DIRECTION INPUT ;
    USE SIGNAL ;
    PORT
      LAYER M5 ;
        RECT  553.392 559.463 553.416 561.552 ;
        RECT  553.392 561.516 553.416 561.6 ;
    END
  END vo[225]
  PIN vo[226]
    DIRECTION INPUT ;
    USE SIGNAL ;
    PORT
      LAYER M3 ;
        RECT  554.436 559.757 554.454 561.581 ;
        RECT  554.436 561.562 554.454 561.6 ;
    END
  END vo[226]
  PIN vo[227]
    DIRECTION INPUT ;
    USE SIGNAL ;
    PORT
      LAYER M5 ;
        RECT  555.456 559.717 555.48 561.552 ;
        RECT  555.456 561.516 555.48 561.6 ;
    END
  END vo[227]
  PIN vo[228]
    DIRECTION INPUT ;
    USE SIGNAL ;
    PORT
      LAYER M3 ;
        RECT  556.452 559.757 556.47 561.581 ;
        RECT  556.452 561.562 556.47 561.6 ;
    END
  END vo[228]
  PIN vo[229]
    DIRECTION INPUT ;
    USE SIGNAL ;
    PORT
      LAYER M5 ;
        RECT  557.472 559.717 557.496 561.552 ;
        RECT  557.472 561.516 557.496 561.6 ;
    END
  END vo[229]
  PIN vo[22]
    DIRECTION INPUT ;
    USE SIGNAL ;
    PORT
      LAYER M3 ;
        RECT  346.896 559.409 346.914 561.581 ;
        RECT  346.896 561.562 346.914 561.6 ;
    END
  END vo[22]
  PIN vo[230]
    DIRECTION INPUT ;
    USE SIGNAL ;
    PORT
      LAYER M3 ;
        RECT  558.504 559.457 558.522 561.581 ;
        RECT  558.504 561.562 558.522 561.6 ;
    END
  END vo[230]
  PIN vo[231]
    DIRECTION INPUT ;
    USE SIGNAL ;
    PORT
      LAYER M5 ;
        RECT  559.536 559.717 559.56 561.552 ;
        RECT  559.536 561.516 559.56 561.6 ;
    END
  END vo[231]
  PIN vo[232]
    DIRECTION INPUT ;
    USE SIGNAL ;
    PORT
      LAYER M3 ;
        RECT  560.52 559.345 560.538 561.581 ;
        RECT  560.52 561.562 560.538 561.6 ;
    END
  END vo[232]
  PIN vo[233]
    DIRECTION INPUT ;
    USE SIGNAL ;
    PORT
      LAYER M5 ;
        RECT  561.552 559.717 561.576 561.552 ;
        RECT  561.552 561.516 561.576 561.6 ;
    END
  END vo[233]
  PIN vo[234]
    DIRECTION INPUT ;
    USE SIGNAL ;
    PORT
      LAYER M3 ;
        RECT  562.572 559.229 562.59 561.581 ;
        RECT  562.572 561.562 562.59 561.6 ;
    END
  END vo[234]
  PIN vo[235]
    DIRECTION INPUT ;
    USE SIGNAL ;
    PORT
      LAYER M5 ;
        RECT  563.568 559.717 563.592 561.552 ;
        RECT  563.568 561.516 563.592 561.6 ;
    END
  END vo[235]
  PIN vo[236]
    DIRECTION INPUT ;
    USE SIGNAL ;
    PORT
      LAYER M3 ;
        RECT  564.588 559.457 564.606 561.581 ;
        RECT  564.588 561.562 564.606 561.6 ;
    END
  END vo[236]
  PIN vo[237]
    DIRECTION INPUT ;
    USE SIGNAL ;
    PORT
      LAYER M5 ;
        RECT  565.632 559.381 565.656 561.552 ;
        RECT  565.632 561.516 565.656 561.6 ;
    END
  END vo[237]
  PIN vo[238]
    DIRECTION INPUT ;
    USE SIGNAL ;
    PORT
      LAYER M3 ;
        RECT  566.64 559.229 566.658 561.581 ;
        RECT  566.64 561.562 566.658 561.6 ;
    END
  END vo[238]
  PIN vo[239]
    DIRECTION INPUT ;
    USE SIGNAL ;
    PORT
      LAYER M5 ;
        RECT  567.648 559.381 567.672 561.552 ;
        RECT  567.648 561.516 567.672 561.6 ;
    END
  END vo[239]
  PIN vo[23]
    DIRECTION INPUT ;
    USE SIGNAL ;
    PORT
      LAYER M5 ;
        RECT  347.904 559.463 347.928 561.552 ;
        RECT  347.904 561.516 347.928 561.6 ;
    END
  END vo[23]
  PIN vo[240]
    DIRECTION INPUT ;
    USE SIGNAL ;
    PORT
      LAYER M3 ;
        RECT  568.692 559.457 568.71 561.581 ;
        RECT  568.692 561.562 568.71 561.6 ;
    END
  END vo[240]
  PIN vo[241]
    DIRECTION INPUT ;
    USE SIGNAL ;
    PORT
      LAYER M5 ;
        RECT  569.712 559.525 569.736 561.552 ;
        RECT  569.712 561.516 569.736 561.6 ;
    END
  END vo[241]
  PIN vo[242]
    DIRECTION INPUT ;
    USE SIGNAL ;
    PORT
      LAYER M3 ;
        RECT  570.708 559.229 570.726 561.581 ;
        RECT  570.708 561.562 570.726 561.6 ;
    END
  END vo[242]
  PIN vo[243]
    DIRECTION INPUT ;
    USE SIGNAL ;
    PORT
      LAYER M5 ;
        RECT  571.728 559.717 571.752 561.552 ;
        RECT  571.728 561.516 571.752 561.6 ;
    END
  END vo[243]
  PIN vo[244]
    DIRECTION INPUT ;
    USE SIGNAL ;
    PORT
      LAYER M3 ;
        RECT  572.76 559.229 572.778 561.581 ;
        RECT  572.76 561.562 572.778 561.6 ;
    END
  END vo[244]
  PIN vo[245]
    DIRECTION INPUT ;
    USE SIGNAL ;
    PORT
      LAYER M5 ;
        RECT  573.744 559.717 573.768 561.552 ;
        RECT  573.744 561.516 573.768 561.6 ;
    END
  END vo[245]
  PIN vo[246]
    DIRECTION INPUT ;
    USE SIGNAL ;
    PORT
      LAYER M3 ;
        RECT  574.776 559.457 574.794 561.581 ;
        RECT  574.776 561.562 574.794 561.6 ;
    END
  END vo[246]
  PIN vo[247]
    DIRECTION INPUT ;
    USE SIGNAL ;
    PORT
      LAYER M5 ;
        RECT  575.808 559.463 575.832 561.552 ;
        RECT  575.808 561.516 575.832 561.6 ;
    END
  END vo[247]
  PIN vo[248]
    DIRECTION INPUT ;
    USE SIGNAL ;
    PORT
      LAYER M3 ;
        RECT  576.828 559.757 576.846 561.581 ;
        RECT  576.828 561.562 576.846 561.6 ;
    END
  END vo[248]
  PIN vo[249]
    DIRECTION INPUT ;
    USE SIGNAL ;
    PORT
      LAYER M5 ;
        RECT  577.824 559.717 577.848 561.552 ;
        RECT  577.824 561.516 577.848 561.6 ;
    END
  END vo[249]
  PIN vo[24]
    DIRECTION INPUT ;
    USE SIGNAL ;
    PORT
      LAYER M3 ;
        RECT  348.912 559.409 348.93 561.581 ;
        RECT  348.912 561.562 348.93 561.6 ;
    END
  END vo[24]
  PIN vo[250]
    DIRECTION INPUT ;
    USE SIGNAL ;
    PORT
      LAYER M3 ;
        RECT  578.844 559.075 578.862 561.581 ;
        RECT  578.844 561.562 578.862 561.6 ;
    END
  END vo[250]
  PIN vo[251]
    DIRECTION INPUT ;
    USE SIGNAL ;
    PORT
      LAYER M5 ;
        RECT  579.84 560.869 579.864 561.552 ;
        RECT  579.84 561.516 579.864 561.6 ;
    END
  END vo[251]
  PIN vo[252]
    DIRECTION INPUT ;
    USE SIGNAL ;
    PORT
      LAYER M3 ;
        RECT  580.896 559.457 580.914 561.581 ;
        RECT  580.896 561.562 580.914 561.6 ;
    END
  END vo[252]
  PIN vo[253]
    DIRECTION INPUT ;
    USE SIGNAL ;
    PORT
      LAYER M5 ;
        RECT  581.904 559.189 581.928 561.552 ;
        RECT  581.904 561.516 581.928 561.6 ;
    END
  END vo[253]
  PIN vo[254]
    DIRECTION INPUT ;
    USE SIGNAL ;
    PORT
      LAYER M3 ;
        RECT  582.912 559.345 582.93 561.581 ;
        RECT  582.912 561.562 582.93 561.6 ;
    END
  END vo[254]
  PIN vo[255]
    DIRECTION INPUT ;
    USE SIGNAL ;
    PORT
      LAYER M5 ;
        RECT  583.92 559.717 583.944 561.552 ;
        RECT  583.92 561.516 583.944 561.6 ;
    END
  END vo[255]
  PIN vo[256]
    DIRECTION INPUT ;
    USE SIGNAL ;
    PORT
      LAYER M3 ;
        RECT  584.964 560.909 584.982 561.581 ;
        RECT  584.964 561.562 584.982 561.6 ;
    END
  END vo[256]
  PIN vo[257]
    DIRECTION INPUT ;
    USE SIGNAL ;
    PORT
      LAYER M5 ;
        RECT  585.984 560.869 586.008 561.552 ;
        RECT  585.984 561.516 586.008 561.6 ;
    END
  END vo[257]
  PIN vo[258]
    DIRECTION INPUT ;
    USE SIGNAL ;
    PORT
      LAYER M3 ;
        RECT  586.98 558.869 586.998 561.581 ;
        RECT  586.98 561.562 586.998 561.6 ;
    END
  END vo[258]
  PIN vo[259]
    DIRECTION INPUT ;
    USE SIGNAL ;
    PORT
      LAYER M5 ;
        RECT  588 559.381 588.024 561.552 ;
        RECT  588 561.516 588.024 561.6 ;
    END
  END vo[259]
  PIN vo[25]
    DIRECTION INPUT ;
    USE SIGNAL ;
    PORT
      LAYER M5 ;
        RECT  349.92 559.381 349.944 561.552 ;
        RECT  349.92 561.516 349.944 561.6 ;
    END
  END vo[25]
  PIN vo[260]
    DIRECTION INPUT ;
    USE SIGNAL ;
    PORT
      LAYER M3 ;
        RECT  589.032 560.285 589.05 561.581 ;
        RECT  589.032 561.562 589.05 561.6 ;
    END
  END vo[260]
  PIN vo[261]
    DIRECTION INPUT ;
    USE SIGNAL ;
    PORT
      LAYER M5 ;
        RECT  590.016 560.245 590.04 561.552 ;
        RECT  590.016 561.516 590.04 561.6 ;
    END
  END vo[261]
  PIN vo[262]
    DIRECTION INPUT ;
    USE SIGNAL ;
    PORT
      LAYER M3 ;
        RECT  591.048 561.569 591.066 561.581 ;
        RECT  590.976 561.541 591.066 561.569 ;
        RECT  591.048 561.562 591.066 561.6 ;
    END
  END vo[262]
  PIN vo[263]
    DIRECTION INPUT ;
    USE SIGNAL ;
    PORT
      LAYER M5 ;
        RECT  592.08 559.463 592.104 561.552 ;
        RECT  592.08 561.516 592.104 561.6 ;
    END
  END vo[263]
  PIN vo[264]
    DIRECTION INPUT ;
    USE SIGNAL ;
    PORT
      LAYER M3 ;
        RECT  593.1 560.909 593.118 561.581 ;
        RECT  593.1 561.562 593.118 561.6 ;
    END
  END vo[264]
  PIN vo[265]
    DIRECTION INPUT ;
    USE SIGNAL ;
    PORT
      LAYER M5 ;
        RECT  594.096 560.869 594.12 561.552 ;
        RECT  594.096 561.516 594.12 561.6 ;
    END
  END vo[265]
  PIN vo[266]
    DIRECTION INPUT ;
    USE SIGNAL ;
    PORT
      LAYER M3 ;
        RECT  595.116 559.757 595.134 561.581 ;
        RECT  595.116 561.562 595.134 561.6 ;
    END
  END vo[266]
  PIN vo[267]
    DIRECTION INPUT ;
    USE SIGNAL ;
    PORT
      LAYER M5 ;
        RECT  596.16 559.717 596.184 561.552 ;
        RECT  596.16 561.516 596.184 561.6 ;
    END
  END vo[267]
  PIN vo[268]
    DIRECTION INPUT ;
    USE SIGNAL ;
    PORT
      LAYER M3 ;
        RECT  597.168 559.457 597.186 561.581 ;
        RECT  597.168 561.562 597.186 561.6 ;
    END
  END vo[268]
  PIN vo[269]
    DIRECTION INPUT ;
    USE SIGNAL ;
    PORT
      LAYER M5 ;
        RECT  598.176 559.717 598.2 561.552 ;
        RECT  598.176 561.516 598.2 561.6 ;
    END
  END vo[269]
  PIN vo[26]
    DIRECTION INPUT ;
    USE SIGNAL ;
    PORT
      LAYER M3 ;
        RECT  350.964 559.409 350.982 561.581 ;
        RECT  350.964 561.562 350.982 561.6 ;
    END
  END vo[26]
  PIN vo[270]
    DIRECTION INPUT ;
    USE SIGNAL ;
    PORT
      LAYER M3 ;
        RECT  599.184 558.805 599.202 561.581 ;
        RECT  599.184 561.562 599.202 561.6 ;
    END
  END vo[270]
  PIN vo[271]
    DIRECTION INPUT ;
    USE SIGNAL ;
    PORT
      LAYER M5 ;
        RECT  600.192 559.381 600.216 561.552 ;
        RECT  600.192 561.516 600.216 561.6 ;
    END
  END vo[271]
  PIN vo[272]
    DIRECTION INPUT ;
    USE SIGNAL ;
    PORT
      LAYER M3 ;
        RECT  601.236 559.457 601.254 561.581 ;
        RECT  601.236 561.562 601.254 561.6 ;
    END
  END vo[272]
  PIN vo[273]
    DIRECTION INPUT ;
    USE SIGNAL ;
    PORT
      LAYER M5 ;
        RECT  602.256 559.463 602.28 561.552 ;
        RECT  602.256 561.516 602.28 561.6 ;
    END
  END vo[273]
  PIN vo[274]
    DIRECTION INPUT ;
    USE SIGNAL ;
    PORT
      LAYER M3 ;
        RECT  603.252 559.345 603.27 561.581 ;
        RECT  603.252 561.562 603.27 561.6 ;
    END
  END vo[274]
  PIN vo[275]
    DIRECTION INPUT ;
    USE SIGNAL ;
    PORT
      LAYER M5 ;
        RECT  604.272 560.869 604.296 561.552 ;
        RECT  604.272 561.516 604.296 561.6 ;
    END
  END vo[275]
  PIN vo[27]
    DIRECTION INPUT ;
    USE SIGNAL ;
    PORT
      LAYER M5 ;
        RECT  351.984 559.381 352.008 561.552 ;
        RECT  351.984 561.516 352.008 561.6 ;
    END
  END vo[27]
  PIN vo[28]
    DIRECTION INPUT ;
    USE SIGNAL ;
    PORT
      LAYER M3 ;
        RECT  352.98 559.457 352.998 561.581 ;
        RECT  352.98 561.562 352.998 561.6 ;
    END
  END vo[28]
  PIN vo[29]
    DIRECTION INPUT ;
    USE SIGNAL ;
    PORT
      LAYER M5 ;
        RECT  354 560.869 354.024 561.552 ;
        RECT  354 561.516 354.024 561.6 ;
    END
  END vo[29]
  PIN vo[2]
    DIRECTION INPUT ;
    USE SIGNAL ;
    PORT
      LAYER M3 ;
        RECT  326.52 559.724 326.538 561.581 ;
        RECT  326.52 561.562 326.538 561.6 ;
    END
  END vo[2]
  PIN vo[30]
    DIRECTION INPUT ;
    USE SIGNAL ;
    PORT
      LAYER M3 ;
        RECT  355.032 559.409 355.05 561.581 ;
        RECT  355.032 561.562 355.05 561.6 ;
    END
  END vo[30]
  PIN vo[31]
    DIRECTION INPUT ;
    USE SIGNAL ;
    PORT
      LAYER M5 ;
        RECT  356.016 559.381 356.04 561.552 ;
        RECT  356.016 561.516 356.04 561.6 ;
    END
  END vo[31]
  PIN vo[32]
    DIRECTION INPUT ;
    USE SIGNAL ;
    PORT
      LAYER M3 ;
        RECT  357.048 559.229 357.066 561.581 ;
        RECT  357.048 561.562 357.066 561.6 ;
    END
  END vo[32]
  PIN vo[33]
    DIRECTION INPUT ;
    USE SIGNAL ;
    PORT
      LAYER M5 ;
        RECT  358.08 559.717 358.104 561.552 ;
        RECT  358.08 561.516 358.104 561.6 ;
    END
  END vo[33]
  PIN vo[34]
    DIRECTION INPUT ;
    USE SIGNAL ;
    PORT
      LAYER M3 ;
        RECT  359.1 561.569 359.118 561.581 ;
        RECT  359.1 561.541 359.442 561.569 ;
        RECT  359.1 561.562 359.118 561.6 ;
    END
  END vo[34]
  PIN vo[35]
    DIRECTION INPUT ;
    USE SIGNAL ;
    PORT
      LAYER M5 ;
        RECT  360.096 560.245 360.12 561.552 ;
        RECT  360.096 561.516 360.12 561.6 ;
    END
  END vo[35]
  PIN vo[36]
    DIRECTION INPUT ;
    USE SIGNAL ;
    PORT
      LAYER M3 ;
        RECT  361.116 560.285 361.134 561.581 ;
        RECT  361.116 561.562 361.134 561.6 ;
    END
  END vo[36]
  PIN vo[37]
    DIRECTION INPUT ;
    USE SIGNAL ;
    PORT
      LAYER M5 ;
        RECT  362.16 560.245 362.184 561.552 ;
        RECT  362.16 561.516 362.184 561.6 ;
    END
  END vo[37]
  PIN vo[38]
    DIRECTION INPUT ;
    USE SIGNAL ;
    PORT
      LAYER M3 ;
        RECT  363.168 560.285 363.186 561.581 ;
        RECT  363.168 561.562 363.186 561.6 ;
    END
  END vo[38]
  PIN vo[39]
    DIRECTION INPUT ;
    USE SIGNAL ;
    PORT
      LAYER M5 ;
        RECT  364.176 559.717 364.2 561.552 ;
        RECT  364.176 561.516 364.2 561.6 ;
    END
  END vo[39]
  PIN vo[3]
    DIRECTION INPUT ;
    USE SIGNAL ;
    PORT
      LAYER M5 ;
        RECT  327.552 559.717 327.576 561.552 ;
        RECT  327.552 561.516 327.576 561.6 ;
    END
  END vo[3]
  PIN vo[40]
    DIRECTION INPUT ;
    USE SIGNAL ;
    PORT
      LAYER M3 ;
        RECT  365.184 559.345 365.202 561.581 ;
        RECT  365.184 561.562 365.202 561.6 ;
    END
  END vo[40]
  PIN vo[41]
    DIRECTION INPUT ;
    USE SIGNAL ;
    PORT
      LAYER M5 ;
        RECT  366.192 559.717 366.216 561.552 ;
        RECT  366.192 561.516 366.216 561.6 ;
    END
  END vo[41]
  PIN vo[42]
    DIRECTION INPUT ;
    USE SIGNAL ;
    PORT
      LAYER M3 ;
        RECT  367.236 559.345 367.254 561.581 ;
        RECT  367.236 561.562 367.254 561.6 ;
    END
  END vo[42]
  PIN vo[43]
    DIRECTION INPUT ;
    USE SIGNAL ;
    PORT
      LAYER M5 ;
        RECT  368.256 561.445 368.28 561.552 ;
        RECT  368.256 561.516 368.28 561.6 ;
    END
  END vo[43]
  PIN vo[44]
    DIRECTION INPUT ;
    USE SIGNAL ;
    PORT
      LAYER M3 ;
        RECT  369.252 559.457 369.27 561.581 ;
        RECT  369.252 561.562 369.27 561.6 ;
    END
  END vo[44]
  PIN vo[45]
    DIRECTION INPUT ;
    USE SIGNAL ;
    PORT
      LAYER M5 ;
        RECT  370.272 561.539 370.296 561.552 ;
        RECT  370.272 559.669 371.064 561.539 ;
        RECT  370.272 561.516 370.296 561.6 ;
    END
  END vo[45]
  PIN vo[46]
    DIRECTION INPUT ;
    USE SIGNAL ;
    PORT
      LAYER M3 ;
        RECT  371.304 561.499 371.322 561.581 ;
        RECT  371.304 561.562 371.322 561.6 ;
    END
  END vo[46]
  PIN vo[47]
    DIRECTION INPUT ;
    USE SIGNAL ;
    PORT
      LAYER M5 ;
        RECT  372.336 559.571 372.36 561.552 ;
        RECT  372.336 561.516 372.36 561.6 ;
    END
  END vo[47]
  PIN vo[48]
    DIRECTION INPUT ;
    USE SIGNAL ;
    PORT
      LAYER M3 ;
        RECT  373.32 559.805 373.338 561.581 ;
        RECT  373.32 561.562 373.338 561.6 ;
    END
  END vo[48]
  PIN vo[49]
    DIRECTION INPUT ;
    USE SIGNAL ;
    PORT
      LAYER M5 ;
        RECT  374.352 559.717 374.376 561.552 ;
        RECT  374.352 561.516 374.376 561.6 ;
    END
  END vo[49]
  PIN vo[4]
    DIRECTION INPUT ;
    USE SIGNAL ;
    PORT
      LAYER M3 ;
        RECT  328.572 561.562 328.59 561.6 ;
    END
  END vo[4]
  PIN vo[50]
    DIRECTION INPUT ;
    USE SIGNAL ;
    PORT
      LAYER M3 ;
        RECT  375.372 559.457 375.39 561.581 ;
        RECT  375.372 561.562 375.39 561.6 ;
    END
  END vo[50]
  PIN vo[51]
    DIRECTION INPUT ;
    USE SIGNAL ;
    PORT
      LAYER M5 ;
        RECT  376.368 559.381 376.392 561.552 ;
        RECT  376.368 561.516 376.392 561.6 ;
    END
  END vo[51]
  PIN vo[52]
    DIRECTION INPUT ;
    USE SIGNAL ;
    PORT
      LAYER M3 ;
        RECT  377.388 559.229 377.406 561.581 ;
        RECT  377.388 561.562 377.406 561.6 ;
    END
  END vo[52]
  PIN vo[53]
    DIRECTION INPUT ;
    USE SIGNAL ;
    PORT
      LAYER M5 ;
        RECT  378.432 559.717 378.456 561.552 ;
        RECT  378.432 561.516 378.456 561.6 ;
    END
  END vo[53]
  PIN vo[54]
    DIRECTION INPUT ;
    USE SIGNAL ;
    PORT
      LAYER M3 ;
        RECT  379.44 559.273 379.458 561.581 ;
        RECT  379.44 561.562 379.458 561.6 ;
    END
  END vo[54]
  PIN vo[55]
    DIRECTION INPUT ;
    USE SIGNAL ;
    PORT
      LAYER M5 ;
        RECT  380.448 559.463 380.472 561.552 ;
        RECT  380.448 561.516 380.472 561.6 ;
    END
  END vo[55]
  PIN vo[56]
    DIRECTION INPUT ;
    USE SIGNAL ;
    PORT
      LAYER M3 ;
        RECT  381.492 559.075 381.51 561.581 ;
        RECT  381.492 561.562 381.51 561.6 ;
    END
  END vo[56]
  PIN vo[57]
    DIRECTION INPUT ;
    USE SIGNAL ;
    PORT
      LAYER M5 ;
        RECT  382.512 560.869 382.536 561.552 ;
        RECT  382.512 561.516 382.536 561.6 ;
    END
  END vo[57]
  PIN vo[58]
    DIRECTION INPUT ;
    USE SIGNAL ;
    PORT
      LAYER M3 ;
        RECT  383.508 559.309 383.526 561.581 ;
        RECT  383.508 561.562 383.526 561.6 ;
    END
  END vo[58]
  PIN vo[59]
    DIRECTION INPUT ;
    USE SIGNAL ;
    PORT
      LAYER M5 ;
        RECT  384.528 559.717 384.552 561.552 ;
        RECT  384.528 561.516 384.552 561.6 ;
    END
  END vo[59]
  PIN vo[5]
    DIRECTION INPUT ;
    USE SIGNAL ;
    PORT
      LAYER M5 ;
        RECT  329.568 561.516 329.592 561.6 ;
    END
  END vo[5]
  PIN vo[60]
    DIRECTION INPUT ;
    USE SIGNAL ;
    PORT
      LAYER M3 ;
        RECT  385.56 559.457 385.578 561.581 ;
        RECT  385.56 561.562 385.578 561.6 ;
    END
  END vo[60]
  PIN vo[61]
    DIRECTION INPUT ;
    USE SIGNAL ;
    PORT
      LAYER M5 ;
        RECT  386.544 559.463 386.568 561.552 ;
        RECT  386.544 561.516 386.568 561.6 ;
    END
  END vo[61]
  PIN vo[62]
    DIRECTION INPUT ;
    USE SIGNAL ;
    PORT
      LAYER M3 ;
        RECT  387.576 559.229 387.594 561.581 ;
        RECT  387.576 561.562 387.594 561.6 ;
    END
  END vo[62]
  PIN vo[63]
    DIRECTION INPUT ;
    USE SIGNAL ;
    PORT
      LAYER M5 ;
        RECT  388.608 559.381 388.632 561.552 ;
        RECT  388.608 561.516 388.632 561.6 ;
    END
  END vo[63]
  PIN vo[64]
    DIRECTION INPUT ;
    USE SIGNAL ;
    PORT
      LAYER M3 ;
        RECT  389.628 559.409 389.646 561.581 ;
        RECT  389.628 561.562 389.646 561.6 ;
    END
  END vo[64]
  PIN vo[65]
    DIRECTION INPUT ;
    USE SIGNAL ;
    PORT
      LAYER M5 ;
        RECT  390.624 560.869 390.648 561.552 ;
        RECT  390.624 561.516 390.648 561.6 ;
    END
  END vo[65]
  PIN vo[66]
    DIRECTION INPUT ;
    USE SIGNAL ;
    PORT
      LAYER M3 ;
        RECT  391.644 559.457 391.662 561.581 ;
        RECT  391.644 561.562 391.662 561.6 ;
    END
  END vo[66]
  PIN vo[67]
    DIRECTION INPUT ;
    USE SIGNAL ;
    PORT
      LAYER M5 ;
        RECT  392.64 559.381 392.664 561.552 ;
        RECT  392.64 561.516 392.664 561.6 ;
    END
  END vo[67]
  PIN vo[68]
    DIRECTION INPUT ;
    USE SIGNAL ;
    PORT
      LAYER M3 ;
        RECT  393.696 559.409 393.714 561.581 ;
        RECT  393.696 561.562 393.714 561.6 ;
    END
  END vo[68]
  PIN vo[69]
    DIRECTION INPUT ;
    USE SIGNAL ;
    PORT
      LAYER M5 ;
        RECT  394.704 559.717 394.728 561.552 ;
        RECT  394.704 561.516 394.728 561.6 ;
    END
  END vo[69]
  PIN vo[6]
    DIRECTION INPUT ;
    USE SIGNAL ;
    PORT
      LAYER M3 ;
        RECT  330.588 559.409 330.606 561.581 ;
        RECT  330.588 561.562 330.606 561.6 ;
    END
  END vo[6]
  PIN vo[70]
    DIRECTION INPUT ;
    USE SIGNAL ;
    PORT
      LAYER M3 ;
        RECT  395.712 559.237 395.73 561.581 ;
        RECT  395.712 561.562 395.73 561.6 ;
    END
  END vo[70]
  PIN vo[71]
    DIRECTION INPUT ;
    USE SIGNAL ;
    PORT
      LAYER M5 ;
        RECT  396.72 559.463 396.744 561.552 ;
        RECT  396.72 561.516 396.744 561.6 ;
    END
  END vo[71]
  PIN vo[72]
    DIRECTION INPUT ;
    USE SIGNAL ;
    PORT
      LAYER M3 ;
        RECT  397.764 558.869 397.782 561.581 ;
        RECT  397.764 561.562 397.782 561.6 ;
    END
  END vo[72]
  PIN vo[73]
    DIRECTION INPUT ;
    USE SIGNAL ;
    PORT
      LAYER M5 ;
        RECT  398.784 559.717 398.808 561.552 ;
        RECT  398.784 561.516 398.808 561.6 ;
    END
  END vo[73]
  PIN vo[74]
    DIRECTION INPUT ;
    USE SIGNAL ;
    PORT
      LAYER M3 ;
        RECT  399.78 559.237 399.798 561.581 ;
        RECT  399.78 561.562 399.798 561.6 ;
    END
  END vo[74]
  PIN vo[75]
    DIRECTION INPUT ;
    USE SIGNAL ;
    PORT
      LAYER M5 ;
        RECT  400.8 559.717 400.824 561.552 ;
        RECT  400.8 561.516 400.824 561.6 ;
    END
  END vo[75]
  PIN vo[76]
    DIRECTION INPUT ;
    USE SIGNAL ;
    PORT
      LAYER M3 ;
        RECT  401.832 559.457 401.85 561.581 ;
        RECT  401.832 561.562 401.85 561.6 ;
    END
  END vo[76]
  PIN vo[77]
    DIRECTION INPUT ;
    USE SIGNAL ;
    PORT
      LAYER M5 ;
        RECT  402.816 559.463 402.84 561.552 ;
        RECT  402.816 561.516 402.84 561.6 ;
    END
  END vo[77]
  PIN vo[78]
    DIRECTION INPUT ;
    USE SIGNAL ;
    PORT
      LAYER M3 ;
        RECT  403.848 559.409 403.866 561.581 ;
        RECT  403.848 561.562 403.866 561.6 ;
    END
  END vo[78]
  PIN vo[79]
    DIRECTION INPUT ;
    USE SIGNAL ;
    PORT
      LAYER M5 ;
        RECT  404.88 559.381 404.904 561.552 ;
        RECT  404.88 561.516 404.904 561.6 ;
    END
  END vo[79]
  PIN vo[7]
    DIRECTION INPUT ;
    USE SIGNAL ;
    PORT
      LAYER M5 ;
        RECT  331.632 561.516 331.656 561.6 ;
    END
  END vo[7]
  PIN vo[80]
    DIRECTION INPUT ;
    USE SIGNAL ;
    PORT
      LAYER M3 ;
        RECT  405.9 559.409 405.918 561.581 ;
        RECT  405.9 561.562 405.918 561.6 ;
    END
  END vo[80]
  PIN vo[81]
    DIRECTION INPUT ;
    USE SIGNAL ;
    PORT
      LAYER M5 ;
        RECT  406.896 559.463 406.92 561.552 ;
        RECT  406.896 561.516 406.92 561.6 ;
    END
  END vo[81]
  PIN vo[82]
    DIRECTION INPUT ;
    USE SIGNAL ;
    PORT
      LAYER M3 ;
        RECT  407.916 559.457 407.934 561.581 ;
        RECT  407.916 561.562 407.934 561.6 ;
    END
  END vo[82]
  PIN vo[83]
    DIRECTION INPUT ;
    USE SIGNAL ;
    PORT
      LAYER M5 ;
        RECT  408.96 559.381 408.984 561.552 ;
        RECT  408.96 561.516 408.984 561.6 ;
    END
  END vo[83]
  PIN vo[84]
    DIRECTION INPUT ;
    USE SIGNAL ;
    PORT
      LAYER M3 ;
        RECT  409.968 559.229 409.986 561.581 ;
        RECT  409.968 561.562 409.986 561.6 ;
    END
  END vo[84]
  PIN vo[85]
    DIRECTION INPUT ;
    USE SIGNAL ;
    PORT
      LAYER M5 ;
        RECT  410.976 559.717 411 561.552 ;
        RECT  410.976 561.516 411 561.6 ;
    END
  END vo[85]
  PIN vo[86]
    DIRECTION INPUT ;
    USE SIGNAL ;
    PORT
      LAYER M3 ;
        RECT  411.984 559.229 412.002 561.581 ;
        RECT  411.984 561.562 412.002 561.6 ;
    END
  END vo[86]
  PIN vo[87]
    DIRECTION INPUT ;
    USE SIGNAL ;
    PORT
      LAYER M5 ;
        RECT  412.992 559.463 413.016 561.552 ;
        RECT  412.992 561.516 413.016 561.6 ;
    END
  END vo[87]
  PIN vo[88]
    DIRECTION INPUT ;
    USE SIGNAL ;
    PORT
      LAYER M3 ;
        RECT  414.036 559.409 414.054 561.581 ;
        RECT  414.036 561.562 414.054 561.6 ;
    END
  END vo[88]
  PIN vo[89]
    DIRECTION INPUT ;
    USE SIGNAL ;
    PORT
      LAYER M5 ;
        RECT  415.056 559.717 415.08 561.552 ;
        RECT  415.056 561.516 415.08 561.6 ;
    END
  END vo[89]
  PIN vo[8]
    DIRECTION INPUT ;
    USE SIGNAL ;
    PORT
      LAYER M3 ;
        RECT  332.64 561.562 332.658 561.6 ;
    END
  END vo[8]
  PIN vo[90]
    DIRECTION INPUT ;
    USE SIGNAL ;
    PORT
      LAYER M3 ;
        RECT  416.052 559.757 416.07 561.581 ;
        RECT  416.052 561.562 416.07 561.6 ;
    END
  END vo[90]
  PIN vo[91]
    DIRECTION INPUT ;
    USE SIGNAL ;
    PORT
      LAYER M5 ;
        RECT  417.072 559.717 417.096 561.552 ;
        RECT  417.072 561.516 417.096 561.6 ;
    END
  END vo[91]
  PIN vo[92]
    DIRECTION INPUT ;
    USE SIGNAL ;
    PORT
      LAYER M3 ;
        RECT  418.104 559.457 418.122 561.581 ;
        RECT  418.104 561.562 418.122 561.6 ;
    END
  END vo[92]
  PIN vo[93]
    DIRECTION INPUT ;
    USE SIGNAL ;
    PORT
      LAYER M5 ;
        RECT  419.136 559.717 419.16 561.552 ;
        RECT  419.136 561.516 419.16 561.6 ;
    END
  END vo[93]
  PIN vo[94]
    DIRECTION INPUT ;
    USE SIGNAL ;
    PORT
      LAYER M3 ;
        RECT  420.12 559.229 420.138 561.581 ;
        RECT  420.12 561.562 420.138 561.6 ;
    END
  END vo[94]
  PIN vo[95]
    DIRECTION INPUT ;
    USE SIGNAL ;
    PORT
      LAYER M5 ;
        RECT  421.152 559.717 421.176 561.552 ;
        RECT  421.152 561.516 421.176 561.6 ;
    END
  END vo[95]
  PIN vo[96]
    DIRECTION INPUT ;
    USE SIGNAL ;
    PORT
      LAYER M3 ;
        RECT  422.172 559.229 422.19 561.581 ;
        RECT  422.172 561.562 422.19 561.6 ;
    END
  END vo[96]
  PIN vo[97]
    DIRECTION INPUT ;
    USE SIGNAL ;
    PORT
      LAYER M5 ;
        RECT  423.168 559.717 423.192 561.552 ;
        RECT  423.168 561.516 423.192 561.6 ;
    END
  END vo[97]
  PIN vo[98]
    DIRECTION INPUT ;
    USE SIGNAL ;
    PORT
      LAYER M3 ;
        RECT  424.188 559.457 424.206 561.581 ;
        RECT  424.188 561.562 424.206 561.6 ;
    END
  END vo[98]
  PIN vo[99]
    DIRECTION INPUT ;
    USE SIGNAL ;
    PORT
      LAYER M5 ;
        RECT  425.232 559.381 425.256 561.552 ;
        RECT  425.232 561.516 425.256 561.6 ;
    END
  END vo[99]
  PIN vo[9]
    DIRECTION INPUT ;
    USE SIGNAL ;
    PORT
      LAYER M5 ;
        RECT  333.648 561.516 333.672 561.6 ;
    END
  END vo[9]
  PIN VDD
    DIRECTION INOUT ;
    USE POWER ;
    PORT
      LAYER M5 ;
        RECT  619.956 4.311 620.076 557.289 ;
        RECT  615.636 4.311 615.756 557.289 ;
        RECT  611.316 4.311 611.436 557.289 ;
        RECT  606.996 4.311 607.116 557.289 ;
        RECT  602.676 4.311 602.796 557.289 ;
        RECT  598.356 4.311 598.476 557.289 ;
        RECT  594.036 4.311 594.156 557.289 ;
        RECT  589.716 4.311 589.836 557.289 ;
        RECT  585.396 4.311 585.516 557.289 ;
        RECT  581.076 4.311 581.196 557.289 ;
        RECT  576.756 4.311 576.876 557.289 ;
        RECT  572.436 4.311 572.556 557.289 ;
        RECT  568.116 4.311 568.236 557.289 ;
        RECT  563.796 4.311 563.916 557.289 ;
        RECT  559.476 4.311 559.596 557.289 ;
        RECT  555.156 4.311 555.276 557.289 ;
        RECT  550.836 4.311 550.956 557.289 ;
        RECT  546.516 4.311 546.636 557.289 ;
        RECT  542.196 4.311 542.316 557.289 ;
        RECT  537.876 4.311 537.996 557.289 ;
        RECT  533.556 4.311 533.676 557.289 ;
        RECT  529.236 4.311 529.356 557.289 ;
        RECT  524.916 4.311 525.036 557.289 ;
        RECT  520.596 4.311 520.716 557.289 ;
        RECT  516.276 4.311 516.396 557.289 ;
        RECT  511.956 4.311 512.076 557.289 ;
        RECT  507.636 4.311 507.756 557.289 ;
        RECT  503.316 4.311 503.436 557.289 ;
        RECT  498.996 4.311 499.116 557.289 ;
        RECT  494.676 4.311 494.796 557.289 ;
        RECT  490.356 4.311 490.476 557.289 ;
        RECT  486.036 4.311 486.156 557.289 ;
        RECT  481.716 4.311 481.836 557.289 ;
        RECT  477.396 4.311 477.516 557.289 ;
        RECT  473.076 4.311 473.196 557.289 ;
        RECT  468.756 4.311 468.876 557.289 ;
        RECT  464.436 4.311 464.556 557.289 ;
        RECT  460.116 4.311 460.236 557.289 ;
        RECT  455.796 4.311 455.916 557.289 ;
        RECT  451.476 4.311 451.596 557.289 ;
        RECT  447.156 4.311 447.276 557.289 ;
        RECT  442.836 4.311 442.956 557.289 ;
        RECT  438.516 4.311 438.636 557.289 ;
        RECT  434.196 4.311 434.316 557.289 ;
        RECT  429.876 4.311 429.996 557.289 ;
        RECT  425.556 4.311 425.676 557.289 ;
        RECT  421.236 4.311 421.356 557.289 ;
        RECT  416.916 4.311 417.036 557.289 ;
        RECT  412.596 4.311 412.716 557.289 ;
        RECT  408.276 4.311 408.396 557.289 ;
        RECT  403.956 4.311 404.076 557.289 ;
        RECT  399.636 4.311 399.756 557.289 ;
        RECT  395.316 4.311 395.436 557.289 ;
        RECT  390.996 4.311 391.116 557.289 ;
        RECT  386.676 4.311 386.796 557.289 ;
        RECT  382.356 4.311 382.476 557.289 ;
        RECT  378.036 4.311 378.156 557.289 ;
        RECT  373.716 4.311 373.836 557.289 ;
        RECT  369.396 4.311 369.516 557.289 ;
        RECT  365.076 4.311 365.196 557.289 ;
        RECT  360.756 4.311 360.876 557.289 ;
        RECT  356.436 4.311 356.556 557.289 ;
        RECT  352.116 4.311 352.236 557.289 ;
        RECT  347.796 4.311 347.916 557.289 ;
        RECT  343.476 4.311 343.596 557.289 ;
        RECT  339.156 4.311 339.276 557.289 ;
        RECT  334.836 4.311 334.956 557.289 ;
        RECT  330.516 4.311 330.636 557.289 ;
        RECT  326.196 4.311 326.316 557.289 ;
        RECT  321.876 4.311 321.996 557.289 ;
        RECT  317.556 4.311 317.676 557.289 ;
        RECT  313.236 4.311 313.356 557.289 ;
        RECT  308.916 4.311 309.036 557.289 ;
        RECT  304.596 4.311 304.716 557.289 ;
        RECT  300.276 4.311 300.396 557.289 ;
        RECT  295.956 4.311 296.076 557.289 ;
        RECT  291.636 4.311 291.756 557.289 ;
        RECT  287.316 4.311 287.436 557.289 ;
        RECT  282.996 4.311 283.116 557.289 ;
        RECT  278.676 4.311 278.796 557.289 ;
        RECT  274.356 4.311 274.476 557.289 ;
        RECT  270.036 4.311 270.156 557.289 ;
        RECT  265.716 4.311 265.836 557.289 ;
        RECT  261.396 4.311 261.516 557.289 ;
        RECT  257.076 4.311 257.196 557.289 ;
        RECT  252.756 4.311 252.876 557.289 ;
        RECT  248.436 4.311 248.556 557.289 ;
        RECT  244.116 4.311 244.236 557.289 ;
        RECT  239.796 4.311 239.916 557.289 ;
        RECT  235.476 4.311 235.596 557.289 ;
        RECT  231.156 4.311 231.276 557.289 ;
        RECT  226.836 4.311 226.956 557.289 ;
        RECT  222.516 4.311 222.636 557.289 ;
        RECT  218.196 4.311 218.316 557.289 ;
        RECT  213.876 4.311 213.996 557.289 ;
        RECT  209.556 4.311 209.676 557.289 ;
        RECT  205.236 4.311 205.356 557.289 ;
        RECT  200.916 4.311 201.036 557.289 ;
        RECT  196.596 4.311 196.716 557.289 ;
        RECT  192.276 4.311 192.396 557.289 ;
        RECT  187.956 4.311 188.076 557.289 ;
        RECT  183.636 4.311 183.756 557.289 ;
        RECT  179.316 4.311 179.436 557.289 ;
        RECT  174.996 4.311 175.116 557.289 ;
        RECT  170.676 4.311 170.796 557.289 ;
        RECT  166.356 4.311 166.476 557.289 ;
        RECT  162.036 4.311 162.156 557.289 ;
        RECT  157.716 4.311 157.836 557.289 ;
        RECT  153.396 4.311 153.516 557.289 ;
        RECT  149.076 4.311 149.196 557.289 ;
        RECT  144.756 4.311 144.876 557.289 ;
        RECT  140.436 4.311 140.556 557.289 ;
        RECT  136.116 4.311 136.236 557.289 ;
        RECT  131.796 4.311 131.916 557.289 ;
        RECT  127.476 4.311 127.596 557.289 ;
        RECT  123.156 4.311 123.276 557.289 ;
        RECT  118.836 4.311 118.956 557.289 ;
        RECT  114.516 4.311 114.636 557.289 ;
        RECT  110.196 4.311 110.316 557.289 ;
        RECT  105.876 4.311 105.996 557.289 ;
        RECT  101.556 4.311 101.676 557.289 ;
        RECT  97.236 4.311 97.356 557.289 ;
        RECT  92.916 4.311 93.036 557.289 ;
        RECT  88.596 4.311 88.716 557.289 ;
        RECT  84.276 4.311 84.396 557.289 ;
        RECT  79.956 4.311 80.076 557.289 ;
        RECT  75.636 4.311 75.756 557.289 ;
        RECT  71.316 4.311 71.436 557.289 ;
        RECT  66.996 4.311 67.116 557.289 ;
        RECT  62.676 4.311 62.796 557.289 ;
        RECT  58.356 4.311 58.476 557.289 ;
        RECT  54.036 4.311 54.156 557.289 ;
        RECT  49.716 4.311 49.836 557.289 ;
        RECT  45.396 4.311 45.516 557.289 ;
        RECT  41.076 4.311 41.196 557.289 ;
        RECT  36.756 4.311 36.876 557.289 ;
        RECT  32.436 4.311 32.556 557.289 ;
        RECT  28.116 4.311 28.236 557.289 ;
        RECT  23.796 4.311 23.916 557.289 ;
        RECT  19.476 4.311 19.596 557.289 ;
        RECT  15.156 4.311 15.276 557.289 ;
        RECT  10.836 4.311 10.956 557.289 ;
        RECT  6.516 4.311 6.636 557.289 ;
    END
  END VDD
  PIN VSS
    DIRECTION INOUT ;
    USE GROUND ;
    PORT
      LAYER M5 ;
        RECT  619.764 4.297 619.884 557.303 ;
        RECT  615.444 4.297 615.564 557.303 ;
        RECT  611.124 4.297 611.244 557.303 ;
        RECT  606.804 4.297 606.924 557.303 ;
        RECT  602.484 4.297 602.604 557.303 ;
        RECT  598.164 4.297 598.284 557.303 ;
        RECT  593.844 4.297 593.964 557.303 ;
        RECT  589.524 4.297 589.644 557.303 ;
        RECT  585.204 4.297 585.324 557.303 ;
        RECT  580.884 4.297 581.004 557.303 ;
        RECT  576.564 4.297 576.684 557.303 ;
        RECT  572.244 4.297 572.364 557.303 ;
        RECT  567.924 4.297 568.044 557.303 ;
        RECT  563.604 4.297 563.724 557.303 ;
        RECT  559.284 4.297 559.404 557.303 ;
        RECT  554.964 4.297 555.084 557.303 ;
        RECT  550.644 4.297 550.764 557.303 ;
        RECT  546.324 4.297 546.444 557.303 ;
        RECT  542.004 4.297 542.124 557.303 ;
        RECT  537.684 4.297 537.804 557.303 ;
        RECT  533.364 4.297 533.484 557.303 ;
        RECT  529.044 4.297 529.164 557.303 ;
        RECT  524.724 4.297 524.844 557.303 ;
        RECT  520.404 4.297 520.524 557.303 ;
        RECT  516.084 4.297 516.204 557.303 ;
        RECT  511.764 4.297 511.884 557.303 ;
        RECT  507.444 4.297 507.564 557.303 ;
        RECT  503.124 4.297 503.244 557.303 ;
        RECT  498.804 4.297 498.924 557.303 ;
        RECT  494.484 4.297 494.604 557.303 ;
        RECT  490.164 4.297 490.284 557.303 ;
        RECT  485.844 4.297 485.964 557.303 ;
        RECT  481.524 4.297 481.644 557.303 ;
        RECT  477.204 4.297 477.324 557.303 ;
        RECT  472.884 4.297 473.004 557.303 ;
        RECT  468.564 4.297 468.684 557.303 ;
        RECT  464.244 4.297 464.364 557.303 ;
        RECT  459.924 4.297 460.044 557.303 ;
        RECT  455.604 4.297 455.724 557.303 ;
        RECT  451.284 4.297 451.404 557.303 ;
        RECT  446.964 4.297 447.084 557.303 ;
        RECT  442.644 4.297 442.764 557.303 ;
        RECT  438.324 4.297 438.444 557.303 ;
        RECT  434.004 4.297 434.124 557.303 ;
        RECT  429.684 4.297 429.804 557.303 ;
        RECT  425.364 4.297 425.484 557.303 ;
        RECT  421.044 4.297 421.164 557.303 ;
        RECT  416.724 4.297 416.844 557.303 ;
        RECT  412.404 4.297 412.524 557.303 ;
        RECT  408.084 4.297 408.204 557.303 ;
        RECT  403.764 4.297 403.884 557.303 ;
        RECT  399.444 4.297 399.564 557.303 ;
        RECT  395.124 4.297 395.244 557.303 ;
        RECT  390.804 4.297 390.924 557.303 ;
        RECT  386.484 4.297 386.604 557.303 ;
        RECT  382.164 4.297 382.284 557.303 ;
        RECT  377.844 4.297 377.964 557.303 ;
        RECT  373.524 4.297 373.644 557.303 ;
        RECT  369.204 4.297 369.324 557.303 ;
        RECT  364.884 4.297 365.004 557.303 ;
        RECT  360.564 4.297 360.684 557.303 ;
        RECT  356.244 4.297 356.364 557.303 ;
        RECT  351.924 4.297 352.044 557.303 ;
        RECT  347.604 4.297 347.724 557.303 ;
        RECT  343.284 4.297 343.404 557.303 ;
        RECT  338.964 4.297 339.084 557.303 ;
        RECT  334.644 4.297 334.764 557.303 ;
        RECT  330.324 4.297 330.444 557.303 ;
        RECT  326.004 4.297 326.124 557.303 ;
        RECT  321.684 4.297 321.804 557.303 ;
        RECT  317.364 4.297 317.484 557.303 ;
        RECT  313.044 4.297 313.164 557.303 ;
        RECT  308.724 4.297 308.844 557.303 ;
        RECT  304.404 4.297 304.524 557.303 ;
        RECT  300.084 4.297 300.204 557.303 ;
        RECT  295.764 4.297 295.884 557.303 ;
        RECT  291.444 4.297 291.564 557.303 ;
        RECT  287.124 4.297 287.244 557.303 ;
        RECT  282.804 4.297 282.924 557.303 ;
        RECT  278.484 4.297 278.604 557.303 ;
        RECT  274.164 4.297 274.284 557.303 ;
        RECT  269.844 4.297 269.964 557.303 ;
        RECT  265.524 4.297 265.644 557.303 ;
        RECT  261.204 4.297 261.324 557.303 ;
        RECT  256.884 4.297 257.004 557.303 ;
        RECT  252.564 4.297 252.684 557.303 ;
        RECT  248.244 4.297 248.364 557.303 ;
        RECT  243.924 4.297 244.044 557.303 ;
        RECT  239.604 4.297 239.724 557.303 ;
        RECT  235.284 4.297 235.404 557.303 ;
        RECT  230.964 4.297 231.084 557.303 ;
        RECT  226.644 4.297 226.764 557.303 ;
        RECT  222.324 4.297 222.444 557.303 ;
        RECT  218.004 4.297 218.124 557.303 ;
        RECT  213.684 4.297 213.804 557.303 ;
        RECT  209.364 4.297 209.484 557.303 ;
        RECT  205.044 4.297 205.164 557.303 ;
        RECT  200.724 4.297 200.844 557.303 ;
        RECT  196.404 4.297 196.524 557.303 ;
        RECT  192.084 4.297 192.204 557.303 ;
        RECT  187.764 4.297 187.884 557.303 ;
        RECT  183.444 4.297 183.564 557.303 ;
        RECT  179.124 4.297 179.244 557.303 ;
        RECT  174.804 4.297 174.924 557.303 ;
        RECT  170.484 4.297 170.604 557.303 ;
        RECT  166.164 4.297 166.284 557.303 ;
        RECT  161.844 4.297 161.964 557.303 ;
        RECT  157.524 4.297 157.644 557.303 ;
        RECT  153.204 4.297 153.324 557.303 ;
        RECT  148.884 4.297 149.004 557.303 ;
        RECT  144.564 4.297 144.684 557.303 ;
        RECT  140.244 4.297 140.364 557.303 ;
        RECT  135.924 4.297 136.044 557.303 ;
        RECT  131.604 4.297 131.724 557.303 ;
        RECT  127.284 4.297 127.404 557.303 ;
        RECT  122.964 4.297 123.084 557.303 ;
        RECT  118.644 4.297 118.764 557.303 ;
        RECT  114.324 4.297 114.444 557.303 ;
        RECT  110.004 4.297 110.124 557.303 ;
        RECT  105.684 4.297 105.804 557.303 ;
        RECT  101.364 4.297 101.484 557.303 ;
        RECT  97.044 4.297 97.164 557.303 ;
        RECT  92.724 4.297 92.844 557.303 ;
        RECT  88.404 4.297 88.524 557.303 ;
        RECT  84.084 4.297 84.204 557.303 ;
        RECT  79.764 4.297 79.884 557.303 ;
        RECT  75.444 4.297 75.564 557.303 ;
        RECT  71.124 4.297 71.244 557.303 ;
        RECT  66.804 4.297 66.924 557.303 ;
        RECT  62.484 4.297 62.604 557.303 ;
        RECT  58.164 4.297 58.284 557.303 ;
        RECT  53.844 4.297 53.964 557.303 ;
        RECT  49.524 4.297 49.644 557.303 ;
        RECT  45.204 4.297 45.324 557.303 ;
        RECT  40.884 4.297 41.004 557.303 ;
        RECT  36.564 4.297 36.684 557.303 ;
        RECT  32.244 4.297 32.364 557.303 ;
        RECT  27.924 4.297 28.044 557.303 ;
        RECT  23.604 4.297 23.724 557.303 ;
        RECT  19.284 4.297 19.404 557.303 ;
        RECT  14.964 4.297 15.084 557.303 ;
        RECT  10.644 4.297 10.764 557.303 ;
        RECT  6.324 4.297 6.444 557.303 ;
    END
  END VSS
  OBS
    LAYER RVTN ;
     RECT  0 0 622.08 561.6 ;
    LAYER RVTP ;
     RECT  0 0 622.08 561.6 ;
    LAYER M1 ;
     RECT  0 0 622.08 561.6 ;
    LAYER M2 ;
     RECT  0 0 622.08 561.6 ;
    LAYER M3 ;
     RECT  0 0 622.08 561.6 ;
    LAYER M4 ;
     RECT  0 0 622.08 561.6 ;
    LAYER M5 ;
     RECT  0 0 622.08 561.6 ;
  END
END dsdv_idx_tx_n32
END LIBRARY
